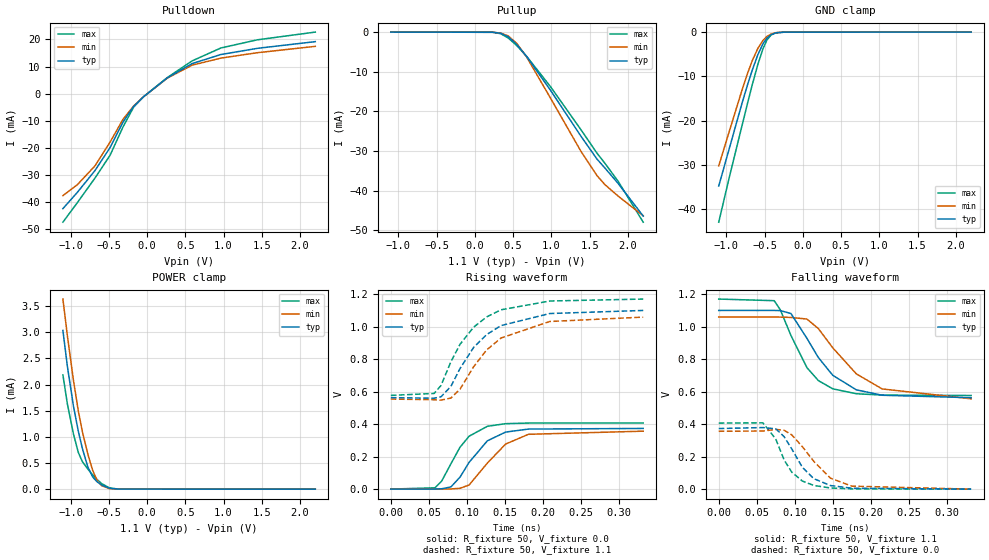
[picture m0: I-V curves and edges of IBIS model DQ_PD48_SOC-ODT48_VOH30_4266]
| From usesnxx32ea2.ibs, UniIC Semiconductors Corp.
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| DQ_PD48_SOC-ODT48_VOH30_4266
| (48 Ohm Pulldown, 48 Ohm System ODT Setting, VOH=VDDQ/3.0, 3200-4266Mbps)
[Model]   DQ_PD48_SOC-ODT48_VOH30_4266
Model_type   I/O
Vinl = 123.333mV
Vinh = 243.333mV
Vmeas = 183.333mV
Vref = 0.0mV
Cref = 0.0pF
Rref = 48.000Ohm
|   typ   min   max
|C_comp   0.834pF   0.784pF   0.884pF
C_comp_pullup   0.4170pF   0.3920pF   0.4420pF
C_comp_pulldown   0.4170pF   0.3920pF   0.4420pF
| Note: C_comp changes when the ODT circuit is enabled.
[Model Spec]
| Input threshold voltage corners
Vinl   0.1233V   0.1167V   0.1350V
Vinh   0.2433V   0.2367V   0.2550V
| Measurement voltage corners
Vmeas   0.1833V   0.1767V   0.1950V
| Timing spec test load voltage corners
Vref   0.0000V   0.0000V   0.0000V
| Dynamic Overshoot Parameters from LPDDR4 Specification
D_overshoot_ampl_h   0.30   NA   NA
D_overshoot_ampl_l   0.30   NA   NA
D_overshoot_area_h   0.1n   NA   NA
D_overshoot_area_l   0.1n   NA   NA
[Voltage Range]   1.1000V   1.0600V   1.1700V
[Pullup Reference]   1.1000V   1.0600V   1.1700V
| Junction Temperature (Ambient temp is 35C typ 95C min -40C max)
[Temperature Range]   50.0   110.0   -40.0
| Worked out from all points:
|   slope of the pulldown table from 0 to 0.165 V, typ, clamps not added: 43.9 ohm
|   slope of the pullup table from 0 to 0.165 V, typ, clamps not added: 15.7 kohm
|   GND clamp passes 1 mA (typ) near -0.45 V on its own axis
|   POWER clamp passes 1 mA (typ) near -0.88 V on its own axis
|   rising waveform, R_fixture 50, V_fixture 0.0: 20-80 % time 36.2ps typ, 40.6ps min, 31.9ps max; typ from 0.001 V to 0.373 V
|   falling waveform, R_fixture 50, V_fixture 1.1: 20-80 % time 49.2ps typ, 61ps min, 39.1ps max; typ from 1.1 V to 0.563 V
|   rising waveform, R_fixture 50, V_fixture 1.1: 20-80 % time 55.7ps typ, 58.6ps min, 51.8ps max; typ from 0.563 V to 1.1 V
|   falling waveform, R_fixture 50, V_fixture 0.0: 20-80 % time 32.4ps typ, 39.9ps min, 27.4ps max; typ from 0.373 V to 0.001 V
[Pulldown]
|   Voltage   I(typ)   I(min)   I(max)
-1.1V     -42.4mA    -37.62mA   -47.4mA
-911.9mV  -36.43mA   -33.59mA   -40.22mA
-680.9mV  -28.37mA   -26.64mA   -31.14mA
-482.9mV  -19.86mA   -17.85mA   -22.71mA
-314.6mV  -10.51mA   -9.476mA   -12.3mA
-176mV    -4.726mA   -4.587mA   -5.011mA
-47.3mV   -1.184mA   -1.177mA   -1.166mA
266.2mV   5.832mA    5.742mA    5.954mA
589.6mV   11.09mA    10.5mA     12.08mA
965.8mV   14.43mA    13.11mA    16.84mA
1.444V    16.71mA    15.1mA     19.86mA
2.2V      19.18mA    17.44mA    22.7mA
[GND Clamp]
|   Voltage   I(typ)   I(min)   I(max)
-1.1V     -34.74mA   -30.2mA    -42.91mA
-948.2mV  -25.43mA   -21.63mA   -31.79mA
-796.4mV  -16.11mA   -13.14mA   -21.19mA
-723.8mV  -11.93mA   -9.348mA   -16.1mA
-661.1mV  -8.566mA   -6.435mA   -11.85mA
-588.5mV  -5.112mA   -3.681mA   -7.299mA
-522.5mV  -2.666mA   -1.902mA   -3.81mA
-469.7mV  -1.356mA   -992.7uA   -1.786mA
-413.6mV  -564.8uA   -417.5uA   -621.5uA
-350.9mV  -166uA     -126.7uA   -147.9uA
-235.4mV  -8.3uA     -7.759uA   -4.464uA
2.2V      0A         0A         0A
[Pullup]
|   Voltage   I(typ)   I(min)   I(max)
-1.1V     5.229uA    8.059uA    2.358uA
233.2mV   -40.23uA   -40.58uA   -42.16uA
335.5mV   -284.9uA   -236.8uA   -392.1uA
437.8mV   -1.202mA   -984.9uA   -1.513mA
546.7mV   -3.115mA   -2.853mA   -3.399mA
675.4mV   -6.14mA    -6.273mA   -6.112mA
985.6mV   -14.62mA   -16.59mA   -13.71mA
1.388V    -26.34mA   -30.16mA   -24.7mA
1.596V    -32.06mA   -36.23mA   -30.58mA
1.698V    -34.29mA   -38.48mA   -33.08mA
1.873V    -38.23mA   -41.42mA   -37.69mA
2.2V      -46.44mA   -46.37mA   -47.99mA
[POWER Clamp]
|   Voltage   I(typ)   I(min)   I(max)
-1.1V     3.033mA    3.633mA    2.184mA
-1.041V   2.345mA    2.929mA    1.625mA
-961.4mV  1.581mA    2.073mA    1.051mA
-898.7mV  1.11mA     1.498mA    702.2uA
-845.9mV  780uA      1.103mA    527.5uA
-773.3mV  421uA      665.2uA    384.1uA
-710.6mV  232.4uA    359uA      273.1uA
-651.2mV  138.6uA    162.3uA    181.2uA
-591.8mV  77.92uA    64.83uA    105.5uA
-492.8mV  18.89uA    11.59uA    24.06uA
-374mV    1.385uA    999.3nA    1.123uA
2.2V      0A         0A         0A
[Ramp]
|   typ   min   max
| 20% - 80%
dV/dt_r   223.68m/36.23p   213.63m/40.56p   243.93m/31.88p
dV/dt_f   322.10m/49.17p   302.15m/60.99p   355.98m/39.04p
| 25% - 75%
|dV/dt_r   186.40m/28.84p   178.03m/32.35p   203.28m/25.32p
|dV/dt_f   268.41m/39.20p   251.79m/48.64p   296.65m/31.09p
R_load = 50
[Rising Waveform]
R_fixture = 50
V_fixture = 0.0
|   Time   V(typ)   V(min)   V(max)
0s        514.6uV    443.3uV    375.2uV
58ps      529.3uV    148.2uV    8.033mV
67ps      2.308mV    -205.7uV   50.16mV
79ps      13.47mV    1.162mV    155.5mV
91ps      73.54mV    5.154mV    257.6mV
103ps     164.9mV    25.41mV    325.6mV
127ps     297.2mV    160.2mV    386.4mV
151ps     350.9mV    277.1mV    402.6mV
181ps     369.4mV    337.2mV    406.4mV
332ps     373.3mV    356.5mV    406.9mV
[Falling Waveform]
R_fixture   = 50
V_fixture   = 1.1
V_fixture_min = 1.06
V_fixture_max = 1.17
|   Time   V(typ)   V(min)   V(max)
0s        1.1V       1.06V      1.17V
73ps      1.1V       1.06V      1.16V
81ps      1.099V     1.059V     1.104V
95ps      1.081V     1.057V     945.8mV
116ps     928.5mV    1.047V     748.2mV
131ps     810.4mV    988.5mV    668.6mV
150ps     700.9mV    870mV      617.7mV
181ps     611.6mV    709.7mV    587.5mV
215ps     578.2mV    617mV      579.2mV
332ps     563.2mV    556.4mV    576.7mV
[Rising Waveform]
R_fixture   = 50
V_fixture   = 1.1
V_fixture_min = 1.06
V_fixture_max = 1.17
|   Time   V(typ)   V(min)   V(max)
0s        562.8mV    553.9mV    576.6mV
57ps      559.1mV    550mV      588.5mV
66ps      568.1mV    547.2mV    637.4mV
79ps      631.5mV    560.2mV    783.2mV
91ps      741.5mV    614.4mV    890.5mV
109ps     871.9mV    753.3mV    996.5mV
126ps     950.3mV    855.7mV    1.059V
145ps     1.006V     929.5mV    1.103V
209ps     1.08V      1.031V     1.157V
332ps     1.099V     1.058V     1.169V
[Falling Waveform]
R_fixture = 50
V_fixture = 0.0
|   Time   V(typ)   V(min)   V(max)
0s        373.4mV    356.6mV    407mV
58ps      379.5mV    358.1mV    408.5mV
75ps      371.8mV    367.9mV    309.2mV
86ps      323.5mV    362.8mV    180.3mV
96ps      248.6mV    334.7mV    105.5mV
110ps     134.8mV    262mV      50.4mV
125ps     65.05mV    171.7mV    23.27mV
147ps     22.63mV    68.08mV    7.787mV
175ps     6.401mV    19.06mV    2.191mV
332ps     585.3uV    565.4uV    398.2uV
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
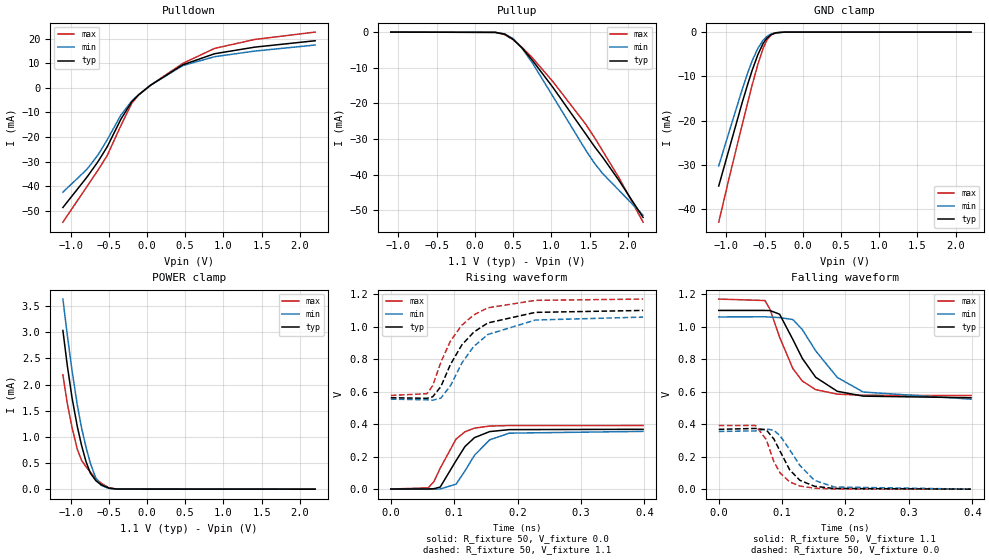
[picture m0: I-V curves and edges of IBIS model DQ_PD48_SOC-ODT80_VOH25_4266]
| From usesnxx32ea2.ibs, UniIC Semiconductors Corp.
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| DQ_PD48_SOC-ODT80_VOH25_4266
| (48 Ohm Pulldown, 80 Ohm System ODT Setting, VOH=VDDQ/2.5, 3200-4266Mbps)
[Model]   DQ_PD48_SOC-ODT80_VOH25_4266
Model_type   I/O
Vinl = 160.000mV
Vinh = 280.000mV
Vmeas = 220.000mV
Vref = 0.0mV
Cref = 0.0pF
Rref = 80.000Ohm
|   typ   min   max
|C_comp   0.834pF   0.784pF   0.884pF
C_comp_pullup   0.4170pF   0.3920pF   0.4420pF
C_comp_pulldown   0.4170pF   0.3920pF   0.4420pF
| Note: C_comp changes when the ODT circuit is enabled.
[Model Spec]
| Input threshold voltage corners
Vinl   0.1600V   0.1520V   0.1740V
Vinh   0.2800V   0.2720V   0.2940V
| Measurement voltage corners
Vmeas   0.2200V   0.2120V   0.2340V
| Timing spec test load voltage corners
Vref   0.0000V   0.0000V   0.0000V
| Dynamic Overshoot Parameters from LPDDR4 Specification
D_overshoot_ampl_h   0.30   NA   NA
D_overshoot_ampl_l   0.30   NA   NA
D_overshoot_area_h   0.1n   NA   NA
D_overshoot_area_l   0.1n   NA   NA
[Voltage Range]   1.1000V   1.0600V   1.1700V
[Pullup Reference]   1.1000V   1.0600V   1.1700V
| Junction Temperature (Ambient temp is 35C typ 95C min -40C max)
[Temperature Range]   50.0   110.0   -40.0
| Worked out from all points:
|   slope of the pulldown table from 0 to 0.165 V, typ, clamps not added: 43.8 ohm
|   slope of the pullup table from 0 to 0.165 V, typ, clamps not added: 17.8 kohm
|   GND clamp passes 1 mA (typ) near -0.45 V on its own axis
|   POWER clamp passes 1 mA (typ) near -0.88 V on its own axis
|   rising waveform, R_fixture 50, V_fixture 0.0: 20-80 % time 34.8ps typ, 38.4ps min, 31.7ps max; typ from 0.001 V to 0.368 V
|   falling waveform, R_fixture 50, V_fixture 1.1: 20-80 % time 49.2ps typ, 61.8ps min, 39ps max; typ from 1.1 V to 0.563 V
|   rising waveform, R_fixture 50, V_fixture 1.1: 20-80 % time 56.1ps typ, 59.2ps min, 51.8ps max; typ from 0.563 V to 1.1 V
|   falling waveform, R_fixture 50, V_fixture 0.0: 20-80 % time 32.7ps typ, 40ps min, 27.1ps max; typ from 0.368 V to 0.001 V
[Pulldown]
|   Voltage   I(typ)   I(min)   I(max)
-1.1V     -48.66mA   -42.44mA   -54.64mA
-783.2mV  -36.22mA   -33.06mA   -40.03mA
-638mV    -29.88mA   -27.18mA   -33.36mA
-519.2mV  -23.9mA    -21.07mA   -27.46mA
-341mV    -12.73mA   -11.05mA   -15.31mA
-199.1mV  -5.663mA   -5.347mA   -6.275mA
-113.3mV  -2.934mA   -2.879mA   -2.976mA
48.4mV    1.124mA    1.121mA    1.122mA
467.5mV   9.38mA     9.055mA    9.949mA
883.3mV   13.89mA    12.68mA    16.05mA
1.408V    16.57mA    14.97mA    19.69mA
2.2V      19.18mA    17.44mA    22.7mA
[GND Clamp]
|   Voltage   I(typ)   I(min)   I(max)
-1.1V     -34.75mA   -30.21mA   -42.92mA
-944.9mV  -25.23mA   -21.44mA   -31.56mA
-793.1mV  -15.92mA   -12.96mA   -20.97mA
-720.5mV  -11.75mA   -9.182mA   -15.88mA
-661.1mV  -8.569mA   -6.433mA   -11.86mA
-588.5mV  -5.114mA   -3.68mA    -7.306mA
-519.2mV  -2.565mA   -1.833mA   -3.664mA
-469.7mV  -1.357mA   -986.9uA   -1.789mA
-413.6mV  -566.1uA   -417.5uA   -621.9uA
-354.2mV  -178.1uA   -134.8uA   -159.6uA
-242mV    -10.08uA   -9.206uA   -5.668uA
2.2V      0A         0A         0A
[Pullup]
|   Voltage   I(typ)   I(min)   I(max)
-1.1V     4.106uA    7.431uA    1.361uA
266.2mV   -68.96uA   -66.85uA   -71.69uA
391.6mV   -602.9uA   -502.3uA   -718.8uA
503.8mV   -2.098mA   -1.888mA   -2.196mA
616mV     -4.451mA   -4.476mA   -4.26mA
754.6mV   -7.982mA   -8.738mA   -7.279mA
1.022V    -15.58mA   -18.09mA   -13.95mA
1.448V    -28.55mA   -33.09mA   -25.83mA
1.566V    -32.18mA   -36.88mA   -29.66mA
1.672V    -35.17mA   -39.74mA   -33.39mA
1.887V    -41.73mA   -44.49mA   -41mA
2.2V      -52.05mA   -51.41mA   -53.39mA
[POWER Clamp]
|   Voltage   I(typ)   I(min)   I(max)
-1.1V     3.033mA    3.633mA    2.184mA
-1.044V   2.381mA    2.967mA    1.653mA
-981.2mV  1.753mA    2.275mA    1.183mA
-911.9mV  1.2mA      1.611mA    764.5uA
-855.8mV  837.7uA    1.171mA    552.1uA
-796.4mV  521.3uA    794.8uA    427.2uA
-740.3mV  306.2uA    494.3uA    324.2uA
-667.7mV  159.9uA    206.1uA    205.2uA
-598.4mV  83.65uA    71.98uA    113.1uA
-499.4mV  21.36uA    13.16uA    27.46uA
-397.1mV  2.375uA    1.585uA    2.11uA
2.2V      0A         0A         0A
[Ramp]
|   typ   min   max
| 20% - 80%
dV/dt_r   220.63m/34.77p   212.96m/38.41p   234.70m/31.71p
dV/dt_f   322.27m/49.23p   303.39m/61.76p   356.00m/38.99p
| 25% - 75%
|dV/dt_r   183.86m/27.68p   177.47m/30.60p   195.58m/25.19p
|dV/dt_f   268.56m/39.26p   252.82m/49.26p   296.66m/31.04p
R_load = 50
[Rising Waveform]
R_fixture = 50
V_fixture = 0.0
|   Time   V(typ)   V(min)   V(max)
0s        642.1uV    518.8uV    473.3uV
59ps      752.9uV    89.61uV    7.998mV
68ps      2.748mV    -236.7uV   46.15mV
78ps      12.91mV    1.096mV    129.3mV
103ps     175.6mV    30.58mV    308.5mV
117ps     262.1mV    111.9mV    353mV
132ps     316.9mV    208.7mV    375.6mV
156ps     354.2mV    303.5mV    388.2mV
187ps     366.2mV    344.6mV    391.3mV
398ps     368.4mV    355.5mV    391.6mV
[Falling Waveform]
R_fixture   = 50
V_fixture   = 1.1
V_fixture_min = 1.06
V_fixture_max = 1.17
|   Time   V(typ)   V(min)   V(max)
0s        1.1V       1.06V      1.17V
73ps      1.1V       1.061V     1.161V
81ps      1.099V     1.059V     1.106V
96ps      1.077V     1.056V     935.8mV
117ps     921mV      1.044V     742.1mV
132ps     804.2mV    981.7mV    665.2mV
153ps     688.7mV    851.4mV    612.8mV
187ps     602.7mV    688mV      585.1mV
228ps     572.8mV    598.1mV    578.1mV
398ps     562.9mV    554.3mV    576.7mV
[Rising Waveform]
R_fixture   = 50
V_fixture   = 1.1
V_fixture_min = 1.06
V_fixture_max = 1.17
|   Time   V(typ)   V(min)   V(max)
0s        562.8mV    553.9mV    576.6mV
57ps      559mV      549.9mV    587.4mV
66ps      568.1mV    547mV      635.7mV
79ps      631.2mV    560.3mV    781.3mV
94ps      766.8mV    636.3mV    910.9mV
112ps     887.5mV    775.9mV    1.009V
131ps     967.2mV    878.9mV    1.073V
153ps     1.023V     951.5mV    1.116V
228ps     1.088V     1.041V     1.162V
398ps     1.1V       1.059V     1.17V
[Falling Waveform]
R_fixture = 50
V_fixture = 0.0
|   Time   V(typ)   V(min)   V(max)
0s        368.5mV    355.6mV    391.7mV
58ps      374.1mV    358.9mV    392.2mV
75ps      365.5mV    370.5mV    305.8mV
87ps      309.2mV    362.8mV    169.8mV
97ps      232.5mV    328.3mV    99.23mV
112ps     119.2mV    242.5mV    45.03mV
128ps     55.03mV    147mV      19.78mV
151ps     18.4mV     54.75mV    6.377mV
182ps     4.771mV    13.9mV     1.712mV
398ps     686.6uV    587.3uV    490.8uV
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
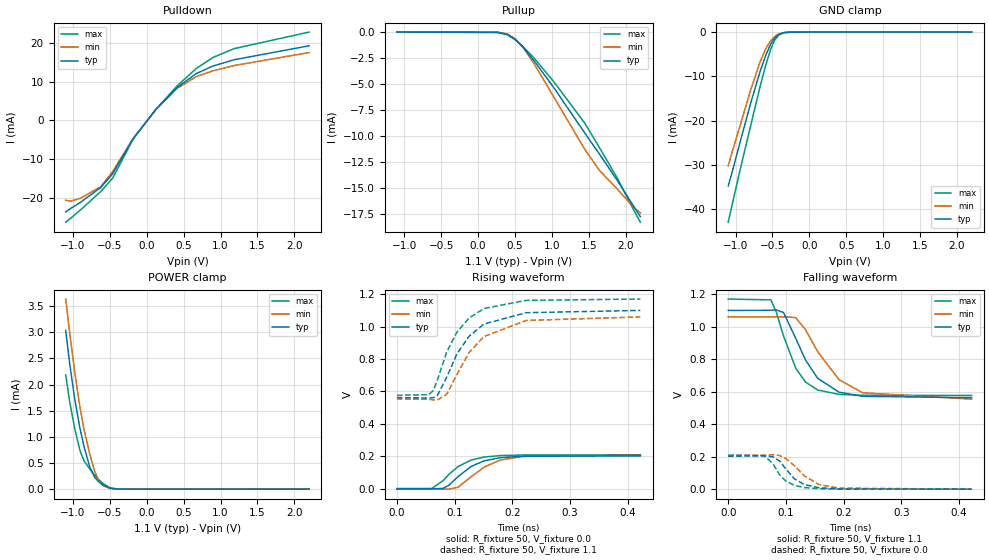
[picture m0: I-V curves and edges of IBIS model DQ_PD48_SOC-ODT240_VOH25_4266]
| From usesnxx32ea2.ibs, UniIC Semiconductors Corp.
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| DQ_PD48_SOC-ODT240_VOH25_4266
| (48 Ohm Pulldown, 240 Ohm System ODT Setting, VOH=VDDQ/2.5, 3200-4266Mbps)
[Model]   DQ_PD48_SOC-ODT240_VOH25_4266
Model_type   I/O
Vinl = 160.000mV
Vinh = 280.000mV
Vmeas = 220.000mV
Vref = 0.0mV
Cref = 0.0pF
Rref = 240.000Ohm
|   typ   min   max
|C_comp   0.834pF   0.784pF   0.884pF
C_comp_pullup   0.4170pF   0.3920pF   0.4420pF
C_comp_pulldown   0.4170pF   0.3920pF   0.4420pF
| Note: C_comp changes when the ODT circuit is enabled.
[Model Spec]
| Input threshold voltage corners
Vinl   0.1600V   0.1520V   0.1740V
Vinh   0.2800V   0.2720V   0.2940V
| Measurement voltage corners
Vmeas   0.2200V   0.2120V   0.2340V
| Timing spec test load voltage corners
Vref   0.0000V   0.0000V   0.0000V
| Dynamic Overshoot Parameters from LPDDR4 Specification
D_overshoot_ampl_h   0.30   NA   NA
D_overshoot_ampl_l   0.30   NA   NA
D_overshoot_area_h   0.1n   NA   NA
D_overshoot_area_l   0.1n   NA   NA
[Voltage Range]   1.1000V   1.0600V   1.1700V
[Pullup Reference]   1.1000V   1.0600V   1.1700V
| Junction Temperature (Ambient temp is 35C typ 95C min -40C max)
[Temperature Range]   50.0   110.0   -40.0
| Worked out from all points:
|   slope of the pulldown table from 0 to 0.165 V, typ, clamps not added: 44 ohm
|   slope of the pullup table from 0 to 0.165 V, typ, clamps not added: 54.3 kohm
|   GND clamp passes 1 mA (typ) near -0.45 V on its own axis
|   POWER clamp passes 1 mA (typ) near -0.88 V on its own axis
|   rising waveform, R_fixture 50, V_fixture 0.0: 20-80 % time 46.9ps typ, 50.9ps min, 43.3ps max; typ from 0 V to 0.203 V
|   falling waveform, R_fixture 50, V_fixture 1.1: 20-80 % time 48.8ps typ, 60.9ps min, 38.7ps max; typ from 1.1 V to 0.563 V
|   rising waveform, R_fixture 50, V_fixture 1.1: 20-80 % time 56.7ps typ, 61.1ps min, 52.2ps max; typ from 0.563 V to 1.1 V
|   falling waveform, R_fixture 50, V_fixture 0.0: 20-80 % time 32.4ps typ, 40.3ps min, 27.4ps max; typ from 0.203 V to 0 V
[Pulldown]
|   Voltage   I(typ)   I(min)   I(max)
-1.1V     -23.51mA   -20.52mA   -26.16mA
-1.034V   -22.65mA   -20.74mA   -25.16mA
-905.3mV  -21.13mA   -20.07mA   -23.1mA
-628.1mV  -17.31mA   -17.08mA   -18.35mA
-463.1mV  -13.73mA   -13.15mA   -14.84mA
-185.9mV  -4.698mA   -4.657mA   -4.804mA
124.3mV   2.854mA    2.833mA    2.859mA
411.4mV   8.481mA    8.245mA    8.891mA
668.8mV   12.01mA    11.23mA    13.32mA
896.5mV   13.98mA    12.75mA    16.18mA
1.184V    15.59mA    14.1mA     18.45mA
2.2V      19.18mA    17.44mA    22.7mA
[GND Clamp]
|   Voltage   I(typ)   I(min)   I(max)
-1.1V     -34.75mA   -30.2mA    -42.92mA
-1.047V   -31.66mA   -27.14mA   -39.03mA
-938.3mV  -24.82mA   -21.07mA   -31.09mA
-793.1mV  -15.92mA   -12.96mA   -20.97mA
-667.7mV  -8.911mA   -6.72mA    -12.3mA
-588.5mV  -5.115mA   -3.68mA    -7.306mA
-522.5mV  -2.666mA   -1.902mA   -3.814mA
-469.7mV  -1.358mA   -987.5uA   -1.789mA
-413.6mV  -565.3uA   -417.8uA   -621.9uA
-344.3mV  -143.3uA   -109.7uA   -124.6uA
-245.3mV  -11.02uA   -10.05uA   -6.351uA
2.2V      0A         0A         0A
[Pullup]
|   Voltage   I(typ)   I(min)   I(max)
-1.1V     1.369uA    2.477uA    453.9nA
269.5mV   -24.6uA    -23.58uA   -25.87uA
398.2mV   -222.5uA   -184uA     -262.6uA
507.1mV   -727.4uA   -657.3uA   -757.1uA
612.7mV   -1.479mA   -1.488mA   -1.414mA
761.2mV   -2.766mA   -3.051mA   -2.511mA
1.032V    -5.389mA   -6.293mA   -4.81mA
1.448V    -9.706mA   -11.28mA   -8.764mA
1.642V    -11.68mA   -13.25mA   -11.05mA
1.887V    -14.24mA   -15.08mA   -14.02mA
2.114V    -16.79mA   -16.85mA   -17.14mA
2.2V      -17.73mA   -17.38mA   -18.26mA
[POWER Clamp]
|   Voltage   I(typ)   I(min)   I(max)
-1.1V     3.033mA    3.633mA    2.184mA
-1.044V   2.381mA    2.967mA    1.653mA
-977.9mV  1.723mA    2.241mA    1.161mA
-908.6mV  1.177mA    1.582mA    748.6uA
-852.5mV  818.1uA    1.148mA    543.5uA
-773.3mV  420.6uA    665.2uA    384.1uA
-707.3mV  225.4uA    345.3uA    267.6uA
-654.5mV  142.6uA    170.4uA    185.9uA
-591.8mV  77.97uA    64.81uA    105.5uA
-496.1mV  20.08uA    12.37uA    25.72uA
-390.5mV  2.035uA    1.391uA    1.769uA
2.2V      0A         0A         0A
[Ramp]
|   typ   min   max
| 20% - 80%
dV/dt_r   121.53m/46.90p   123.83m/50.91p   125.32m/43.34p
dV/dt_f   322.26m/48.76p   303.49m/60.92p   355.99m/38.71p
| 25% - 75%
|dV/dt_r   101.28m/37.35p   103.20m/40.56p   104.43m/34.46p
|dV/dt_f   268.55m/38.88p   252.91m/48.58p   296.66m/30.82p
R_load = 50
[Rising Waveform]
R_fixture = 50
V_fixture = 0.0
|   Time   V(typ)   V(min)   V(max)
0s        202.4uV    147.1uV    155.5uV
60ps      -310.2uV   349.4uV    590.2uV
80ps      1.743mV    -1.826mV   49.41mV
90ps      21.31mV    -2.806mV   87.95mV
106ps     74.67mV    9.24mV     137mV
129ps     138.1mV    74.64mV    177.4mV
152ps     172.9mV    135.7mV    195.7mV
180ps     191.8mV    177.6mV    204.5mV
219ps     200.2mV    199.4mV    208mV
422ps     202.8mV    206.5mV    209mV
[Falling Waveform]
R_fixture   = 50
V_fixture   = 1.1
V_fixture_min = 1.06
V_fixture_max = 1.17
|   Time   V(typ)   V(min)   V(max)
0s        1.1V       1.06V      1.17V
74ps      1.101V     1.06V      1.165V
83ps      1.104V     1.06V      1.094V
96ps      1.087V     1.061V     942.8mV
117ps     928.8mV    1.056V     745.3mV
134ps     795.5mV    981.8mV    659.5mV
155ps     682.9mV    847.2mV    610.5mV
192ps     597.2mV    674.5mV    583.6mV
233ps     571.4mV    593.3mV    577.9mV
422ps     562.9mV    554.2mV    576.7mV
[Rising Waveform]
R_fixture   = 50
V_fixture   = 1.1
V_fixture_min = 1.06
V_fixture_max = 1.17
|   Time   V(typ)   V(min)   V(max)
0s        562.7mV    553.9mV    576.6mV
55ps      559mV      551.4mV    579.8mV
63ps      561.5mV    548.2mV    606mV
70ps      574.8mV    547.8mV    668.5mV
86ps      685.1mV    581mV      841mV
104ps     832.2mV    704.5mV    966.2mV
125ps     940.3mV    839.9mV    1.053V
151ps     1.016V     938.8mV    1.112V
224ps     1.086V     1.038V     1.162V
422ps     1.1V       1.06V      1.17V
[Falling Waveform]
R_fixture = 50
V_fixture = 0.0
|   Time   V(typ)   V(min)   V(max)
0s        202.8mV    206.6mV    209.1mV
62ps      205.3mV    208.9mV    207.6mV
78ps      198.9mV    212.5mV    155.2mV
89ps      173.7mV    207.4mV    88.9mV
100ps     124.2mV    188.3mV    50.27mV
115ps     63.71mV    143.9mV    23.49mV
132ps     28.74mV    82.69mV    9.972mV
157ps     9.097mV    28.79mV    2.959mV
192ps     2.047mV    6.537mV    669.7uV
422ps     265.7uV    239.7uV    175.1uV
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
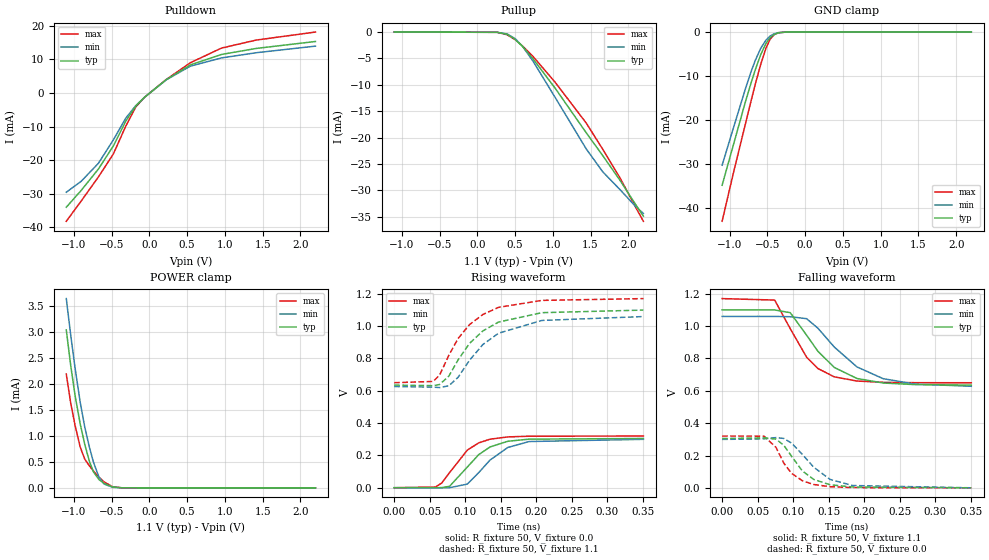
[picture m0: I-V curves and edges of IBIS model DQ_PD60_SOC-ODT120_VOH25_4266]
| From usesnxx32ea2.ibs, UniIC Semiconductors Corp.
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| DQ_PD60_SOC-ODT120_VOH25_4266
| (60 Ohm Pulldown, 120 Ohm System ODT Setting, VOH=VDDQ/2.5, 3200-4266Mbps)
[Model]   DQ_PD60_SOC-ODT120_VOH25_4266
Model_type   I/O
Vinl = 160.000mV
Vinh = 280.000mV
Vmeas = 220.000mV
Vref = 0.0mV
Cref = 0.0pF
Rref = 120.000Ohm
|   typ   min   max
|C_comp   0.834pF   0.784pF   0.884pF
C_comp_pullup   0.4170pF   0.3920pF   0.4420pF
C_comp_pulldown   0.4170pF   0.3920pF   0.4420pF
| Note: C_comp changes when the ODT circuit is enabled.
[Model Spec]
| Input threshold voltage corners
Vinl   0.1600V   0.1520V   0.1740V
Vinh   0.2800V   0.2720V   0.2940V
| Measurement voltage corners
Vmeas   0.2200V   0.2120V   0.2340V
| Timing spec test load voltage corners
Vref   0.0000V   0.0000V   0.0000V
| Dynamic Overshoot Parameters from LPDDR4 Specification
D_overshoot_ampl_h   0.30   NA   NA
D_overshoot_ampl_l   0.30   NA   NA
D_overshoot_area_h   0.1n   NA   NA
D_overshoot_area_l   0.1n   NA   NA
[Voltage Range]   1.1000V   1.0600V   1.1700V
[Pullup Reference]   1.1000V   1.0600V   1.1700V
| Junction Temperature (Ambient temp is 35C typ 95C min -40C max)
[Temperature Range]   50.0   110.0   -40.0
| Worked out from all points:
|   slope of the pulldown table from 0 to 0.165 V, typ, clamps not added: 54.9 ohm
|   slope of the pullup table from 0 to 0.165 V, typ, clamps not added: 26.3 kohm
|   GND clamp passes 1 mA (typ) near -0.45 V on its own axis
|   POWER clamp passes 1 mA (typ) near -0.88 V on its own axis
|   rising waveform, R_fixture 50, V_fixture 0.0: 20-80 % time 40ps typ, 43.4ps min, 36.5ps max; typ from 0 V to 0.305 V
|   falling waveform, R_fixture 50, V_fixture 1.1: 20-80 % time 53.6ps typ, 65.5ps min, 43.1ps max; typ from 1.1 V to 0.635 V
|   rising waveform, R_fixture 50, V_fixture 1.1: 20-80 % time 56ps typ, 59.7ps min, 52.2ps max; typ from 0.635 V to 1.1 V
|   falling waveform, R_fixture 50, V_fixture 0.0: 20-80 % time 34.9ps typ, 42.2ps min, 29.8ps max; typ from 0.305 V to 0.001 V
[Pulldown]
|   Voltage   I(typ)   I(min)   I(max)
-1.1V     -33.99mA   -29.53mA   -38.17mA
-902mV    -28.97mA   -26.26mA   -32.13mA
-674.3mV  -22.61mA   -20.9mA    -24.96mA
-476.3mV  -15.73mA   -13.94mA   -18.13mA
-311.3mV  -8.337mA   -7.45mA    -9.804mA
-179.3mV  -3.878mA   -3.74mA    -4.141mA
-60.5mV   -1.213mA   -1.203mA   -1.197mA
223.3mV   3.969mA    3.921mA    4.022mA
543.4mV   8.374mA    7.997mA    9.019mA
955.9mV   11.48mA    10.45mA    13.38mA
1.415V    13.27mA    11.99mA    15.76mA
2.2V      15.34mA    13.95mA    18.15mA
[GND Clamp]
|   Voltage   I(typ)   I(min)   I(max)
-1.1V     -34.75mA   -30.21mA   -42.92mA
-944.9mV  -25.23mA   -21.44mA   -31.56mA
-789.8mV  -15.73mA   -12.78mA   -20.73mA
-717.2mV  -11.57mA   -9.02mA    -15.65mA
-661.1mV  -8.569mA   -6.434mA   -11.86mA
-588.5mV  -5.114mA   -3.68mA    -7.305mA
-519.2mV  -2.565mA   -1.832mA   -3.663mA
-466.4mV  -1.297mA   -941.6uA   -1.692mA
-413.6mV  -563.9uA   -416.2uA   -621.7uA
-354.2mV  -178.8uA   -135.1uA   -159.9uA
-258.5mV  -16.02uA   -14.23uA   -9.822uA
2.2V      0A         0A         0A
[Pullup]
|   Voltage   I(typ)   I(min)   I(max)
-1.1V     2.737uA    4.953uA    907.4nA
262.9mV   -43.08uA   -41.77uA   -44.36uA
394.9mV   -422.3uA   -349.8uA   -501.4uA
503.8mV   -1.404mA   -1.264mA   -1.469mA
602.8mV   -2.777mA   -2.764mA   -2.675mA
738.1mV   -5.057mA   -5.503mA   -4.622mA
1.032V    -10.65mA   -12.4mA    -9.525mA
1.444V    -19.1mA    -22.16mA   -17.26mA
1.662V    -23.42mA   -26.49mA   -22.21mA
1.89V     -28.09mA   -29.85mA   -27.63mA
2.094V    -32.61mA   -33.01mA   -33.1mA
2.2V      -34.89mA   -34.37mA   -35.86mA
[POWER Clamp]
|   Voltage   I(typ)   I(min)   I(max)
-1.1V     3.033mA    3.633mA    2.184mA
-1.041V   2.345mA    2.929mA    1.625mA
-984.5mV  1.782mA    2.31mA     1.205mA
-915.2mV  1.224mA    1.639mA    781.1uA
-855.8mV  837.6uA    1.171mA    552.1uA
-793.1mV  505.9uA    775.7uA    420.9uA
-740.3mV  306.1uA    494.3uA    324.2uA
-667.7mV  159.9uA    206.1uA    205.2uA
-598.4mV  83.64uA    71.95uA    113uA
-486.2mV  16.69uA    10.13uA    20.93uA
-367.4mV  1.191uA    872.9nA    946nA
2.2V      0A         0A         0A
[Ramp]
|   typ   min   max
| 20% - 80%
dV/dt_r   182.57m/39.96p   179.61m/43.41p   191.84m/36.49p
dV/dt_f   278.78m/53.56p   259.05m/65.54p   312.07m/43.15p
| 25% - 75%
|dV/dt_r   152.14m/31.79p   149.68m/34.57p   159.87m/28.98p
|dV/dt_f   232.31m/42.68p   215.87m/52.30p   260.06m/34.29p
R_load = 50
[Rising Waveform]
R_fixture = 50
V_fixture = 0.0
|   Time   V(typ)   V(min)   V(max)
0s        482.2uV    387.1uV    356.9uV
58ps      289.7uV    95.84uV    4.566mV
67ps      1.337mV    -341.5uV   29.58mV
78ps      9.18mV     398.4uV    93.78mV
103ps     128.2mV    22.86mV    232.9mV
119ps     204.8mV    93.52mV    277.7mV
135ps     252.5mV    171.4mV    300.5mV
160ps     287.7mV    249.2mV    314.6mV
190ps     300.8mV    286mV      319mV
351ps     304.8mV    299.7mV    320.1mV
[Falling Waveform]
R_fixture   = 50
V_fixture   = 1.1
V_fixture_min = 1.06
V_fixture_max = 1.17
|   Time   V(typ)   V(min)   V(max)
0s        1.1V       1.06V      1.17V
74ps      1.1V       1.06V      1.161V
96ps      1.083V     1.058V     983.9mV
119ps     943.9mV    1.046V     807.8mV
135ps     844.2mV    986.8mV    737.5mV
158ps     744.4mV    870.6mV    686.3mV
190ps     676.2mV    747.5mV    660.5mV
227ps     648.2mV    674.9mV    652.5mV
272ps     638.4mV    641.5mV    650.3mV
351ps     635.4mV    628.2mV    649.9mV
[Rising Waveform]
R_fixture   = 50
V_fixture   = 1.1
V_fixture_min = 1.06
V_fixture_max = 1.17
|   Time   V(typ)   V(min)   V(max)
0s        635mV      626.1mV    649.8mV
55ps      631.5mV    622.5mV    657.7mV
64ps      638.8mV    619.7mV    697.2mV
77ps      690.8mV    631mV      819.8mV
90ps      790.7mV    683.3mV    923.1mV
106ps     892.5mV    788.1mV    1.009V
125ps     970.4mV    886.4mV    1.072V
147ps     1.025V     956mV      1.116V
208ps     1.083V     1.035V     1.159V
351ps     1.099V     1.059V     1.17V
[Falling Waveform]
R_fixture = 50
V_fixture = 0.0
|   Time   V(typ)   V(min)   V(max)
0s        304.9mV    299.8mV    320.2mV
59ps      309.3mV    302.9mV    319.9mV
76ps      301.4mV    311.1mV    249.7mV
87ps      262.6mV    305.6mV    152.1mV
98ps      194.6mV    276.5mV    89.58mV
113ps     104.9mV    207.1mV    44.28mV
129ps     52.37mV    128mV      20.99mV
152ps     19.39mV    52.39mV    7.429mV
184ps     5.296mV    14.63mV    2.012mV
351ps     553.4uV    511.3uV    381.1uV
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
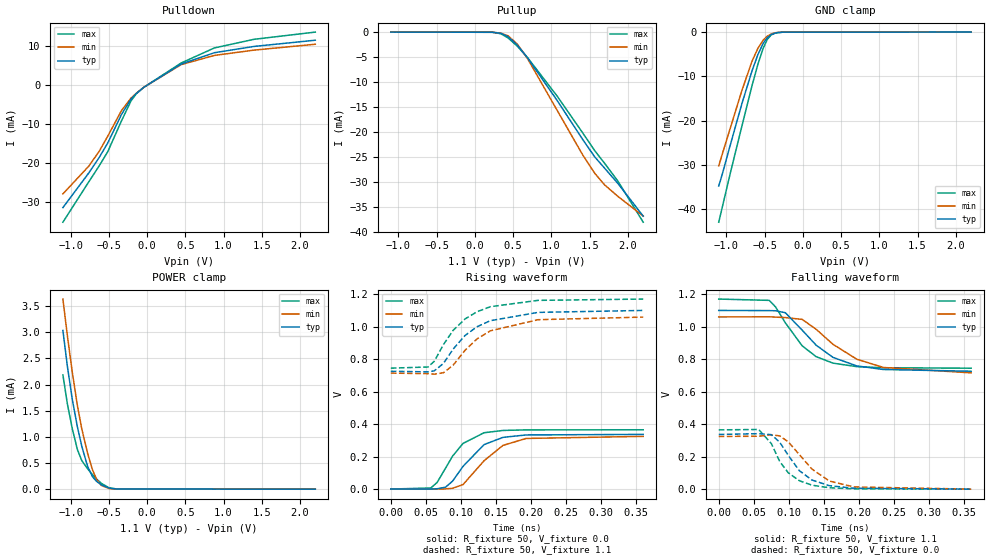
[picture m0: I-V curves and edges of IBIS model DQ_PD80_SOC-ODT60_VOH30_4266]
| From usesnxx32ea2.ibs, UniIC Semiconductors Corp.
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| DQ_PD80_SOC-ODT60_VOH30_4266
| (80 Ohm Pulldown, 60 Ohm System ODT Setting, VOH=VDDQ/3.0, 3200-4266Mbps)
[Model]   DQ_PD80_SOC-ODT60_VOH30_4266
Model_type   I/O
Vinl = 123.333mV
Vinh = 243.333mV
Vmeas = 183.333mV
Vref = 0.0mV
Cref = 0.0pF
Rref = 60.000Ohm
|   typ   min   max
|C_comp   0.834pF   0.784pF   0.884pF
C_comp_pullup   0.4170pF   0.3920pF   0.4420pF
C_comp_pulldown   0.4170pF   0.3920pF   0.4420pF
| Note: C_comp changes when the ODT circuit is enabled.
[Model Spec]
| Input threshold voltage corners
Vinl   0.1233V   0.1167V   0.1350V
Vinh   0.2433V   0.2367V   0.2550V
| Measurement voltage corners
Vmeas   0.1833V   0.1767V   0.1950V
| Timing spec test load voltage corners
Vref   0.0000V   0.0000V   0.0000V
| Dynamic Overshoot Parameters from LPDDR4 Specification
D_overshoot_ampl_h   0.30   NA   NA
D_overshoot_ampl_l   0.30   NA   NA
D_overshoot_area_h   0.1n   NA   NA
D_overshoot_area_l   0.1n   NA   NA
[Voltage Range]   1.1000V   1.0600V   1.1700V
[Pullup Reference]   1.1000V   1.0600V   1.1700V
| Junction Temperature (Ambient temp is 35C typ 95C min -40C max)
[Temperature Range]   50.0   110.0   -40.0
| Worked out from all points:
|   slope of the pulldown table from 0 to 0.165 V, typ, clamps not added: 74.2 ohm
|   slope of the pullup table from 0 to 0.165 V, typ, clamps not added: 19.5 kohm
|   GND clamp passes 1 mA (typ) near -0.45 V on its own axis
|   POWER clamp passes 1 mA (typ) near -0.88 V on its own axis
|   rising waveform, R_fixture 50, V_fixture 0.0: 20-80 % time 39.9ps typ, 44ps min, 34.9ps max; typ from 0.001 V to 0.337 V
|   falling waveform, R_fixture 50, V_fixture 1.1: 20-80 % time 57.8ps typ, 68.2ps min, 47.2ps max; typ from 1.1 V to 0.726 V
|   rising waveform, R_fixture 50, V_fixture 1.1: 20-80 % time 55.6ps typ, 57.7ps min, 52.2ps max; typ from 0.726 V to 1.1 V
|   falling waveform, R_fixture 50, V_fixture 0.0: 20-80 % time 38ps typ, 44.8ps min, 33.1ps max; typ from 0.337 V to 0.001 V
[Pulldown]
|   Voltage   I(typ)   I(min)   I(max)
-1.1V     -31.57mA   -28.05mA   -35.32mA
-760.1mV  -22.62mA   -20.87mA   -24.9mA
-624.8mV  -18.66mA   -17.07mA   -20.81mA
-512.6mV  -14.91mA   -13.17mA   -17.15mA
-334.4mV  -7.639mA   -6.616mA   -9.272mA
-209mV    -3.641mA   -3.404mA   -4.117mA
-139.7mV  -2.203mA   -2.144mA   -2.284mA
-40.7mV   -612.3uA   -606.3uA   -599.1uA
447.7mV   5.369mA    5.214mA    5.637mA
880mV     8.263mA    7.563mA    9.488mA
1.398V    9.879mA    8.934mA    11.71mA
2.2V      11.48mA    10.44mA    13.57mA
[GND Clamp]
|   Voltage   I(typ)   I(min)   I(max)
-1.1V     -34.74mA   -30.21mA   -42.91mA
-1.05V    -31.86mA   -27.33mA   -39.27mA
-941.6mV  -25.02mA   -21.26mA   -31.32mA
-796.4mV  -16.11mA   -13.14mA   -21.19mA
-664.4mV  -8.736mA   -6.578mA   -12.07mA
-588.5mV  -5.113mA   -3.681mA   -7.299mA
-519.2mV  -2.564mA   -1.832mA   -3.66mA
-466.4mV  -1.296mA   -941.8uA   -1.692mA
-413.6mV  -564.5uA   -418.4uA   -621.3uA
-354.2mV  -178.2uA   -135.3uA   -159.9uA
-258.5mV  -16.01uA   -14.34uA   -9.887uA
2.2V      0A         0A         0A
[Pullup]
|   Voltage   I(typ)   I(min)   I(max)
-1.1V     4.184uA    6.447uA    1.886uA
229.9mV   -30.19uA   -30.5uA    -31.03uA
338.8mV   -242.1uA   -199.7uA   -331.4uA
434.5mV   -925.6uA   -756.7uA   -1.171mA
553.3mV   -2.6mA     -2.398mA   -2.819mA
685.3mV   -5.106mA   -5.247mA   -5.061mA
1.075V    -13.71mA   -15.69mA   -12.83mA
1.411V    -21.57mA   -24.66mA   -20.25mA
1.566V    -25.01mA   -28.3mA    -23.76mA
1.695V    -27.27mA   -30.62mA   -26.29mA
1.87V     -30.35mA   -32.94mA   -29.89mA
2.2V      -36.89mA   -36.87mA   -38.1mA
[POWER Clamp]
|   Voltage   I(typ)   I(min)   I(max)
-1.1V     3.033mA    3.633mA    2.184mA
-1.041V   2.345mA    2.929mA    1.625mA
-977.9mV  1.723mA    2.241mA    1.16mA
-911.9mV  1.2mA      1.61mA     763.9uA
-852.5mV  818.2uA    1.148mA    543.6uA
-776.6mV  434.1uA    683.2uA    390.2uA
-713.9mV  239.3uA    373uA      278.6uA
-657.8mV  146.8uA    178.8uA    190.6uA
-595.1mV  80.78uA    68.28uA    109.2uA
-496.1mV  20.09uA    12.35uA    25.7uA
-390.5mV  2.037uA    1.393uA    1.77uA
2.2V      0A         0A         0A
[Ramp]
|   typ   min   max
| 20% - 80%
dV/dt_r   201.79m/39.95p   194.53m/44.01p   218.86m/34.95p
dV/dt_f   224.44m/57.74p   206.41m/68.16p   255.16m/47.10p
| 25% - 75%
|dV/dt_r   168.16m/31.83p   162.10m/35.09p   182.39m/27.83p
|dV/dt_f   187.04m/45.94p   172.01m/54.30p   212.63m/37.45p
R_load = 50
[Rising Waveform]
R_fixture = 50
V_fixture = 0.0
|   Time   V(typ)   V(min)   V(max)
0s        535.6uV    465.1uV    389.5uV
57ps      183.7uV    -5.999uV   6.857mV
66ps      2.126mV    -363.7uV   40.71mV
78ps      11.83mV    1.452mV    128.3mV
88ps      48.53mV    5.024mV    202.5mV
103ps     140.2mV    27.9mV     281.3mV
133ps     274mV      174.7mV    347mV
160ps     318.5mV    269.2mV    361.2mV
193ps     333.5mV    311.9mV    364.6mV
360ps     336.8mV    324.7mV    365.2mV
[Falling Waveform]
R_fixture   = 50
V_fixture   = 1.1
V_fixture_min = 1.06
V_fixture_max = 1.17
|   Time   V(typ)   V(min)   V(max)
0s        1.1V       1.06V      1.17V
72ps      1.099V     1.061V     1.162V
81ps      1.098V     1.059V     1.122V
95ps      1.086V     1.056V     1.024V
119ps     978.8mV    1.045V     882.2mV
139ps     886mV      983.9mV    815.6mV
163ps     811.1mV    891.5mV    775.8mV
197ps     758.5mV    799.7mV    754.2mV
235ps     736.6mV    749.1mV    747.3mV
360ps     725.9mV    716mV      744.7mV
[Rising Waveform]
R_fixture   = 50
V_fixture   = 1.1
V_fixture_min = 1.06
V_fixture_max = 1.17
|   Time   V(typ)   V(min)   V(max)
0s        725.5mV    714.2mV    744.7mV
53ps      721.7mV    710.8mV    751.7mV
62ps      728.1mV    707.8mV    787.1mV
75ps      773.5mV    716.3mV    889.5mV
89ps      862.5mV    763.4mV    978mV
106ps     946.4mV    855.2mV    1.048V
123ps     999.6mV    925mV      1.092V
142ps     1.037V     974.4mV    1.123V
210ps     1.088V     1.043V     1.162V
360ps     1.1V       1.059V     1.17V
[Falling Waveform]
R_fixture = 50
V_fixture = 0.0
|   Time   V(typ)   V(min)   V(max)
0s        336.9mV    324.8mV    365.2mV
57ps      341.9mV    326mV      367.6mV
75ps      335.7mV    334.9mV    281.3mV
87ps      289.2mV    328.2mV    170.8mV
99ps      209.5mV    292.4mV    102.1mV
115ps     114.2mV    213mV      52.27mV
133ps     56.57mV    123.7mV    24.86mV
158ps     21.72mV    50.05mV    9.081mV
193ps     6.087mV    14.09mV    2.476mV
360ps     626.3uV    611.6uV    417.2uV
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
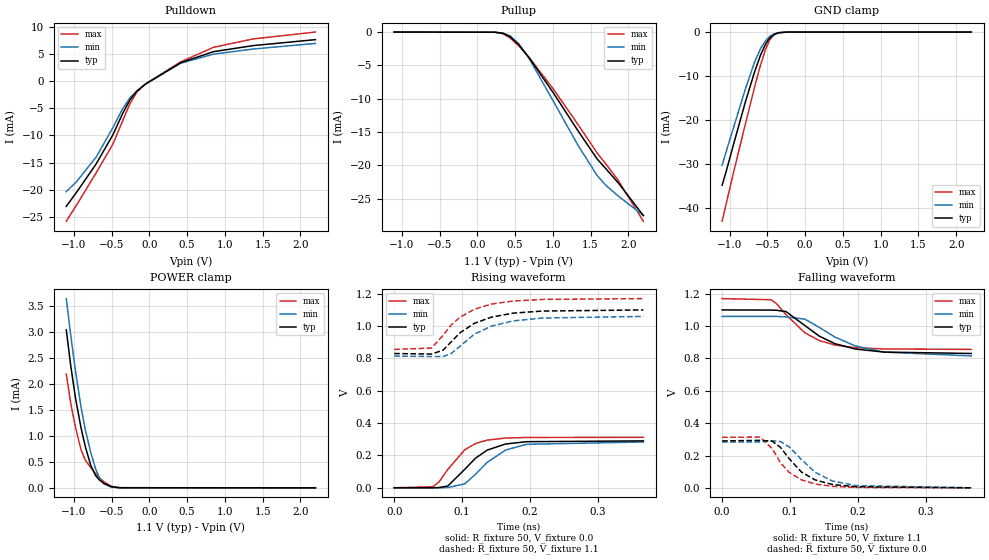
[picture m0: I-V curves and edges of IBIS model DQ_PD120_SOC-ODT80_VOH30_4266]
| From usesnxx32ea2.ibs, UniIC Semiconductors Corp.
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| DQ_PD120_SOC-ODT80_VOH30_4266
| (120 Ohm Pulldown, 80 Ohm System ODT Setting, VOH=VDDQ/3.0, 3200-4266Mbps)
[Model]   DQ_PD120_SOC-ODT80_VOH30_4266
Model_type   I/O
Vinl = 123.333mV
Vinh = 243.333mV
Vmeas = 183.333mV
Vref = 0.0mV
Cref = 0.0pF
Rref = 80.000Ohm
|   typ   min   max
|C_comp   0.834pF   0.784pF   0.884pF
C_comp_pullup   0.4170pF   0.3920pF   0.4420pF
C_comp_pulldown   0.4170pF   0.3920pF   0.4420pF
| Note: C_comp changes when the ODT circuit is enabled.
[Model Spec]
| Input threshold voltage corners
Vinl   0.1233V   0.1167V   0.1350V
Vinh   0.2433V   0.2367V   0.2550V
| Measurement voltage corners
Vmeas   0.1833V   0.1767V   0.1950V
| Timing spec test load voltage corners
Vref   0.0000V   0.0000V   0.0000V
| Dynamic Overshoot Parameters from LPDDR4 Specification
D_overshoot_ampl_h   0.30   NA   NA
D_overshoot_ampl_l   0.30   NA   NA
D_overshoot_area_h   0.1n   NA   NA
D_overshoot_area_l   0.1n   NA   NA
[Voltage Range]   1.1000V   1.0600V   1.1700V
[Pullup Reference]   1.1000V   1.0600V   1.1700V
| Junction Temperature (Ambient temp is 35C typ 95C min -40C max)
[Temperature Range]   50.0   110.0   -40.0
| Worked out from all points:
|   slope of the pulldown table from 0 to 0.165 V, typ, clamps not added: 110 ohm
|   slope of the pullup table from 0 to 0.165 V, typ, clamps not added: 26.1 kohm
|   GND clamp passes 1 mA (typ) near -0.45 V on its own axis
|   POWER clamp passes 1 mA (typ) near -0.88 V on its own axis
|   rising waveform, R_fixture 50, V_fixture 0.0: 20-80 % time 43.8ps typ, 47.1ps min, 37.9ps max; typ from 0 V to 0.29 V
|   falling waveform, R_fixture 50, V_fixture 1.1: 20-80 % time 61.1ps typ, 70.7ps min, 51.8ps max; typ from 1.1 V to 0.831 V
|   rising waveform, R_fixture 50, V_fixture 1.1: 20-80 % time 54.9ps typ, 57.9ps min, 52ps max; typ from 0.83 V to 1.1 V
|   falling waveform, R_fixture 50, V_fixture 0.0: 20-80 % time 42.2ps typ, 48ps min, 37.6ps max; typ from 0.29 V to 0.001 V
[Pulldown]
|   Voltage   I(typ)   I(min)   I(max)
-1.1V     -23.08mA   -20.37mA   -25.84mA
-961.4mV  -20.45mA   -18.49mA   -22.79mA
-704mV    -15.25mA   -13.98mA   -16.89mA
-482.9mV  -9.894mA   -8.579mA   -11.62mA
-350.9mV  -5.886mA   -5.015mA   -7.226mA
-258.5mV  -3.486mA   -3.105mA   -4.197mA
-166.1mV  -1.858mA   -1.778mA   -2.007mA
-53.9mV   -552uA     -545.8uA   -543.2uA
414.7mV   3.406mA    3.314mA    3.565mA
850.3mV   5.452mA    4.992mA    6.255mA
1.378V    6.574mA    5.941mA    7.804mA
2.2V      7.669mA    6.972mA    9.07mA
[GND Clamp]
|   Voltage   I(typ)   I(min)   I(max)
-1.1V     -34.74mA   -30.21mA   -42.91mA
-1.047V   -31.66mA   -27.15mA   -39.02mA
-944.9mV  -25.23mA   -21.44mA   -31.55mA
-789.8mV  -15.72mA   -12.78mA   -20.72mA
-667.7mV  -8.907mA   -6.722mA   -12.29mA
-591.8mV  -5.255mA   -3.789mA   -7.494mA
-522.5mV  -2.669mA   -1.902mA   -3.811mA
-469.7mV  -1.36mA    -985.5uA   -1.788mA
-413.6mV  -564.1uA   -419.1uA   -621.8uA
-354.2mV  -178.4uA   -135.9uA   -159.1uA
-245.3mV  -11.03uA   -10.69uA   -6.33uA
2.2V      0A         0A         0A
[Pullup]
|   Voltage   I(typ)   I(min)   I(max)
-1.1V     3.138uA    4.837uA    1.415uA
233.2mV   -24.21uA   -24.35uA   -25.32uA
338.8mV   -180.2uA   -149.4uA   -248.5uA
434.5mV   -693.7uA   -567.4uA   -877.6uA
550mV     -1.906mA   -1.752mA   -2.074mA
685.3mV   -3.826mA   -3.931mA   -3.792mA
1.009V    -9.139mA   -10.4mA    -8.564mA
1.332V    -14.77mA   -16.94mA   -13.83mA
1.586V    -19.01mA   -21.49mA   -18.12mA
1.695V    -20.39mA   -22.9mA    -19.65mA
1.87V     -22.66mA   -24.62mA   -22.29mA
2.2V      -27.52mA   -27.51mA   -28.38mA
[POWER Clamp]
|   Voltage   I(typ)   I(min)   I(max)
-1.1V     3.033mA    3.633mA    2.184mA
-1.041V   2.345mA    2.929mA    1.625mA
-977.9mV  1.723mA    2.241mA    1.16mA
-905.3mV  1.155mA    1.554mA    732.1uA
-849.2mV  798.9uA    1.125mA    535.4uA
-776.6mV  434uA      683.2uA    390.2uA
-713.9mV  239.2uA    373uA      278.6uA
-657.8mV  146.8uA    178.8uA    190.6uA
-598.4mV  83.65uA    71.96uA    113uA
-502.7mV  22.53uA    13.95uA    29.29uA
-397.1mV  2.387uA    1.588uA    2.117uA
2.2V      0A         0A         0A
[Ramp]
|   typ   min   max
| 20% - 80%
dV/dt_r   173.82m/43.80p   169.77m/47.06p   187.24m/37.94p
dV/dt_f   161.58m/61.05p   146.49m/70.59p   188.39m/51.75p
| 25% - 75%
|dV/dt_r   144.85m/34.89p   141.48m/37.52p   156.04m/30.18p
|dV/dt_f   134.65m/48.57p   122.07m/56.21p   156.99m/41.03p
R_load = 50
[Rising Waveform]
R_fixture = 50
V_fixture = 0.0
|   Time   V(typ)   V(min)   V(max)
0s        468.2uV    407.7uV    340uV
57ps      438.1uV    109.9uV    6.67mV
66ps      2.011mV    -52.01uV   36.58mV
79ps      11.22mV    1.623mV    114mV
104ps     114.7mV    24.53mV    235.7mV
120ps     184.4mV    84.97mV    274.3mV
137ps     233.2mV    157.8mV    295.1mV
164ps     271.1mV    233.5mV    307.7mV
195ps     285.3mV    269.1mV    311.4mV
367ps     290.2mV    283.4mV    312.4mV
[Falling Waveform]
R_fixture   = 50
V_fixture   = 1.1
V_fixture_min = 1.06
V_fixture_max = 1.17
|   Time   V(typ)   V(min)   V(max)
0s        1.1V       1.06V      1.17V
72ps      1.099V     1.06V      1.163V
80ps      1.098V     1.06V      1.139V
94ps      1.09V      1.057V     1.071V
122ps     1.003V     1.043V     958.2mV
143ps     938.3mV    992.3mV    910.8mV
166ps     891.6mV    932.6mV    883.1mV
196ps     858.5mV    877.9mV    866.7mV
238ps     839.6mV    839.2mV    858.9mV
367ps     830.7mV    815.8mV    856mV
[Rising Waveform]
R_fixture   = 50
V_fixture   = 1.1
V_fixture_min = 1.06
V_fixture_max = 1.17
|   Time   V(typ)   V(min)   V(max)
0s        830.4mV    814.6mV    855.9mV
55ps      827.1mV    811.9mV    864.3mV
72ps      851.2mV    811.6mV    943.3mV
84ps      902.8mV    830.6mV    1.007V
97ps      959mV      875.8mV    1.055V
118ps     1.017V     949.8mV    1.104V
143ps     1.055V     999.6mV    1.136V
175ps     1.08V      1.032V     1.155V
218ps     1.093V     1.05V      1.165V
367ps     1.1V       1.06V      1.17V
[Falling Waveform]
R_fixture = 50
V_fixture = 0.0
|   Time   V(typ)   V(min)   V(max)
0s        290.3mV    283.5mV    312.5mV
56ps      293.9mV    284mV      314.1mV
74ps      288.5mV    291.5mV    241.5mV
86ps      250.3mV    286.3mV    155.1mV
99ps      179.5mV    252.9mV    95.51mV
117ps     97.34mV    174.6mV    49.52mV
137ps     49.29mV    96.51mV    23.96mV
162ps     21.36mV    43.26mV    9.848mV
197ps     6.887mV    14.4mV     3.043mV
367ps     579.5uV    590.2uV    375uV
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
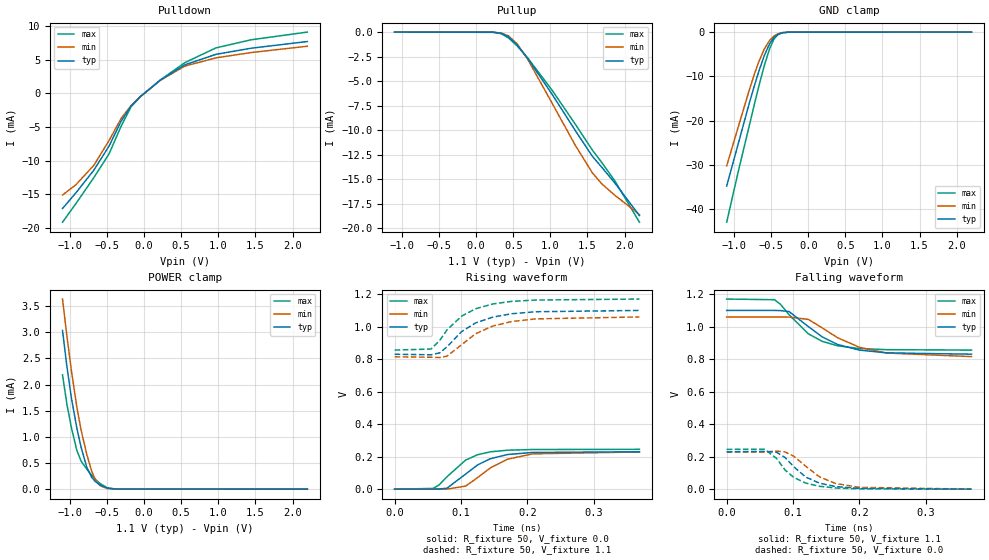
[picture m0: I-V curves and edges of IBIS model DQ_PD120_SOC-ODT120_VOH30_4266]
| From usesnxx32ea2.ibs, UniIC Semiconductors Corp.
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| DQ_PD120_SOC-ODT120_VOH30_4266
| (120 Ohm Pulldown, 120 Ohm System ODT Setting, VOH=VDDQ/3.0, 3200-4266Mbps)
[Model]   DQ_PD120_SOC-ODT120_VOH30_4266
Model_type   I/O
Vinl = 123.333mV
Vinh = 243.333mV
Vmeas = 183.333mV
Vref = 0.0mV
Cref = 0.0pF
Rref = 120.000Ohm
|   typ   min   max
|C_comp   0.834pF   0.784pF   0.884pF
C_comp_pullup   0.4170pF   0.3920pF   0.4420pF
C_comp_pulldown   0.4170pF   0.3920pF   0.4420pF
| Note: C_comp changes when the ODT circuit is enabled.
[Model Spec]
| Input threshold voltage corners
Vinl   0.1233V   0.1167V   0.1350V
Vinh   0.2433V   0.2367V   0.2550V
| Measurement voltage corners
Vmeas   0.1833V   0.1767V   0.1950V
| Timing spec test load voltage corners
Vref   0.0000V   0.0000V   0.0000V
| Dynamic Overshoot Parameters from LPDDR4 Specification
D_overshoot_ampl_h   0.30   NA   NA
D_overshoot_ampl_l   0.30   NA   NA
D_overshoot_area_h   0.1n   NA   NA
D_overshoot_area_l   0.1n   NA   NA
[Voltage Range]   1.1000V   1.0600V   1.1700V
[Pullup Reference]   1.1000V   1.0600V   1.1700V
| Junction Temperature (Ambient temp is 35C typ 95C min -40C max)
[Temperature Range]   50.0   110.0   -40.0
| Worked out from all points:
|   slope of the pulldown table from 0 to 0.165 V, typ, clamps not added: 110 ohm
|   slope of the pullup table from 0 to 0.165 V, typ, clamps not added: 39.1 kohm
|   GND clamp passes 1 mA (typ) near -0.45 V on its own axis
|   POWER clamp passes 1 mA (typ) near -0.88 V on its own axis
|   rising waveform, R_fixture 50, V_fixture 0.0: 20-80 % time 47.7ps typ, 52.1ps min, 42.1ps max; typ from 0 V to 0.23 V
|   falling waveform, R_fixture 50, V_fixture 1.1: 20-80 % time 60.7ps typ, 70ps min, 51.5ps max; typ from 1.1 V to 0.831 V
|   rising waveform, R_fixture 50, V_fixture 1.1: 20-80 % time 55.3ps typ, 58.9ps min, 52ps max; typ from 0.83 V to 1.1 V
|   falling waveform, R_fixture 50, V_fixture 0.0: 20-80 % time 42.3ps typ, 48.2ps min, 37.8ps max; typ from 0.23 V to 0 V
[Pulldown]
|   Voltage   I(typ)   I(min)   I(max)
-1.1V     -17.1mA    -15.1mA    -19.13mA
-921.8mV  -14.81mA   -13.6mA    -16.41mA
-677.6mV  -11.41mA   -10.69mA   -12.51mA
-473mV    -7.847mA   -7.025mA   -9.001mA
-311.3mV  -4.182mA   -3.76mA    -4.912mA
-176mV    -1.893mA   -1.835mA   -2.012mA
-47.3mV   -472.8uA   -469.9uA   -464.1uA
220mV     1.955mA    1.932mA    1.978mA
550mV     4.219mA    4.027mA    4.545mA
969.1mV   5.772mA    5.249mA    6.73mA
1.444V    6.68mA     6.037mA    7.933mA
2.2V      7.669mA    6.972mA    9.07mA
[GND Clamp]
|   Voltage   I(typ)   I(min)   I(max)
-1.1V     -34.74mA   -30.21mA   -42.91mA
-944.9mV  -25.23mA   -21.44mA   -31.55mA
-796.4mV  -16.11mA   -13.14mA   -21.19mA
-723.8mV  -11.93mA   -9.349mA   -16.1mA
-664.4mV  -8.736mA   -6.578mA   -12.07mA
-591.8mV  -5.257mA   -3.789mA   -7.492mA
-522.5mV  -2.667mA   -1.903mA   -3.81mA
-466.4mV  -1.296mA   -943.1uA   -1.691mA
-413.6mV  -565.6uA   -417.8uA   -621.4uA
-354.2mV  -178.2uA   -134.8uA   -160.3uA
-265.1mV  -19.2uA    -16.86uA   -12.31uA
2.2V      0A         0A         0A
[Pullup]
|   Voltage   I(typ)   I(min)   I(max)
-1.1V     2.092uA    3.224uA    943.3nA
233.2mV   -16.17uA   -16.34uA   -16.87uA
335.5mV   -114.1uA   -94.54uA   -157.1uA
434.5mV   -466.6uA   -381.3uA   -589.3uA
550mV     -1.285mA   -1.182mA   -1.396mA
691.9mV   -2.653mA   -2.746mA   -2.616mA
1.019V    -6.297mA   -7.197mA   -5.887mA
1.335V    -10.03mA   -11.54mA   -9.384mA
1.566V    -12.67mA   -14.36mA   -12.04mA
1.695V    -13.81mA   -15.5mA    -13.33mA
1.87V     -15.4mA    -16.65mA   -15.19mA
2.2V      -18.72mA   -18.61mA   -19.39mA
[POWER Clamp]
|   Voltage   I(typ)   I(min)   I(max)
-1.1V     3.033mA    3.633mA    2.184mA
-1.041V   2.345mA    2.929mA    1.625mA
-977.9mV  1.723mA    2.241mA    1.16mA
-905.3mV  1.155mA    1.554mA    732.4uA
-849.2mV  799uA      1.126mA    535.4uA
-773.3mV  420.7uA    665.2uA    384.1uA
-707.3mV  225.5uA    345.3uA    267.6uA
-654.5mV  142.6uA    170.5uA    185.9uA
-591.8mV  77.99uA    64.79uA    105.5uA
-496.1mV  20.11uA    12.32uA    25.71uA
-380.6mV  1.622uA    1.133uA    1.341uA
2.2V      0A         0A         0A
[Ramp]
|   typ   min   max
| 20% - 80%
dV/dt_r   137.72m/47.66p   137.27m/52.09p   146.93m/42.07p
dV/dt_f   161.58m/60.69p   146.49m/70.02p   188.39m/51.46p
| 25% - 75%
|dV/dt_r   114.76m/37.96p   114.39m/41.54p   122.44m/33.46p
|dV/dt_f   134.65m/48.32p   122.07m/55.84p   156.99m/40.86p
R_load = 50
[Rising Waveform]
R_fixture = 50
V_fixture = 0.0
|   Time   V(typ)   V(min)   V(max)
0s        309.9uV    266.2uV    226.7uV
58ps      226.3uV    159.2uV    4.303mV
67ps      853.7uV    -58.74uV   25.92mV
79ps      6.144mV    416.3uV    76.57mV
107ps     92.73mV    18.51mV    178.8mV
125ps     148.9mV    70.84mV    211.8mV
144ps     186.8mV    130mV      229.6mV
170ps     213mV      184.1mV    239.7mV
208ps     226mV      217.3mV    244mV
369ps     229.8mV    229.1mV    245.1mV
[Falling Waveform]
R_fixture   = 50
V_fixture   = 1.1
V_fixture_min = 1.06
V_fixture_max = 1.17
|   Time   V(typ)   V(min)   V(max)
0s        1.1V       1.06V      1.17V
72ps      1.1V       1.06V      1.166V
81ps      1.099V     1.06V      1.138V
94ps      1.093V     1.059V     1.074V
123ps     1.001V     1.045V     956.4mV
144ps     937.2mV    992.5mV    909.8mV
167ps     890.8mV    932.3mV    882.6mV
200ps     856mV      873.4mV    865.5mV
241ps     839mV      837.9mV    858.6mV
369ps     830.7mV    815.8mV    856mV
[Rising Waveform]
R_fixture   = 50
V_fixture   = 1.1
V_fixture_min = 1.06
V_fixture_max = 1.17
|   Time   V(typ)   V(min)   V(max)
0s        830.4mV    814.6mV    855.9mV
55ps      827.1mV    812.1mV    862.6mV
68ps      839mV      810mV      915.2mV
79ps      876.2mV    818.8mV    980.6mV
101ps     969.8mV    888.7mV    1.065V
122ps     1.023V     956.6mV    1.11V
148ps     1.059V     1.004V     1.14V
177ps     1.08V      1.032V     1.156V
213ps     1.092V     1.048V     1.164V
369ps     1.1V       1.06V      1.17V
[Falling Waveform]
R_fixture = 50
V_fixture = 0.0
|   Time   V(typ)   V(min)   V(max)
0s        229.9mV    229.2mV    245.2mV
57ps      232.4mV    229.4mV    245.7mV
75ps      227.5mV    234.4mV    190.2mV
88ps      195.2mV    229.3mV    117.8mV
101ps     138.2mV    203.3mV    72.77mV
119ps     75.15mV    141.7mV    37.83mV
140ps     36.98mV    75.73mV    17.74mV
164ps     16.6mV     35.2mV     7.607mV
200ps     5.201mV    11.38mV    2.233mV
369ps     413.7uV    440.9uV    260.1uV
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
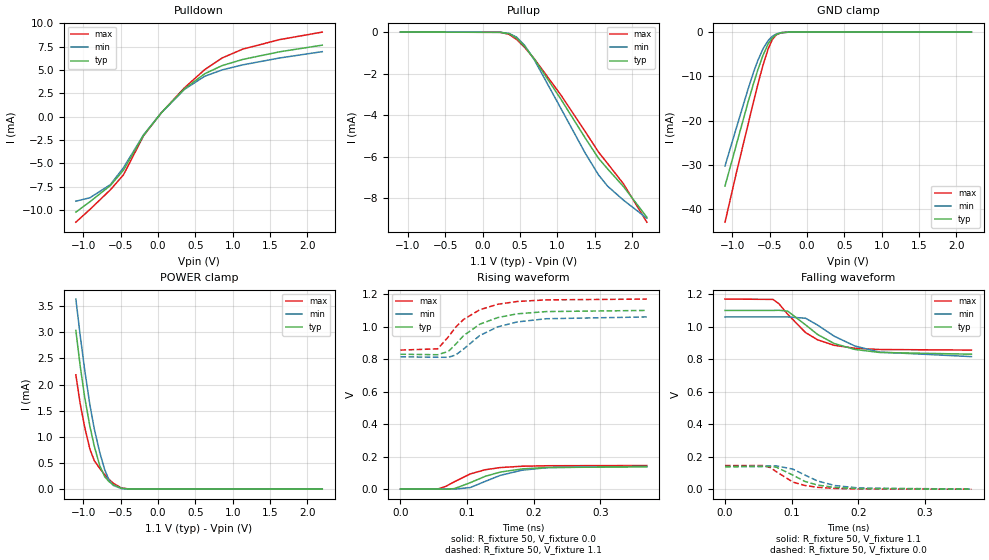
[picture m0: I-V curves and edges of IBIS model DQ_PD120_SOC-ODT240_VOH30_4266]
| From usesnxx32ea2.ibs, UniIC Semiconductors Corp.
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| DQ_PD120_SOC-ODT240_VOH30_4266
| (120 Ohm Pulldown, 240 Ohm System ODT Setting, VOH=VDDQ/3.0, 3200-4266Mbps)
[Model]   DQ_PD120_SOC-ODT240_VOH30_4266
Model_type   I/O
Vinl = 123.333mV
Vinh = 243.333mV
Vmeas = 183.333mV
Vref = 0.0mV
Cref = 0.0pF
Rref = 240.000Ohm
|   typ   min   max
|C_comp   0.834pF   0.784pF   0.884pF
C_comp_pullup   0.4170pF   0.3920pF   0.4420pF
C_comp_pulldown   0.4170pF   0.3920pF   0.4420pF
| Note: C_comp changes when the ODT circuit is enabled.
[Model Spec]
| Input threshold voltage corners
Vinl   0.1233V   0.1167V   0.1350V
Vinh   0.2433V   0.2367V   0.2550V
| Measurement voltage corners
Vmeas   0.1833V   0.1767V   0.1950V
| Timing spec test load voltage corners
Vref   0.0000V   0.0000V   0.0000V
| Dynamic Overshoot Parameters from LPDDR4 Specification
D_overshoot_ampl_h   0.30   NA   NA
D_overshoot_ampl_l   0.30   NA   NA
D_overshoot_area_h   0.1n   NA   NA
D_overshoot_area_l   0.1n   NA   NA
[Voltage Range]   1.1000V   1.0600V   1.1700V
[Pullup Reference]   1.1000V   1.0600V   1.1700V
| Junction Temperature (Ambient temp is 35C typ 95C min -40C max)
[Temperature Range]   50.0   110.0   -40.0
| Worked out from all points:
|   slope of the pulldown table from 0 to 0.165 V, typ, clamps not added: 110 ohm
|   slope of the pullup table from 0 to 0.165 V, typ, clamps not added: 79 kohm
|   GND clamp passes 1 mA (typ) near -0.45 V on its own axis
|   POWER clamp passes 1 mA (typ) near -0.88 V on its own axis
|   rising waveform, R_fixture 50, V_fixture 0.0: 20-80 % time 57.1ps typ, 59.6ps min, 49.5ps max; typ from 0 V to 0.137 V
|   falling waveform, R_fixture 50, V_fixture 1.1: 20-80 % time 60.4ps typ, 69.4ps min, 51.2ps max; typ from 1.1 V to 0.831 V
|   rising waveform, R_fixture 50, V_fixture 1.1: 20-80 % time 56.5ps typ, 60.7ps min, 52.1ps max; typ from 0.83 V to 1.1 V
|   falling waveform, R_fixture 50, V_fixture 0.0: 20-80 % time 43.2ps typ, 49.6ps min, 38.7ps max; typ from 0.137 V to 0 V
[Pulldown]
|   Voltage   I(typ)   I(min)   I(max)
-1.1V     -10.24mA   -9.066mA   -11.32mA
-911.9mV  -9.128mA   -8.702mA   -9.957mA
-638mV    -7.389mA   -7.297mA   -7.849mA
-463.1mV  -5.75mA    -5.483mA   -6.247mA
-192.5mV  -1.976mA   -1.949mA   -2.04mA
45.1mV    420.7uA    419.5uA    417.6uA
355.3mV   2.997mA    2.933mA    3.1mA
625.9mV   4.603mA    4.336mA    5.043mA
860.2mV   5.481mA    5.016mA    6.299mA
1.137V    6.142mA    5.559mA    7.248mA
1.629V    6.957mA    6.293mA    8.262mA
2.2V      7.669mA    6.972mA    9.07mA
[GND Clamp]
|   Voltage   I(typ)   I(min)   I(max)
-1.1V     -34.74mA   -30.21mA   -42.91mA
-948.2mV  -25.43mA   -21.63mA   -31.79mA
-796.4mV  -16.11mA   -13.14mA   -21.19mA
-720.5mV  -11.75mA   -9.185mA   -15.87mA
-664.4mV  -8.736mA   -6.578mA   -12.07mA
-591.8mV  -5.255mA   -3.789mA   -7.492mA
-522.5mV  -2.665mA   -1.905mA   -3.811mA
-466.4mV  -1.297mA   -944.5uA   -1.691mA
-413.6mV  -566.2uA   -418.1uA   -620.7uA
-347.6mV  -154.9uA   -118uA     -135.5uA
-242mV    -10.28uA   -9.19uA    -5.672uA
2.2V      0A         0A         0A
[Pullup]
|   Voltage   I(typ)   I(min)   I(max)
-1.1V     1.046uA    1.612uA    471.2nA
236.5mV   -8.718uA   -8.625uA   -9.172uA
355.3mV   -78.49uA   -64.06uA   -108.1uA
457.6mV   -294.4uA   -245.6uA   -359.9uA
566.5mV   -699.5uA   -652.6uA   -750.4uA
695.2mV   -1.311mA   -1.351mA   -1.297mA
1.052V    -3.249mA   -3.698mA   -3.047mA
1.375V    -5.105mA   -5.833mA   -4.795mA
1.553V    -6.084mA   -6.882mA   -5.782mA
1.675V    -6.593mA   -7.426mA   -6.335mA
1.887V    -7.444mA   -8.098mA   -7.311mA
2.2V      -8.92mA    -8.97mA    -9.16mA
[POWER Clamp]
|   Voltage   I(typ)   I(min)   I(max)
-1.1V     3.033mA    3.633mA    2.184mA
-1.041V   2.345mA    2.929mA    1.625mA
-981.2mV  1.753mA    2.275mA    1.183mA
-911.9mV  1.2mA      1.611mA    764.5uA
-852.5mV  818.2uA    1.148mA    543.7uA
-779.9mV  447.8uA    701.4uA    396.3uA
-713.9mV  239.2uA    373.1uA    278.6uA
-654.5mV  142.6uA    170.4uA    185.9uA
-598.4mV  83.66uA    71.95uA    113uA
-489.5mV  17.76uA    10.87uA    22.47uA
-374mV    1.392uA    1.001uA    1.127uA
2.2V      0A         0A         0A
[Ramp]
|   typ   min   max
| 20% - 80%
dV/dt_r   82.32m/57.11p   84.05m/59.55p   87.11m/49.55p
dV/dt_f   161.59m/60.34p   146.48m/69.52p   188.39m/51.18p
| 25% - 75%
|dV/dt_r   68.60m/45.49p   70.04m/47.42p   72.59m/39.29p
|dV/dt_f   134.65m/48.01p   122.06m/55.37p   156.99m/40.66p
R_load = 50
[Rising Waveform]
R_fixture = 50
V_fixture = 0.0
|   Time   V(typ)   V(min)   V(max)
0s        149.4uV    121uV      112.3uV
57ps      90.13uV    184.4uV    2.263mV
68ps      -135.6uV   -21.87uV   16.9mV
81ps      3.256mV    -45.93uV   45.59mV
105ps     40.06mV    9.983mV    93.87mV
127ps     78.49mV    47.36mV    119.2mV
150ps     105.2mV    84.9mV     132.9mV
183ps     124.8mV    117mV      141mV
222ps     133.4mV    132.7mV    144.1mV
370ps     137.3mV    140.2mV    145.3mV
[Falling Waveform]
R_fixture   = 50
V_fixture   = 1.1
V_fixture_min = 1.06
V_fixture_max = 1.17
|   Time   V(typ)   V(min)   V(max)
0s        1.1V       1.06V      1.17V
72ps      1.1V       1.06V      1.168V
81ps      1.101V     1.06V      1.141V
94ps      1.096V     1.06V      1.077V
121ps     1.011V     1.052V     963.6mV
139ps     952mV      1.01V      919.1mV
164ps     896.4mV    941.3mV    885.4mV
195ps     859.9mV    881.2mV    867.2mV
232ps     841.4mV    843.7mV    859.5mV
370ps     830.7mV    815.9mV    856mV
[Rising Waveform]
R_fixture   = 50
V_fixture   = 1.1
V_fixture_min = 1.06
V_fixture_max = 1.17
|   Time   V(typ)   V(min)   V(max)
0s        830.4mV    814.6mV    855.9mV
56ps      827.3mV    811.9mV    863.6mV
72ps      848mV      811.5mV    937.5mV
83ps      892.5mV    825.9mV    997.4mV
95ps      945.6mV    862.8mV    1.045V
119ps     1.015V     945.4mV    1.104V
146ps     1.056V     998.7mV    1.138V
175ps     1.079V     1.029V     1.155V
219ps     1.093V     1.049V     1.165V
370ps     1.1V       1.06V      1.17V
[Falling Waveform]
R_fixture = 50
V_fixture = 0.0
|   Time   V(typ)   V(min)   V(max)
0s        137.5mV    140.4mV    145.3mV
58ps      139.2mV    141.1mV    145.3mV
68ps      139.4mV    142.8mV    133.3mV
77ps      135.5mV    143.6mV    107.7mV
102ps     86.43mV    123.3mV    43.64mV
120ps     47.77mV    86.95mV    22.86mV
139ps     25.34mV    50.33mV    11.55mV
165ps     10.71mV    22.44mV    4.606mV
201ps     3.368mV    7.364mV    1.351mV
370ps     231.2uV    263.9uV    135.4uV
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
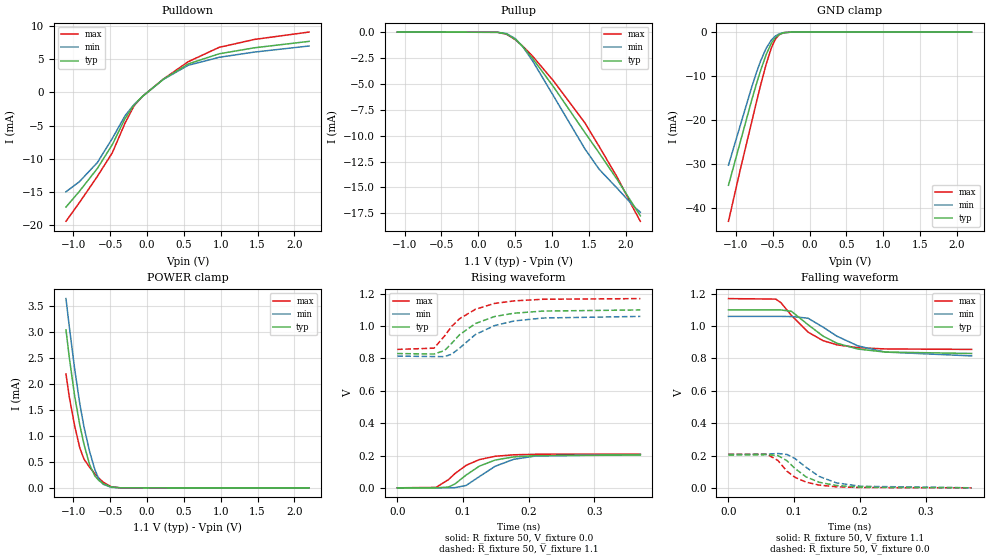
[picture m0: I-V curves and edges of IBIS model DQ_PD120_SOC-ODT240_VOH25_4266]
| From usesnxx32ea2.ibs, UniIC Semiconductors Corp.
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| DQ_PD120_SOC-ODT240_VOH25_4266
| (120 Ohm Pulldown, 240 Ohm System ODT Setting, VOH=VDDQ/2.5, 3200-4266Mbps)
[Model]   DQ_PD120_SOC-ODT240_VOH25_4266
Model_type   I/O
Vinl = 160.000mV
Vinh = 280.000mV
Vmeas = 220.000mV
Vref = 0.0mV
Cref = 0.0pF
Rref = 240.000Ohm
|   typ   min   max
|C_comp   0.834pF   0.784pF   0.884pF
C_comp_pullup   0.4170pF   0.3920pF   0.4420pF
C_comp_pulldown   0.4170pF   0.3920pF   0.4420pF
| Note: C_comp changes when the ODT circuit is enabled.
[Model Spec]
| Input threshold voltage corners
Vinl   0.1600V   0.1520V   0.1740V
Vinh   0.2800V   0.2720V   0.2940V
| Measurement voltage corners
Vmeas   0.2200V   0.2120V   0.2340V
| Timing spec test load voltage corners
Vref   0.0000V   0.0000V   0.0000V
| Dynamic Overshoot Parameters from LPDDR4 Specification
D_overshoot_ampl_h   0.30   NA   NA
D_overshoot_ampl_l   0.30   NA   NA
D_overshoot_area_h   0.1n   NA   NA
D_overshoot_area_l   0.1n   NA   NA
[Voltage Range]   1.1000V   1.0600V   1.1700V
[Pullup Reference]   1.1000V   1.0600V   1.1700V
| Junction Temperature (Ambient temp is 35C typ 95C min -40C max)
[Temperature Range]   50.0   110.0   -40.0
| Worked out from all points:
|   slope of the pulldown table from 0 to 0.165 V, typ, clamps not added: 110 ohm
|   slope of the pullup table from 0 to 0.165 V, typ, clamps not added: 52.6 kohm
|   GND clamp passes 1 mA (typ) near -0.45 V on its own axis
|   POWER clamp passes 1 mA (typ) near -0.88 V on its own axis
|   rising waveform, R_fixture 50, V_fixture 0.0: 20-80 % time 47.7ps typ, 51.9ps min, 43.9ps max; typ from 0 V to 0.203 V
|   falling waveform, R_fixture 50, V_fixture 1.1: 20-80 % time 60.6ps typ, 70.1ps min, 51.4ps max; typ from 1.1 V to 0.831 V
|   rising waveform, R_fixture 50, V_fixture 1.1: 20-80 % time 56.1ps typ, 59.1ps min, 51.7ps max; typ from 0.83 V to 1.1 V
|   falling waveform, R_fixture 50, V_fixture 0.0: 20-80 % time 42.6ps typ, 48.4ps min, 37.8ps max; typ from 0.203 V to 0 V
[Pulldown]
|   Voltage   I(typ)   I(min)   I(max)
-1.1V     -17.26mA   -14.96mA   -19.4mA
-918.5mV  -14.9mA    -13.45mA   -16.6mA
-674.3mV  -11.46mA   -10.57mA   -12.65mA
-469.7mV  -7.838mA   -6.913mA   -9.064mA
-298.1mV  -3.934mA   -3.521mA   -4.632mA
-176mV    -1.9mA     -1.832mA   -2.026mA
-57.2mV   -573uA     -567.7uA   -564.7uA
223.3mV   1.982mA    1.959mA    2.006mA
559.9mV   4.272mA    4.07mA     4.612mA
979mV     5.796mA    5.269mA    6.765mA
1.458V    6.701mA    6.056mA    7.958mA
2.2V      7.669mA    6.972mA    9.07mA
[GND Clamp]
|   Voltage   I(typ)   I(min)   I(max)
-1.1V     -34.75mA   -30.2mA    -42.92mA
-941.6mV  -25.02mA   -21.25mA   -31.33mA
-786.5mV  -15.53mA   -12.6mA    -20.5mA
-723.8mV  -11.94mA   -9.346mA   -16.11mA
-664.4mV  -8.74mA    -6.576mA   -12.08mA
-588.5mV  -5.114mA   -3.68mA    -7.305mA
-519.2mV  -2.565mA   -1.833mA   -3.663mA
-466.4mV  -1.294mA   -941.8uA   -1.691mA
-413.6mV  -563.1uA   -417.1uA   -621.1uA
-350.9mV  -166.1uA   -126.6uA   -147.6uA
-238.7mV  -9.056uA   -8.494uA   -5.049uA
2.2V      0A         0A         0A
[Pullup]
|   Voltage   I(typ)   I(min)   I(max)
-1.1V     1.369uA    2.477uA    453.9nA
262.9mV   -21.59uA   -21.11uA   -22.16uA
385mV     -183.8uA   -152.5uA   -220.4uA
503.8mV   -707uA     -636.9uA   -738.7uA
609.4mV   -1.453mA   -1.458mA   -1.392mA
738.1mV   -2.555mA   -2.79mA    -2.331mA
1.022V    -5.289mA   -6.172mA   -4.721mA
1.448V    -9.706mA   -11.28mA   -8.764mA
1.642V    -11.68mA   -13.25mA   -11.05mA
1.89V     -14.28mA   -15.11mA   -14.06mA
2.114V    -16.79mA   -16.85mA   -17.14mA
2.2V      -17.73mA   -17.38mA   -18.26mA
[POWER Clamp]
|   Voltage   I(typ)   I(min)   I(max)
-1.1V     3.033mA    3.633mA    2.184mA
-1.054V   2.491mA    3.082mA    1.736mA
-981.2mV  1.753mA    2.275mA    1.183mA
-911.9mV  1.201mA    1.61mA     764.6uA
-855.8mV  837.7uA    1.171mA    552.1uA
-779.9mV  447.8uA    701.5uA    396.3uA
-707.3mV  225.4uA    345.4uA    267.6uA
-651.2mV  138.6uA    162.3uA    181.2uA
-595.1mV  80.75uA    68.29uA    109.2uA
-486.2mV  16.69uA    10.22uA    20.94uA
-367.4mV  1.19uA     878nA      944.5nA
2.2V      0A         0A         0A
[Ramp]
|   typ   min   max
| 20% - 80%
dV/dt_r   121.46m/47.69p   123.76m/51.89p   125.27m/43.89p
dV/dt_f   161.60m/60.65p   146.48m/70.12p   188.39m/51.38p
| 25% - 75%
|dV/dt_r   101.22m/37.88p   103.13m/41.35p   104.39m/34.83p
|dV/dt_f   134.67m/48.16p   122.07m/55.68p   156.99m/40.75p
R_load = 50
[Rising Waveform]
R_fixture = 50
V_fixture = 0.0
|   Time   V(typ)   V(min)   V(max)
0s        321.6uV    257.2uV    238.4uV
59ps      232uV      159.8uV    2.748mV
78ps      4.922mV    205.4uV    51mV
88ps      24.46mV    1.227mV    88.72mV
105ps     79.63mV    15.23mV    139.6mV
125ps     134.4mV    69.62mV    174.9mV
149ps     171.9mV    133.5mV    195.1mV
177ps     191.3mV    176.2mV    204.3mV
211ps     199.5mV    197.3mV    207.7mV
370ps     202.8mV    206.5mV    209mV
[Falling Waveform]
R_fixture   = 50
V_fixture   = 1.1
V_fixture_min = 1.06
V_fixture_max = 1.17
|   Time   V(typ)   V(min)   V(max)
0s        1.1V       1.06V      1.17V
72ps      1.1V       1.06V      1.167V
80ps      1.1V       1.06V      1.144V
96ps      1.091V     1.059V     1.065V
121ps     1.009V     1.049V     963mV
144ps     937.9mV    993.4mV    910.1mV
165ps     894.3mV    937.7mV    884.4mV
197ps     858.2mV    877.8mV    866.6mV
238ps     839.7mV    839.7mV    858.9mV
370ps     830.7mV    815.9mV    856mV
[Rising Waveform]
R_fixture   = 50
V_fixture   = 1.1
V_fixture_min = 1.06
V_fixture_max = 1.17
|   Time   V(typ)   V(min)   V(max)
0s        830.4mV    814.6mV    855.9mV
56ps      827.3mV    811.8mV    863.6mV
72ps      848.8mV    811.3mV    938.7mV
83ps      894mV      826.4mV    998.6mV
95ps      947.2mV    864.4mV    1.046V
119ps     1.016V     948mV      1.104V
148ps     1.059V     1.003V     1.14V
178ps     1.08V      1.032V     1.156V
222ps     1.093V     1.05V      1.166V
370ps     1.1V       1.06V      1.17V
[Falling Waveform]
R_fixture = 50
V_fixture = 0.0
|   Time   V(typ)   V(min)   V(max)
0s        202.9mV    206.6mV    209.1mV
58ps      204.9mV    207.9mV    208.6mV
75ps      200.4mV    212.7mV    170.2mV
89ps      167.9mV    206.3mV    102.9mV
101ps     120.6mV    181.7mV    65.92mV
118ps     68.22mV    127.5mV    35.55mV
138ps     34.79mV    70.77mV    17.25mV
164ps     14.65mV    31.21mV    6.844mV
201ps     4.477mV    9.917mV    2.032mV
370ps     413.3uV    419.9uV    267uV
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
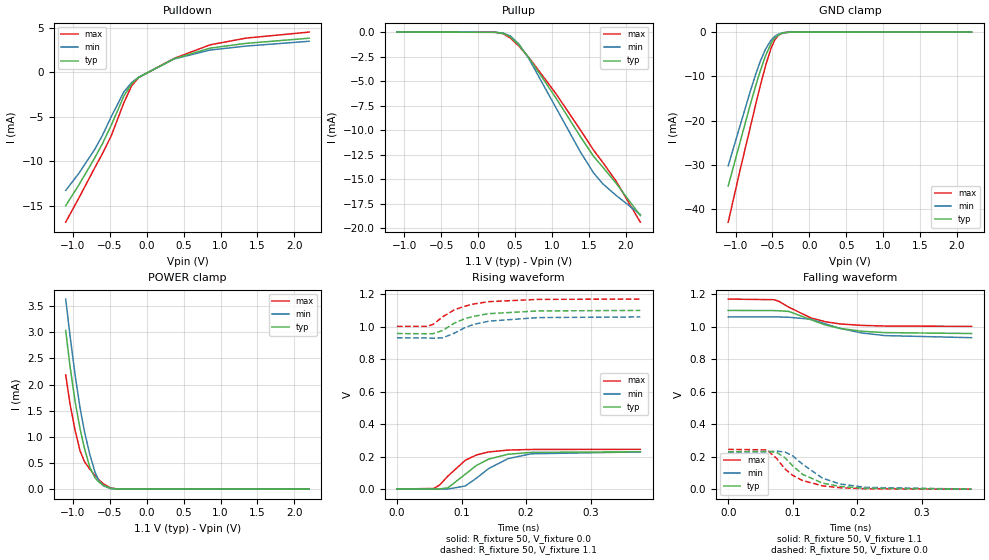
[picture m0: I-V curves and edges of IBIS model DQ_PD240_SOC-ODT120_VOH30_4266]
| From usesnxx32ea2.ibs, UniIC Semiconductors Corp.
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| DQ_PD240_SOC-ODT120_VOH30_4266
| (240 Ohm Pulldown, 120 Ohm System ODT Setting, VOH=VDDQ/3.0, 3200-4266Mbps)
[Model]   DQ_PD240_SOC-ODT120_VOH30_4266
Model_type   I/O
Vinl = 123.333mV
Vinh = 243.333mV
Vmeas = 183.333mV
Vref = 0.0mV
Cref = 0.0pF
Rref = 120.000Ohm
|   typ   min   max
|C_comp   0.834pF   0.784pF   0.884pF
C_comp_pullup   0.4170pF   0.3920pF   0.4420pF
C_comp_pulldown   0.4170pF   0.3920pF   0.4420pF
| Note: C_comp changes when the ODT circuit is enabled.
[Model Spec]
| Input threshold voltage corners
Vinl   0.1233V   0.1167V   0.1350V
Vinh   0.2433V   0.2367V   0.2550V
| Measurement voltage corners
Vmeas   0.1833V   0.1767V   0.1950V
| Timing spec test load voltage corners
Vref   0.0000V   0.0000V   0.0000V
| Dynamic Overshoot Parameters from LPDDR4 Specification
D_overshoot_ampl_h   0.30   NA   NA
D_overshoot_ampl_l   0.30   NA   NA
D_overshoot_area_h   0.1n   NA   NA
D_overshoot_area_l   0.1n   NA   NA
[Voltage Range]   1.1000V   1.0600V   1.1700V
[Pullup Reference]   1.1000V   1.0600V   1.1700V
| Junction Temperature (Ambient temp is 35C typ 95C min -40C max)
[Temperature Range]   50.0   110.0   -40.0
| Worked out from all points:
|   slope of the pulldown table from 0 to 0.165 V, typ, clamps not added: 225 ohm
|   slope of the pullup table from 0 to 0.165 V, typ, clamps not added: 39.1 kohm
|   GND clamp passes 1 mA (typ) near -0.45 V on its own axis
|   POWER clamp passes 1 mA (typ) near -0.88 V on its own axis
|   rising waveform, R_fixture 50, V_fixture 0.0: 20-80 % time 48.1ps typ, 52.7ps min, 42.2ps max; typ from 0 V to 0.23 V
|   falling waveform, R_fixture 50, V_fixture 1.1: 20-80 % time 66.5ps typ, 75.3ps min, 57.1ps max; typ from 1.1 V to 0.958 V
|   rising waveform, R_fixture 50, V_fixture 1.1: 20-80 % time 53.7ps typ, 54.6ps min, 51.9ps max; typ from 0.958 V to 1.1 V
|   falling waveform, R_fixture 50, V_fixture 0.0: 20-80 % time 48.3ps typ, 53.2ps min, 44ps max; typ from 0.23 V to 0.001 V
[Pulldown]
|   Voltage   I(typ)   I(min)   I(max)
-1.1V     -14.99mA   -13.28mA   -16.84mA
-921.8mV  -12.66mA   -11.36mA   -14.13mA
-704mV    -9.587mA   -8.633mA   -10.7mA
-601.7mV  -8.025mA   -7.092mA   -9.135mA
-482.9mV  -5.962mA   -5.005mA   -7.151mA
-311.3mV  -2.675mA   -2.207mA   -3.431mA
-205.7mV  -1.289mA   -1.165mA   -1.531mA
-110mV    -578.3uA   -561.2uA   -591uA
371.8mV   1.515mA    1.487mA    1.558mA
860.2mV   2.705mA    2.487mA    3.077mA
1.345V    3.236mA    2.93mA     3.825mA
2.2V      3.814mA    3.471mA    4.502mA
[GND Clamp]
|   Voltage   I(typ)   I(min)   I(max)
-1.1V     -34.74mA   -30.21mA   -42.91mA
-941.6mV  -25.02mA   -21.26mA   -31.32mA
-803mV    -16.5mA    -13.5mA    -21.65mA
-723.8mV  -11.93mA   -9.348mA   -16.1mA
-664.4mV  -8.736mA   -6.578mA   -12.07mA
-591.8mV  -5.256mA   -3.789mA   -7.493mA
-519.2mV  -2.564mA   -1.832mA   -3.66mA
-469.7mV  -1.357mA   -987.1uA   -1.787mA
-413.6mV  -564.7uA   -416.5uA   -622.2uA
-350.9mV  -165.9uA   -125.7uA   -147.8uA
-261.8mV  -17.79uA   -15.45uA   -11.01uA
2.2V      0A         0A         0A
[Pullup]
|   Voltage   I(typ)   I(min)   I(max)
-1.1V     2.092uA    3.224uA    943.3nA
233.2mV   -16.1uA    -16.27uA   -16.88uA
338.8mV   -120.5uA   -99.66uA   -166.1uA
437.8mV   -483.9uA   -396.1uA   -609uA
550mV     -1.285mA   -1.182mA   -1.396mA
688.6mV   -2.618mA   -2.704mA   -2.586mA
1.052V    -6.68mA    -7.657mA   -6.24mA
1.391V    -10.7mA    -12.27mA   -10.02mA
1.566V    -12.67mA   -14.36mA   -12.04mA
1.688V    -13.75mA   -15.45mA   -13.26mA
1.867V    -15.37mA   -16.63mA   -15.15mA
2.2V      -18.72mA   -18.61mA   -19.39mA
[POWER Clamp]
|   Voltage   I(typ)   I(min)   I(max)
-1.1V     3.033mA    3.633mA    2.184mA
-1.041V   2.345mA    2.929mA    1.625mA
-971.3mV  1.665mA    2.173mA    1.116mA
-905.3mV  1.155mA    1.553mA    732.1uA
-845.9mV  780uA      1.103mA    527.5uA
-773.3mV  420.7uA    665.2uA    384.1uA
-704mV    218.9uA    332uA      262.1uA
-651.2mV  138.6uA    162.3uA    181.2uA
-591.8mV  77.94uA    64.8uA     105.5uA
-496.1mV  20.09uA    12.52uA    25.73uA
-397.1mV  2.372uA    1.597uA    2.12uA
2.2V      0A         0A         0A
[Ramp]
|   typ   min   max
| 20% - 80%
dV/dt_r   137.67m/48.15p   137.23m/52.68p   146.90m/42.21p
dV/dt_f   85.14m/66.42p   76.64m/75.04p   100.76m/57.11p
| 25% - 75%
|dV/dt_r   114.73m/38.29p   114.36m/41.92p   122.42m/33.57p
|dV/dt_f   70.95m/52.90p   63.86m/59.80p   83.97m/45.37p
R_load = 50
[Rising Waveform]
R_fixture = 50
V_fixture = 0.0
|   Time   V(typ)   V(min)   V(max)
0s        378.2uV    331.4uV    274.3uV
57ps      18.95uV    17.73uV    4.015mV
66ps      1.096mV    -302uV     24.73mV
79ps      8.228mV    642.3uV    80.52mV
106ps     92.2mV     19.42mV    178mV
123ps     145.5mV    67.07mV    210mV
142ps     184.6mV    126.4mV    228.7mV
172ps     214.6mV    187.6mV    240.3mV
208ps     226.1mV    217.4mV    244mV
377ps     229.8mV    229.1mV    245.1mV
[Falling Waveform]
R_fixture   = 50
V_fixture   = 1.1
V_fixture_min = 1.06
V_fixture_max = 1.17
|   Time   V(typ)   V(min)   V(max)
0s        1.1V       1.06V      1.17V
71ps      1.099V     1.06V      1.166V
78ps      1.098V     1.06V      1.157V
94ps      1.094V     1.058V     1.12V
128ps     1.043V     1.046V     1.054V
150ps     1.011V     1.018V     1.031V
173ps     989.5mV    990.1mV    1.017V
207ps     971.8mV    961.3mV    1.008V
243ps     963.5mV    945.2mV    1.004V
377ps     958.1mV    932.3mV    1.002V
[Rising Waveform]
R_fixture   = 50
V_fixture   = 1.1
V_fixture_min = 1.06
V_fixture_max = 1.17
|   Time   V(typ)   V(min)   V(max)
0s        957.9mV    931.6mV    1.002V
47ps      956.1mV    930.3mV    1.002V
56ps      957mV      928.6mV    1.014V
71ps      977.1mV    931.6mV    1.061V
89ps      1.022V     960.1mV    1.104V
105ps     1.049V     993.6mV    1.126V
118ps     1.063V     1.013V     1.139V
142ps     1.08V      1.034V     1.154V
219ps     1.097V     1.056V     1.168V
377ps     1.1V       1.06V      1.17V
[Falling Waveform]
R_fixture = 50
V_fixture = 0.0
|   Time   V(typ)   V(min)   V(max)
0s        229.9mV    229.2mV    245.2mV
60ps      233.2mV    230.3mV    242.1mV
75ps      226.8mV    234.5mV    189.6mV
88ps      193.3mV    228.9mV    124.6mV
100ps     143.6mV    204.7mV    85.22mV
115ps     92.19mV    154.6mV    53.62mV
146ps     37.7mV     67.98mV    20.76mV
173ps     17.56mV    32.58mV    9.247mV
213ps     5.903mV    11.29mV    2.953mV
377ps     534.5uV    587.2uV    346.3uV
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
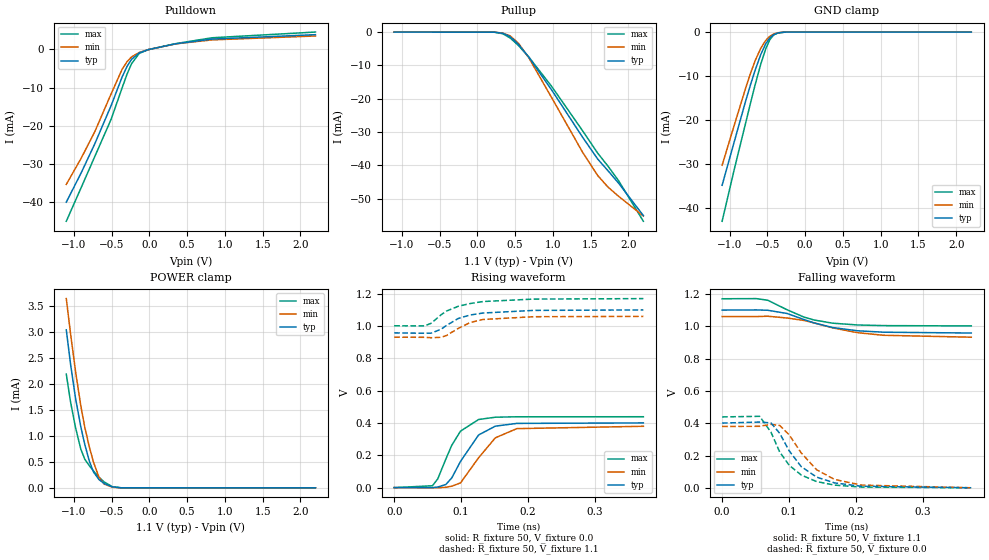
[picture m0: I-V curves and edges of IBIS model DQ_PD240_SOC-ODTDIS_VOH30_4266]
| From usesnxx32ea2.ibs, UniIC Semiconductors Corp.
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| DQ_PD240_SOC-ODTDIS_VOH30_4266
| (240 Ohm Pulldown, SOC ODT disabled setting, VOH=VDDQ/3.0 cal. point, 3200-4266Mbps)
[Model]   DQ_PD240_SOC-ODTDIS_VOH30_4266
Model_type   I/O
Vinl = 123.333mV
Vinh = 243.333mV
Vmeas = 183.333mV
Vref = 0.0mV
Cref = 0.0pF
|   typ   min   max
|C_comp   0.834pF   0.784pF   0.884pF
C_comp_pullup   0.4170pF   0.3920pF   0.4420pF
C_comp_pulldown   0.4170pF   0.3920pF   0.4420pF
| Note: C_comp changes when the ODT circuit is enabled.
[Model Spec]
| Input threshold voltage corners
Vinl   0.1233V   0.1167V   0.1350V
Vinh   0.2433V   0.2367V   0.2550V
| Measurement voltage corners
Vmeas   0.1833V   0.1767V   0.1950V
| Timing spec test load voltage corners
Vref   0.0000V   0.0000V   0.0000V
| Dynamic Overshoot Parameters from LPDDR4 Specification
D_overshoot_ampl_h   0.30   NA   NA
D_overshoot_ampl_l   0.30   NA   NA
D_overshoot_area_h   0.1n   NA   NA
D_overshoot_area_l   0.1n   NA   NA
[Voltage Range]   1.1000V   1.0600V   1.1700V
[Pullup Reference]   1.1000V   1.0600V   1.1700V
| Junction Temperature (Ambient temp is 35C typ 95C min -40C max)
[Temperature Range]   50.0   110.0   -40.0
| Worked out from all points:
|   slope of the pulldown table from 0 to 0.165 V, typ, clamps not added: 220 ohm
|   slope of the pullup table from 0 to 0.165 V, typ, clamps not added: 13 kohm
|   GND clamp passes 1 mA (typ) near -0.45 V on its own axis
|   POWER clamp passes 1 mA (typ) near -0.88 V on its own axis
|   rising waveform, R_fixture 50, V_fixture 0.0: 20-80 % time 35.7ps typ, 40.1ps min, 30.6ps max; typ from 0.001 V to 0.401 V
|   falling waveform, R_fixture 50, V_fixture 1.1: 20-80 % time 70.7ps typ, 83ps min, 59.6ps max; typ from 1.1 V to 0.958 V
|   rising waveform, R_fixture 50, V_fixture 1.1: 20-80 % time 44.5ps typ, 39.4ps min, 48.5ps max; typ from 0.958 V to 1.1 V
|   falling waveform, R_fixture 50, V_fixture 0.0: 20-80 % time 46.3ps typ, 50.2ps min, 42.6ps max; typ from 0.401 V to 0.001 V
[Pulldown]
|   Voltage   I(typ)   I(min)   I(max)
-1.1V     -39.98mA   -35.34mA   -44.98mA
-905.3mV  -32.42mA   -28.59mA   -36.29mA
-723.8mV  -24.78mA   -21.61mA   -28.11mA
-506mV    -14.73mA   -11.66mA   -18.3mA
-360.8mV  -7.258mA   -5.26mA    -10.11mA
-294.8mV  -4.462mA   -3.223mA   -6.477mA
-235.4mV  -2.618mA   -1.998mA   -3.772mA
-133.1mV  -930.7uA   -828.7uA   -1.072mA
-14.3mV   -103.2uA   -97.68uA   -93.65uA
345.4mV   1.423mA    1.399mA    1.456mA
827.2mV   2.654mA    2.447mA    3mA
2.2V      3.814mA    3.471mA    4.502mA
[GND Clamp]
|   Voltage   I(typ)   I(min)   I(max)
-1.1V     -34.74mA   -30.21mA   -42.91mA
-938.3mV  -24.81mA   -21.07mA   -31.08mA
-786.5mV  -15.53mA   -12.6mA    -20.49mA
-723.8mV  -11.93mA   -9.348mA   -16.1mA
-664.4mV  -8.736mA   -6.578mA   -12.07mA
-588.5mV  -5.113mA   -3.681mA   -7.298mA
-522.5mV  -2.665mA   -1.902mA   -3.81mA
-469.7mV  -1.357mA   -985.8uA   -1.786mA
-416.9mV  -596.9uA   -445.2uA   -664.6uA
-357.5mV  -190.9uA   -145.5uA   -173.6uA
-261.8mV  -17.64uA   -15.8uA    -11.03uA
2.2V      0A         0A         0A
[Pullup]
|   Voltage   I(typ)   I(min)   I(max)
-1.1V     6.275uA    9.671uA    2.829uA
229.9mV   -45.05uA   -45.78uA   -46.55uA
338.8mV   -360uA     -300.3uA   -497uA
437.8mV   -1.437mA   -1.178mA   -1.807mA
546.7mV   -3.713mA   -3.398mA   -4.054mA
682mV     -7.507mA   -7.687mA   -7.459mA
988.9mV   -17.49mA   -19.81mA   -16.41mA
1.395V    -31.53mA   -36.04mA   -29.6mA
1.596V    -38.11mA   -43.04mA   -36.34mA
1.731V    -41.57mA   -46.48mA   -40.2mA
1.87V     -45.25mA   -49.21mA   -44.52mA
2.2V      -55.05mA   -55.17mA   -56.74mA
[POWER Clamp]
|   Voltage   I(typ)   I(min)   I(max)
-1.1V     3.033mA    3.633mA    2.184mA
-1.044V   2.381mA    2.967mA    1.653mA
-977.9mV  1.723mA    2.241mA    1.16mA
-908.6mV  1.178mA    1.583mA    748.3uA
-855.8mV  837.8uA    1.171mA    552.1uA
-796.4mV  521.2uA    794.7uA    427.2uA
-740.3mV  306.2uA    494.3uA    324.2uA
-667.7mV  159.9uA    206uA      205.2uA
-598.4mV  83.67uA    71.95uA    113uA
-489.5mV  17.78uA    10.84uA    22.44uA
-377.3mV  1.488uA    1.077uA    1.222uA
2.2V      0A         0A         0A
[Ramp]
|   typ   min   max
| 20% - 80%
dV/dt_r   239.98m/35.71p   227.55m/40.05p   263.11m/30.63p
dV/dt_f   85.15m/70.66p   76.64m/82.72p   100.80m/59.41p
| 25% - 75%
|dV/dt_r   199.98m/28.42p   189.63m/31.82p   219.26m/24.42p
|dV/dt_f   70.95m/56.15p   63.87m/65.16p   84.00m/47.33p
R_load = 50
[Rising Waveform]
R_fixture = 50
V_fixture = 0.0
|   Time   V(typ)   V(min)   V(max)
0s        1.129mV    1.006mV    811.2uV
57ps      706.4uV    -98.67uV   12.39mV
65ps      4.663mV    -441.9uV   54.75mV
77ps      19.82mV    3.132mV    176.5mV
86ps      61.27mV    9.777mV    263.4mV
99ps      163.1mV    30.04mV    350.3mV
126ps     326.6mV    185.5mV    422.2mV
151ps     381.1mV    309mV      436.4mV
183ps     398.1mV    365.7mV    439.1mV
372ps     401.1mV    380.3mV    439.3mV
[Falling Waveform]
R_fixture   = 50
V_fixture   = 1.1
V_fixture_min = 1.06
V_fixture_max = 1.17
|   Time   V(typ)   V(min)   V(max)
0s        1.1V       1.06V      1.17V
51ps      1.101V     1.06V      1.171V
68ps      1.099V     1.062V     1.161V
97ps      1.079V     1.051V     1.102V
122ps     1.042V     1.036V     1.057V
137ps     1.021V     1.021V     1.039V
165ps     992.1mV    990.1mV    1.019V
202ps     972.1mV    960.4mV    1.008V
241ps     963.2mV    944.2mV    1.004V
372ps     958.1mV    932.3mV    1.002V
[Rising Waveform]
R_fixture   = 50
V_fixture   = 1.1
V_fixture_min = 1.06
V_fixture_max = 1.17
|   Time   V(typ)   V(min)   V(max)
0s        957.9mV    931.6mV    1.002V
45ps      955.9mV    930.6mV    1.001V
55ps      956.2mV    928.1mV    1.017V
70ps      980.5mV    930.7mV    1.07V
78ps      1.004V     941.8mV    1.093V
96ps      1.048V     986.8mV    1.123V
114ps     1.069V     1.023V     1.14V
133ps     1.081V     1.041V     1.152V
208ps     1.097V     1.058V     1.167V
372ps     1.1V       1.06V      1.17V
[Falling Waveform]
R_fixture = 50
V_fixture = 0.0
|   Time   V(typ)   V(min)   V(max)
0s        401.2mV    380.4mV    439.4mV
56ps      407.6mV    381.4mV    443.1mV
73ps      402.3mV    393.3mV    344.5mV
86ps      337.8mV    386.4mV    222.3mV
100ps     230.8mV    329.6mV    140.9mV
118ps     132.5mV    217.3mV    80.31mV
141ps     67.28mV    112.8mV    39.64mV
168ps     31.2mV     52.38mV    17.57mV
208ps     10.67mV    17.86mV    5.644mV
372ps     1.281mV    1.279mV    863.3uV
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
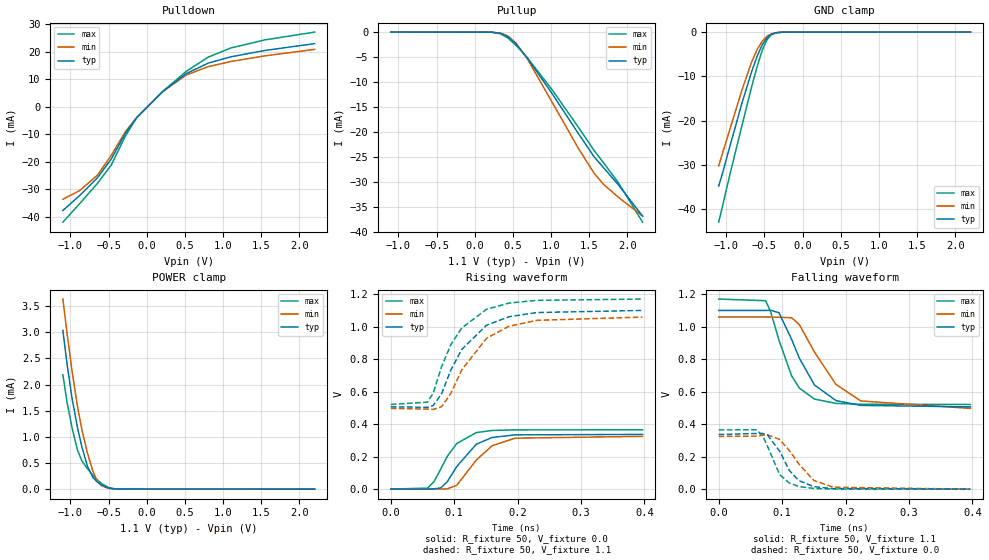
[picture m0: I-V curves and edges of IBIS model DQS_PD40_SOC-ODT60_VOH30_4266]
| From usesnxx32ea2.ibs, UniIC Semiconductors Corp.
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| DQS_PD40_SOC-ODT60_VOH30_4266
| (40 Ohm Pulldown, 60 Ohm System ODT Setting, VOH=VDDQ/3.0, 3200-4266Mbps)
[Model]   DQS_PD40_SOC-ODT60_VOH30_4266
Model_type   I/O
Vinl = 123.333mV
Vinh = 243.333mV
Vmeas = 183.333mV
Vref = 0.0mV
Cref = 0.0pF
Rref = 60.000Ohm
|   typ   min   max
|C_comp   0.849pF   0.799pF   0.899pF
C_comp_pullup   0.4245pF   0.3995pF   0.4495pF
C_comp_pulldown   0.4245pF   0.3995pF   0.4495pF
| Note: C_comp changes when the ODT circuit is enabled.
[Model Spec]
| Input threshold voltage corners
Vinl   0.1233V   0.1167V   0.1350V
Vinh   0.2433V   0.2367V   0.2550V
| Measurement voltage corners
Vmeas   0.1833V   0.1767V   0.1950V
| Timing spec test load voltage corners
Vref   0.0000V   0.0000V   0.0000V
| Dynamic Overshoot Parameters from LPDDR4 Specification
D_overshoot_ampl_h   0.30   NA   NA
D_overshoot_ampl_l   0.30   NA   NA
D_overshoot_area_h   0.1n   NA   NA
D_overshoot_area_l   0.1n   NA   NA
[Voltage Range]   1.1000V   1.0600V   1.1700V
[Pullup Reference]   1.1000V   1.0600V   1.1700V
| Junction Temperature (Ambient temp is 35C typ 95C min -40C max)
[Temperature Range]   50.0   110.0   -40.0
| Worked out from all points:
|   slope of the pulldown table from 0 to 0.165 V, typ, clamps not added: 37 ohm
|   slope of the pullup table from 0 to 0.165 V, typ, clamps not added: 19.5 kohm
|   GND clamp passes 1 mA (typ) near -0.45 V on its own axis
|   POWER clamp passes 1 mA (typ) near -0.88 V on its own axis
|   rising waveform, R_fixture 50, V_fixture 0.0: 20-80 % time 39.3ps typ, 43.1ps min, 34.6ps max; typ from 0 V to 0.337 V
|   falling waveform, R_fixture 50, V_fixture 1.1: 20-80 % time 45.5ps typ, 57.2ps min, 35.7ps max; typ from 1.1 V to 0.507 V
|   rising waveform, R_fixture 50, V_fixture 1.1: 20-80 % time 56.4ps typ, 60.1ps min, 51.9ps max; typ from 0.507 V to 1.1 V
|   falling waveform, R_fixture 50, V_fixture 0.0: 20-80 % time 30.5ps typ, 39ps min, 25.4ps max; typ from 0.337 V to 0 V
[Pulldown]
|   Voltage   I(typ)   I(min)   I(max)
-1.1V     -37.77mA   -33.68mA   -42.02mA
-882.2mV  -32.36mA   -30.55mA   -35.35mA
-644.6mV  -25.77mA   -24.84mA   -27.81mA
-466.4mV  -19.07mA   -17.71mA   -21.24mA
-278.3mV  -9.52mA    -9.004mA   -10.55mA
-133.1mV  -3.981mA   -3.954mA   -4.007mA
210.1mV   5.579mA    5.517mA    5.64mA
517mV     12.05mA    11.56mA    12.88mA
804.1mV   15.88mA    14.6mA     18.05mA
1.104V    18.19mA    16.48mA    21.42mA
1.55V     20.5mA     18.53mA    24.35mA
2.2V      22.98mA    20.89mA    27.18mA
[GND Clamp]
|   Voltage   I(typ)   I(min)   I(max)
-1.1V     -34.74mA   -30.21mA   -42.91mA
-1.05V    -31.86mA   -27.33mA   -39.27mA
-948.2mV  -25.43mA   -21.63mA   -31.79mA
-793.1mV  -15.92mA   -12.96mA   -20.96mA
-667.7mV  -8.907mA   -6.722mA   -12.29mA
-591.8mV  -5.257mA   -3.789mA   -7.492mA
-525.8mV  -2.766mA   -1.974mA   -3.964mA
-469.7mV  -1.358mA   -985.2uA   -1.79mA
-413.6mV  -564.7uA   -417.7uA   -621.4uA
-354.2mV  -179uA     -136.3uA   -160.3uA
-261.8mV  -17.71uA   -15.38uA   -11.03uA
2.2V      0A         0A         0A
[Pullup]
|   Voltage   I(typ)   I(min)   I(max)
-1.1V     4.183uA    6.447uA    1.886uA
226.6mV   -28.06uA   -28.66uA   -28.52uA
338.8mV   -241.1uA   -199.2uA   -331.5uA
434.5mV   -925.4uA   -756.7uA   -1.171mA
543.4mV   -2.433mA   -2.221mA   -2.665mA
688.6mV   -5.173mA   -5.328mA   -5.121mA
1.022V    -12.5mA    -14.24mA   -11.71mA
1.365V    -20.49mA   -23.47mA   -19.21mA
1.566V    -25.01mA   -28.3mA    -23.76mA
1.685V    -27.11mA   -30.46mA   -26.11mA
1.883V    -30.61mA   -33.11mA   -30.19mA
2.2V      -36.89mA   -36.87mA   -38.1mA
[POWER Clamp]
|   Voltage   I(typ)   I(min)   I(max)
-1.1V     3.033mA    3.633mA    2.184mA
-1.044V   2.381mA    2.967mA    1.652mA
-977.9mV  1.723mA    2.241mA    1.16mA
-908.6mV  1.177mA    1.582mA    748.4uA
-849.2mV  799.1uA    1.125mA    535.4uA
-776.6mV  434.1uA    683.2uA    390.2uA
-707.3mV  225.3uA    345.3uA    267.6uA
-651.2mV  138.6uA    162.3uA    181.2uA
-591.8mV  77.98uA    64.79uA    105.5uA
-496.1mV  20.06uA    12.31uA    25.8uA
-397.1mV  2.386uA    1.592uA    2.119uA
2.2V      0A         0A         0A
[Ramp]
|   typ   min   max
| 20% - 80%
dV/dt_r   201.89m/39.30p   194.62m/43.14p   218.94m/34.60p
dV/dt_f   356.01m/45.52p   337.69m/57.19p   389.18m/35.71p
| 25% - 75%
|dV/dt_r   168.24m/31.31p   162.19m/34.40p   182.45m/27.47p
|dV/dt_f   296.67m/36.31p   281.41m/45.66p   324.32m/28.42p
R_load = 50
[Rising Waveform]
R_fixture = 50
V_fixture = 0.0
|   Time   V(typ)   V(min)   V(max)
0s        363.5uV    303.1uV    269.2uV
58ps      91.71uV    182.6uV    6.001mV
68ps      689uV      -395.5uV   45.41mV
79ps      8.537mV    -20.79uV   125.4mV
89ps      44.97mV    1.404mV    201.1mV
104ps     138.9mV    23.45mV    281mV
135ps     277mV      179.6mV    348.1mV
160ps     318mV      267.6mV    361.1mV
196ps     333.9mV    313.5mV    364.7mV
397ps     336.8mV    324.7mV    365.2mV
[Falling Waveform]
R_fixture   = 50
V_fixture   = 1.1
V_fixture_min = 1.06
V_fixture_max = 1.17
|   Time   V(typ)   V(min)   V(max)
0s        1.1V       1.06V      1.17V
74ps      1.1V       1.06V      1.16V
82ps      1.101V     1.059V     1.091V
95ps      1.086V     1.058V     917.3mV
115ps     922.1mV    1.055V     697.4mV
127ps     807.3mV    1.014V     622.8mV
151ps     641.4mV    843.8mV    554.5mV
185ps     545.1mV    644.4mV    528.1mV
224ps     515.7mV    543.1mV    522.5mV
397ps     506.6mV    497.2mV    521.4mV
[Rising Waveform]
R_fixture   = 50
V_fixture   = 1.1
V_fixture_min = 1.06
V_fixture_max = 1.17
|   Time   V(typ)   V(min)   V(max)
0s        506.5mV    496.8mV    521.3mV
58ps      503.6mV    492.4mV    535.1mV
67ps      514.9mV    490.5mV    592.2mV
80ps      586.9mV    507mV      752.7mV
95ps      735mV      591.3mV    891.7mV
112ps     860.6mV    734.7mV    992.5mV
151ps     1.009V     928.8mV    1.107V
186ps     1.061V     1.002V     1.145V
230ps     1.087V     1.039V     1.162V
397ps     1.1V       1.059V     1.17V
[Falling Waveform]
R_fixture = 50
V_fixture = 0.0
|   Time   V(typ)   V(min)   V(max)
0s        336.9mV    324.8mV    365.2mV
59ps      342.6mV    326.8mV    365.8mV
69ps      343.5mV    332.1mV    331.6mV
77ps      333mV      334.7mV    263.9mV
96ps      234.4mV    306.6mV    90.53mV
111ps     117.8mV    239.7mV    38.59mV
126ps     53.77mV    157.6mV    16.8mV
150ps     15.62mV    53.69mV    4.746mV
181ps     3.629mV    12.01mV    1.149mV
397ps     429.6uV    397.7uV    290.3uV
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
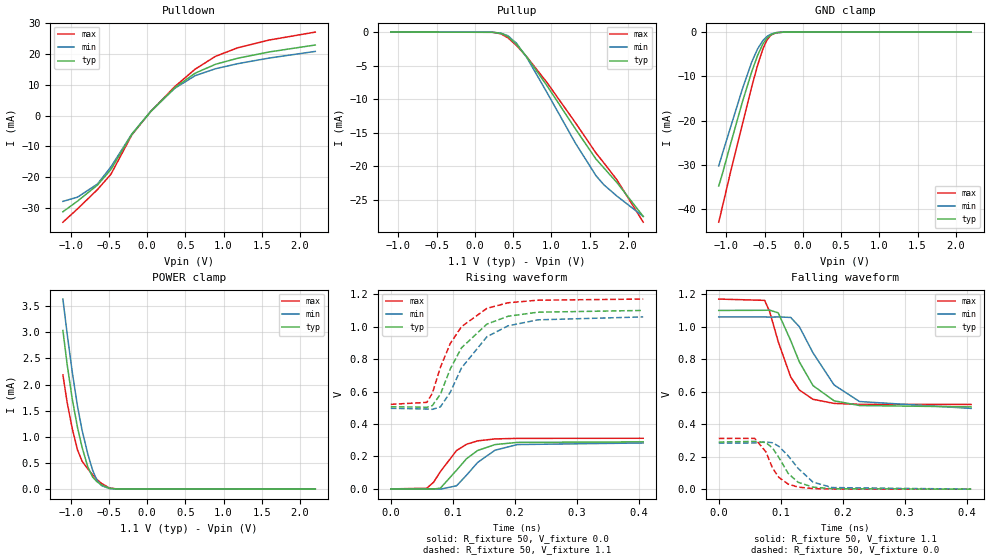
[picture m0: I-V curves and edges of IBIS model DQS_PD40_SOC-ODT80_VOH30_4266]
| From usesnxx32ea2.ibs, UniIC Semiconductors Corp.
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| DQS_PD40_SOC-ODT80_VOH30_4266
| (40 Ohm Pulldown, 80 Ohm System ODT Setting, VOH=VDDQ/3.0, 3200-4266Mbps)
[Model]   DQS_PD40_SOC-ODT80_VOH30_4266
Model_type   I/O
Vinl = 123.333mV
Vinh = 243.333mV
Vmeas = 183.333mV
Vref = 0.0mV
Cref = 0.0pF
Rref = 80.000Ohm
|   typ   min   max
|C_comp   0.849pF   0.799pF   0.899pF
C_comp_pullup   0.4245pF   0.3995pF   0.4495pF
C_comp_pulldown   0.4245pF   0.3995pF   0.4495pF
| Note: C_comp changes when the ODT circuit is enabled.
[Model Spec]
| Input threshold voltage corners
Vinl   0.1233V   0.1167V   0.1350V
Vinh   0.2433V   0.2367V   0.2550V
| Measurement voltage corners
Vmeas   0.1833V   0.1767V   0.1950V
| Timing spec test load voltage corners
Vref   0.0000V   0.0000V   0.0000V
| Dynamic Overshoot Parameters from LPDDR4 Specification
D_overshoot_ampl_h   0.30   NA   NA
D_overshoot_ampl_l   0.30   NA   NA
D_overshoot_area_h   0.1n   NA   NA
D_overshoot_area_l   0.1n   NA   NA
[Voltage Range]   1.1000V   1.0600V   1.1700V
[Pullup Reference]   1.1000V   1.0600V   1.1700V
| Junction Temperature (Ambient temp is 35C typ 95C min -40C max)
[Temperature Range]   50.0   110.0   -40.0
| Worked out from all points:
|   slope of the pulldown table from 0 to 0.165 V, typ, clamps not added: 37 ohm
|   slope of the pullup table from 0 to 0.165 V, typ, clamps not added: 26.1 kohm
|   GND clamp passes 1 mA (typ) near -0.45 V on its own axis
|   POWER clamp passes 1 mA (typ) near -0.88 V on its own axis
|   rising waveform, R_fixture 50, V_fixture 0.0: 20-80 % time 42.7ps typ, 45.8ps min, 37.5ps max; typ from 0 V to 0.29 V
|   falling waveform, R_fixture 50, V_fixture 1.1: 20-80 % time 45.4ps typ, 57ps min, 35.7ps max; typ from 1.1 V to 0.507 V
|   rising waveform, R_fixture 50, V_fixture 1.1: 20-80 % time 56.6ps typ, 60.9ps min, 51.9ps max; typ from 0.507 V to 1.1 V
|   falling waveform, R_fixture 50, V_fixture 0.0: 20-80 % time 30.9ps typ, 39.5ps min, 25.9ps max; typ from 0.29 V to 0 V
[Pulldown]
|   Voltage   I(typ)   I(min)   I(max)
-1.1V     -31.31mA   -27.93mA   -34.7mA
-908.6mV  -27.84mA   -26.55mA   -30.36mA
-647.9mV  -22.61mA   -22.26mA   -24.08mA
-473mV    -17.57mA   -16.73mA   -19.12mA
-199.1mV  -6.09mA    -6.003mA   -6.313mA
45.1mV    1.251mA    1.248mA    1.244mA
361.9mV   9.076mA    8.876mA    9.401mA
629.2mV   13.8mA     13mA       15.12mA
896.5mV   16.71mA    15.26mA    19.3mA
1.187V    18.68mA    16.9mA     22.08mA
1.599V    20.72mA    18.74mA    24.6mA
2.2V      22.98mA    20.89mA    27.18mA
[GND Clamp]
|   Voltage   I(typ)   I(min)   I(max)
-1.1V     -34.74mA   -30.21mA   -42.91mA
-1.05V    -31.86mA   -27.33mA   -39.27mA
-948.2mV  -25.43mA   -21.63mA   -31.79mA
-789.8mV  -15.72mA   -12.78mA   -20.72mA
-667.7mV  -8.907mA   -6.722mA   -12.29mA
-591.8mV  -5.255mA   -3.789mA   -7.492mA
-522.5mV  -2.664mA   -1.903mA   -3.81mA
-469.7mV  -1.357mA   -989uA     -1.787mA
-416.9mV  -599.4uA   -443.4uA   -664.6uA
-347.6mV  -155.1uA   -118.6uA   -135.6uA
-245.3mV  -11.33uA   -10.25uA   -6.369uA
2.2V      0A         0A         0A
[Pullup]
|   Voltage   I(typ)   I(min)   I(max)
-1.1V     3.138uA    4.837uA    1.415uA
229.9mV   -22.53uA   -22.97uA   -23.3uA
338.8mV   -180.5uA   -149.2uA   -248.4uA
431.2mV   -668.2uA   -545uA     -849.2uA
543.4mV   -1.824mA   -1.665mA   -1.997mA
678.7mV   -3.725mA   -3.812mA   -3.703mA
939.4mV   -7.962mA   -8.969mA   -7.487mA
1.312V    -14.42mA   -16.55mA   -13.5mA
1.583V    -18.96mA   -21.44mA   -18.06mA
1.685V    -20.27mA   -22.79mA   -19.52mA
1.857V    -22.47mA   -24.49mA   -22.07mA
2.2V      -27.52mA   -27.52mA   -28.38mA
[POWER Clamp]
|   Voltage   I(typ)   I(min)   I(max)
-1.1V     3.033mA    3.633mA    2.184mA
-1.044V   2.381mA    2.967mA    1.653mA
-977.9mV  1.723mA    2.241mA    1.16mA
-908.6mV  1.177mA    1.582mA    748.4uA
-849.2mV  799.1uA    1.125mA    535.4uA
-773.3mV  420.7uA    665.2uA    384.1uA
-710.6mV  232.3uA    359uA      273.1uA
-657.8mV  146.8uA    178.8uA    190.6uA
-595.1mV  80.77uA    68.32uA    109.2uA
-492.8mV  18.88uA    11.58uA    24.03uA
-383.9mV  1.735uA    1.224uA    1.462uA
2.2V      0A         0A         0A
[Ramp]
|   typ   min   max
| 20% - 80%
dV/dt_r   173.95m/42.73p   169.89m/45.76p   187.33m/37.46p
dV/dt_f   356.02m/45.40p   337.73m/57.02p   389.18m/35.64p
| 25% - 75%
|dV/dt_r   144.96m/34.08p   141.58m/36.51p   156.11m/29.72p
|dV/dt_f   296.68m/36.22p   281.45m/45.56p   324.32m/28.38p
R_load = 50
[Rising Waveform]
R_fixture = 50
V_fixture = 0.0
|   Time   V(typ)   V(min)   V(max)
0s        266.5uV    214.3uV    200.5uV
58ps      -164.4uV   311.4uV    4.479mV
69ps      -891.1uV   -598.9uV   41.55mV
80ps      5.238mV    -1.315mV   107.1mV
106ps     115.2mV    19.5mV     236.7mV
122ps     185.9mV    84.47mV    275.1mV
140ps     236.9mV    163.3mV    296.3mV
168ps     273.4mV    238.7mV    308.3mV
204ps     286.9mV    273.5mV    311.7mV
407ps     290.2mV    283.4mV    312.4mV
[Falling Waveform]
R_fixture   = 50
V_fixture   = 1.1
V_fixture_min = 1.06
V_fixture_max = 1.17
|   Time   V(typ)   V(min)   V(max)
0s        1.1V       1.06V      1.17V
74ps      1.101V     1.06V      1.162V
82ps      1.102V     1.059V     1.094V
96ps      1.085V     1.06V      906.7mV
116ps     915.1mV    1.057V     691.1mV
130ps     783.4mV    1V         610.5mV
152ps     637.7mV    839.2mV    553.2mV
186ps     544.1mV    641.5mV    527.9mV
227ps     514.8mV    539.4mV    522.3mV
407ps     506.6mV    497.1mV    521.4mV
[Rising Waveform]
R_fixture   = 50
V_fixture   = 1.1
V_fixture_min = 1.06
V_fixture_max = 1.17
|   Time   V(typ)   V(min)   V(max)
0s        506.5mV    496.8mV    521.3mV
58ps      503.4mV    492.6mV    533.4mV
67ps      513.7mV    490.5mV    589.5mV
80ps      584.1mV    505.7mV    750.2mV
96ps      740.8mV    596.5mV    897.1mV
114ps     869.6mV    745.9mV    1V
155ps     1.016V     938.1mV    1.113V
189ps     1.064V     1.005V     1.147V
237ps     1.089V     1.042V     1.163V
407ps     1.1V       1.06V      1.17V
[Falling Waveform]
R_fixture = 50
V_fixture = 0.0
|   Time   V(typ)   V(min)   V(max)
0s        290.3mV    283.5mV    312.5mV
58ps      294.3mV    284.6mV    312.7mV
76ps      287mV      291.3mV    230.2mV
87ps      252.2mV    285.5mV    128.2mV
97ps      194.8mV    263.4mV    72.52mV
112ps     97.17mV    205.2mV    31.36mV
128ps     42.61mV    128.4mV    13.07mV
152ps     12.6mV     43.6mV     3.715mV
183ps     2.982mV    10.09mV    912uV
407ps     335.7uV    314.5uV    222.4uV
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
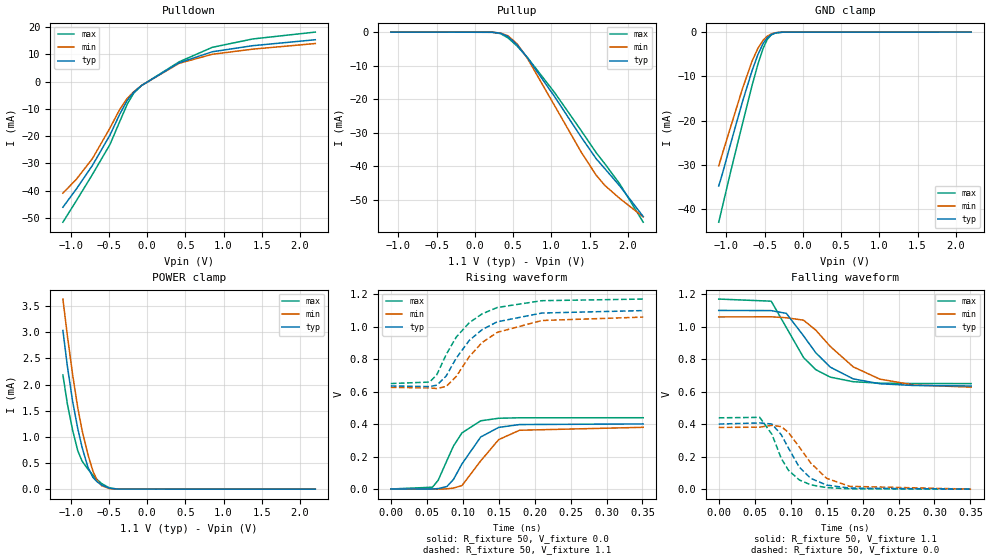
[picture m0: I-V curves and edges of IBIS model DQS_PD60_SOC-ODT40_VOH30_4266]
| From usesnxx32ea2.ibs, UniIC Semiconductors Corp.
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| DQS_PD60_SOC-ODT40_VOH30_4266
| (60 Ohm Pulldown, 40 Ohm System ODT Setting, VOH=VDDQ/3.0, 3200-4266Mbps)
[Model]   DQS_PD60_SOC-ODT40_VOH30_4266
Model_type   I/O
Vinl = 123.333mV
Vinh = 243.333mV
Vmeas = 183.333mV
Vref = 0.0mV
Cref = 0.0pF
Rref = 40.000Ohm
|   typ   min   max
|C_comp   0.849pF   0.799pF   0.899pF
C_comp_pullup   0.4245pF   0.3995pF   0.4495pF
C_comp_pulldown   0.4245pF   0.3995pF   0.4495pF
| Note: C_comp changes when the ODT circuit is enabled.
[Model Spec]
| Input threshold voltage corners
Vinl   0.1233V   0.1167V   0.1350V
Vinh   0.2433V   0.2367V   0.2550V
| Measurement voltage corners
Vmeas   0.1833V   0.1767V   0.1950V
| Timing spec test load voltage corners
Vref   0.0000V   0.0000V   0.0000V
| Dynamic Overshoot Parameters from LPDDR4 Specification
D_overshoot_ampl_h   0.30   NA   NA
D_overshoot_ampl_l   0.30   NA   NA
D_overshoot_area_h   0.1n   NA   NA
D_overshoot_area_l   0.1n   NA   NA
[Voltage Range]   1.1000V   1.0600V   1.1700V
[Pullup Reference]   1.1000V   1.0600V   1.1700V
| Junction Temperature (Ambient temp is 35C typ 95C min -40C max)
[Temperature Range]   50.0   110.0   -40.0
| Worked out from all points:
|   slope of the pulldown table from 0 to 0.165 V, typ, clamps not added: 54.7 ohm
|   slope of the pullup table from 0 to 0.165 V, typ, clamps not added: 13 kohm
|   GND clamp passes 1 mA (typ) near -0.45 V on its own axis
|   POWER clamp passes 1 mA (typ) near -0.88 V on its own axis
|   rising waveform, R_fixture 50, V_fixture 0.0: 20-80 % time 35ps typ, 39ps min, 30.3ps max; typ from 0.001 V to 0.401 V
|   falling waveform, R_fixture 50, V_fixture 1.1: 20-80 % time 54ps typ, 66.1ps min, 43.5ps max; typ from 1.1 V to 0.635 V
|   rising waveform, R_fixture 50, V_fixture 1.1: 20-80 % time 55.1ps typ, 57.5ps min, 52.4ps max; typ from 0.635 V to 1.1 V
|   falling waveform, R_fixture 50, V_fixture 0.0: 20-80 % time 34.8ps typ, 42ps min, 30.2ps max; typ from 0.401 V to 0.001 V
[Pulldown]
|   Voltage   I(typ)   I(min)   I(max)
-1.1V     -46.14mA   -40.95mA   -51.63mA
-928.4mV  -39.62mA   -36.03mA   -43.95mA
-713.9mV  -30.79mA   -28.29mA   -34.11mA
-482.9mV  -19.57mA   -16.97mA   -23.02mA
-357.5mV  -12.02mA   -10.26mA   -14.71mA
-258.5mV  -6.92mA    -6.188mA   -8.302mA
-176mV    -3.987mA   -3.794mA   -4.358mA
-70.4mV   -1.447mA   -1.429mA   -1.433mA
421.3mV   6.907mA    6.712mA    7.246mA
853.6mV   10.93mA    10mA       12.56mA
1.382V    13.16mA    11.89mA    15.63mA
2.2V      15.34mA    13.95mA    18.15mA
[GND Clamp]
|   Voltage   I(typ)   I(min)   I(max)
-1.1V     -34.74mA   -30.21mA   -42.91mA
-1.05V    -31.86mA   -27.33mA   -39.27mA
-938.3mV  -24.81mA   -21.07mA   -31.08mA
-789.8mV  -15.72mA   -12.78mA   -20.72mA
-664.4mV  -8.736mA   -6.578mA   -12.07mA
-588.5mV  -5.113mA   -3.681mA   -7.298mA
-519.2mV  -2.566mA   -1.833mA   -3.66mA
-466.4mV  -1.294mA   -943.6uA   -1.691mA
-413.6mV  -564.7uA   -417.5uA   -621.7uA
-354.2mV  -178.4uA   -135.4uA   -160.5uA
-255.2mV  -14.78uA   -13.08uA   -8.858uA
2.2V      0A         0A         0A
[Pullup]
|   Voltage   I(typ)   I(min)   I(max)
-1.1V     6.275uA    9.671uA    2.829uA
229.9mV   -45.11uA   -46.01uA   -46.56uA
332.2mV   -321.8uA   -269.6uA   -442.3uA
431.2mV   -1.332mA   -1.087mA   -1.694mA
550mV     -3.795mA   -3.486mA   -4.131mA
685.3mV   -7.607mA   -7.806mA   -7.548mA
1.042V    -19.28mA   -21.97mA   -18.07mA
1.385V    -31.19mA   -35.66mA   -29.27mA
1.586V    -37.82mA   -42.74mA   -36.02mA
1.698V    -40.75mA   -45.75mA   -39.28mA
1.893V    -45.92mA   -49.65mA   -45.31mA
2.2V      -55.05mA   -55.15mA   -56.74mA
[POWER Clamp]
|   Voltage   I(typ)   I(min)   I(max)
-1.1V     3.033mA    3.633mA    2.184mA
-1.041V   2.345mA    2.929mA    1.625mA
-971.3mV  1.665mA    2.173mA    1.116mA
-905.3mV  1.155mA    1.553mA    732.3uA
-849.2mV  799uA      1.125mA    535.6uA
-773.3mV  420.7uA    665.3uA    384.1uA
-707.3mV  225.5uA    345.5uA    267.6uA
-651.2mV  138.6uA    162.3uA    181.2uA
-591.8mV  77.94uA    64.8uA     105.5uA
-489.5mV  17.77uA    10.88uA    22.48uA
-380.6mV  1.609uA    1.138uA    1.345uA
2.2V      0A         0A         0A
[Ramp]
|   typ   min   max
| 20% - 80%
dV/dt_r   240.24m/34.97p   227.79m/39.04p   263.30m/30.33p
dV/dt_f   278.79m/54.03p   259.05m/66.11p   312.07m/43.50p
| 25% - 75%
|dV/dt_r   200.20m/27.85p   189.82m/31.09p   219.41m/24.09p
|dV/dt_f   232.33m/43.03p   215.87m/52.69p   260.06m/34.62p
R_load = 50
[Rising Waveform]
R_fixture = 50
V_fixture = 0.0
|   Time   V(typ)   V(min)   V(max)
0s        701.6uV    613.5uV    508.4uV
58ps      514.8uV    -95.55uV   11.58mV
66ps      3.219mV    -535uV     55.51mV
78ps      15.84mV    1.701mV    175.5mV
87ps      58.39mV    5.992mV    264.1mV
99ps      155.2mV    21.91mV    346.3mV
125ps     320.7mV    173.6mV    420.4mV
150ps     379.7mV    304.4mV    436.1mV
179ps     397.3mV    362.2mV    439mV
351ps     401.1mV    380.3mV    439.3mV
[Falling Waveform]
R_fixture   = 50
V_fixture   = 1.1
V_fixture_min = 1.06
V_fixture_max = 1.17
|   Time   V(typ)   V(min)   V(max)
0s        1.1V       1.06V      1.17V
73ps      1.099V     1.061V     1.157V
94ps      1.082V     1.055V     995mV
118ps     943.4mV    1.04V      810mV
135ps     839.3mV    978.7mV    735.6mV
155ps     751.6mV    879mV      689.9mV
187ps     679.1mV    753.1mV    661.6mV
224ps     649mV      677.5mV    652.7mV
271ps     638.3mV    641.5mV    650.4mV
351ps     635.3mV    628.2mV    649.9mV
[Rising Waveform]
R_fixture   = 50
V_fixture   = 1.1
V_fixture_min = 1.06
V_fixture_max = 1.17
|   Time   V(typ)   V(min)   V(max)
0s        635mV      626.1mV    649.8mV
54ps      631.1mV    622.7mV    658.9mV
64ps      640mV      619.2mV    704.7mV
77ps      696.3mV    631.8mV    828.3mV
91ps      806.6mV    693.5mV    936mV
109ps     914.8mV    814.9mV    1.024V
127ps     981.8mV    902.8mV    1.079V
148ps     1.03V      965mV      1.118V
210ps     1.084V     1.038V     1.16V
351ps     1.099V     1.059V     1.17V
[Falling Waveform]
R_fixture = 50
V_fixture = 0.0
|   Time   V(typ)   V(min)   V(max)
0s        401.2mV    380.4mV    439.4mV
57ps      408mV      381.8mV    442.3mV
74ps      401.3mV    393.4mV    337.7mV
87ps      335.4mV    385.2mV    189.3mV
97ps      253.1mV    349.2mV    116.7mV
112ps     135.9mV    259.8mV    57.24mV
128ps     66.92mV    161.2mV    27.14mV
150ps     25.7mV     67.34mV    10.06mV
182ps     6.984mV    17.98mV    2.69mV
351ps     759.2uV    719uV      528.1uV
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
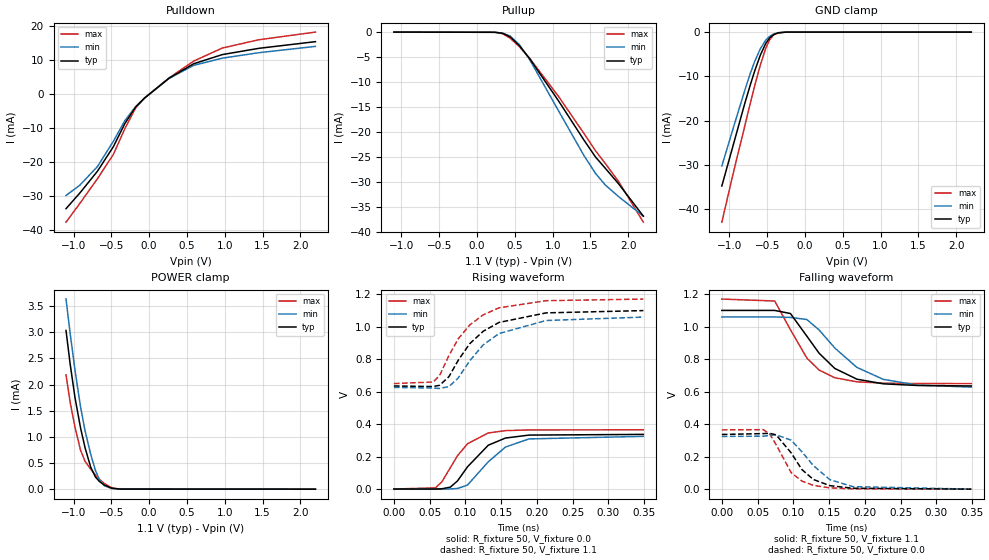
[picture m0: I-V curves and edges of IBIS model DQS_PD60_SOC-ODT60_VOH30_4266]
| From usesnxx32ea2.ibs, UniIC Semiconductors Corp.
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| DQS_PD60_SOC-ODT60_VOH30_4266
| (60 Ohm Pulldown, 60 Ohm System ODT Setting, VOH=VDDQ/3.0, 3200-4266Mbps)
[Model]   DQS_PD60_SOC-ODT60_VOH30_4266
Model_type   I/O
Vinl = 123.333mV
Vinh = 243.333mV
Vmeas = 183.333mV
Vref = 0.0mV
Cref = 0.0pF
Rref = 60.000Ohm
|   typ   min   max
|C_comp   0.849pF   0.799pF   0.899pF
C_comp_pullup   0.4245pF   0.3995pF   0.4495pF
C_comp_pulldown   0.4245pF   0.3995pF   0.4495pF
| Note: C_comp changes when the ODT circuit is enabled.
[Model Spec]
| Input threshold voltage corners
Vinl   0.1233V   0.1167V   0.1350V
Vinh   0.2433V   0.2367V   0.2550V
| Measurement voltage corners
Vmeas   0.1833V   0.1767V   0.1950V
| Timing spec test load voltage corners
Vref   0.0000V   0.0000V   0.0000V
| Dynamic Overshoot Parameters from LPDDR4 Specification
D_overshoot_ampl_h   0.30   NA   NA
D_overshoot_ampl_l   0.30   NA   NA
D_overshoot_area_h   0.1n   NA   NA
D_overshoot_area_l   0.1n   NA   NA
[Voltage Range]   1.1000V   1.0600V   1.1700V
[Pullup Reference]   1.1000V   1.0600V   1.1700V
| Junction Temperature (Ambient temp is 35C typ 95C min -40C max)
[Temperature Range]   50.0   110.0   -40.0
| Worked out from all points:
|   slope of the pulldown table from 0 to 0.165 V, typ, clamps not added: 54.9 ohm
|   slope of the pullup table from 0 to 0.165 V, typ, clamps not added: 19.5 kohm
|   GND clamp passes 1 mA (typ) near -0.45 V on its own axis
|   POWER clamp passes 1 mA (typ) near -0.88 V on its own axis
|   rising waveform, R_fixture 50, V_fixture 0.0: 20-80 % time 39.8ps typ, 43.7ps min, 34.9ps max; typ from 0 V to 0.337 V
|   falling waveform, R_fixture 50, V_fixture 1.1: 20-80 % time 53.7ps typ, 65.5ps min, 43.2ps max; typ from 1.1 V to 0.635 V
|   rising waveform, R_fixture 50, V_fixture 1.1: 20-80 % time 55.8ps typ, 59ps min, 52.2ps max; typ from 0.635 V to 1.1 V
|   falling waveform, R_fixture 50, V_fixture 0.0: 20-80 % time 34.7ps typ, 42.3ps min, 30ps max; typ from 0.337 V to 0.001 V
[Pulldown]
|   Voltage   I(typ)   I(min)   I(max)
-1.1V     -33.69mA   -29.81mA   -37.65mA
-918.5mV  -29.13mA   -26.82mA   -32.19mA
-684.2mV  -22.7mA    -21.33mA   -24.89mA
-473mV    -15.47mA   -13.89mA   -17.74mA
-321.2mV  -8.698mA   -7.822mA   -10.19mA
-179.3mV  -3.868mA   -3.748mA   -4.114mA
-60.5mV   -1.212mA   -1.204mA   -1.195mA
262.9mV   4.608mA    4.54mA     4.696mA
589.6mV   8.859mA    8.394mA    9.639mA
969.1mV   11.55mA    10.5mA     13.47mA
1.448V    13.37mA    12.09mA    15.89mA
2.2V      15.34mA    13.95mA    18.15mA
[GND Clamp]
|   Voltage   I(typ)   I(min)   I(max)
-1.1V     -34.74mA   -30.22mA   -42.91mA
-944.9mV  -25.23mA   -21.44mA   -31.55mA
-796.4mV  -16.11mA   -13.14mA   -21.19mA
-723.8mV  -11.93mA   -9.349mA   -16.1mA
-664.4mV  -8.736mA   -6.578mA   -12.07mA
-591.8mV  -5.255mA   -3.789mA   -7.493mA
-519.2mV  -2.565mA   -1.832mA   -3.66mA
-466.4mV  -1.294mA   -942uA     -1.691mA
-413.6mV  -564.7uA   -417.1uA   -621.5uA
-354.2mV  -178.2uA   -134.5uA   -160uA
-251.9mV  -13.34uA   -11.9uA    -7.88uA
2.2V      0A         0A         0A
[Pullup]
|   Voltage   I(typ)   I(min)   I(max)
-1.1V     4.184uA    6.447uA    1.886uA
233.2mV   -32.57uA   -32.57uA   -33.77uA
335.5mV   -227.6uA   -188.6uA   -312.9uA
434.5mV   -925.6uA   -756.8uA   -1.171mA
556.6mV   -2.656mA   -2.458mA   -2.871mA
695.2mV   -5.309mA   -5.489mA   -5.24mA
1.078V    -13.79mA   -15.78mA   -12.9mA
1.411V    -21.57mA   -24.66mA   -20.25mA
1.566V    -25.01mA   -28.3mA    -23.76mA
1.698V    -27.32mA   -30.67mA   -26.36mA
1.873V    -30.42mA   -32.98mA   -29.96mA
2.2V      -36.89mA   -36.88mA   -38.1mA
[POWER Clamp]
|   Voltage   I(typ)   I(min)   I(max)
-1.1V     3.033mA    3.633mA    2.184mA
-1.044V   2.381mA    2.967mA    1.653mA
-981.2mV  1.752mA    2.275mA    1.183mA
-908.6mV  1.178mA    1.582mA    748.9uA
-849.2mV  799uA      1.125mA    535.5uA
-773.3mV  420.8uA    665.2uA    384.1uA
-710.6mV  232.2uA    359.1uA    273.1uA
-657.8mV  146.8uA    178.9uA    190.7uA
-595.1mV  80.77uA    68.29uA    109.3uA
-496.1mV  20.06uA    12.31uA    25.72uA
-390.5mV  2.036uA    1.382uA    1.767uA
2.2V      0A         0A         0A
[Ramp]
|   typ   min   max
| 20% - 80%
dV/dt_r   201.83m/39.76p   194.56m/43.73p   218.89m/34.90p
dV/dt_f   278.76m/53.65p   259.05m/65.50p   312.07m/43.27p
| 25% - 75%
|dV/dt_r   168.19m/31.74p   162.14m/34.85p   182.41m/27.73p
|dV/dt_f   232.30m/42.76p   215.87m/52.22p   260.06m/34.39p
R_load = 50
[Rising Waveform]
R_fixture = 50
V_fixture = 0.0
|   Time   V(typ)   V(min)   V(max)
0s        464.8uV    400.6uV    339.4uV
58ps      324.4uV    15.1uV     7.762mV
67ps      1.966mV    -349.5uV   44.26mV
79ps      12.18mV    1.022mV    132mV
89ps      50.67mV    3.933mV    205.8mV
103ps     137.4mV    25.18mV    279.4mV
132ps     270.2mV    168.1mV    345.6mV
156ps     314.3mV    258.7mV    360mV
189ps     332.6mV    309.1mV    364.4mV
349ps     336.8mV    324.7mV    365.2mV
[Falling Waveform]
R_fixture   = 50
V_fixture   = 1.1
V_fixture_min = 1.06
V_fixture_max = 1.17
|   Time   V(typ)   V(min)   V(max)
0s        1.1V       1.06V      1.17V
74ps      1.1V       1.06V      1.158V
96ps      1.081V     1.057V     981.3mV
119ps     941.5mV    1.044V     806.6mV
136ps     837.1mV    980.3mV    733.5mV
158ps     743.3mV    869.1mV    686mV
189ps     677mV      749.4mV    660.9mV
226ps     648.4mV    675.8mV    652.6mV
274ps     638.2mV    640.6mV    650.3mV
349ps     635.4mV    628.2mV    649.9mV
[Rising Waveform]
R_fixture   = 50
V_fixture   = 1.1
V_fixture_min = 1.06
V_fixture_max = 1.17
|   Time   V(typ)   V(min)   V(max)
0s        635mV      626.1mV    649.8mV
55ps      631.5mV    622.4mV    659.3mV
64ps      639.2mV    619.6mV    700.1mV
77ps      692.5mV    631.4mV    822.9mV
90ps      793.2mV    684.1mV    925.3mV
106ps     895mV      789.5mV    1.01V
125ps     972.1mV    888.2mV    1.073V
147ps     1.026V     957.7mV    1.116V
213ps     1.085V     1.038V     1.16V
349ps     1.099V     1.059V     1.17V
[Falling Waveform]
R_fixture = 50
V_fixture = 0.0
|   Time   V(typ)   V(min)   V(max)
0s        336.9mV    324.8mV    365.2mV
58ps      342.3mV    326.4mV    366.5mV
67ps      344.2mV    331.2mV    339.7mV
76ps      334.2mV    334.9mV    273.5mV
97ps      223.7mV    301.7mV    102.1mV
112ps     121.1mV    230.9mV    50.24mV
128ps     60.02mV    145.6mV    23.85mV
151ps     22.16mV    59.28mV    8.458mV
183ps     6.007mV    16.13mV    2.206mV
349ps     542.3uV    526.3uV    362.3uV
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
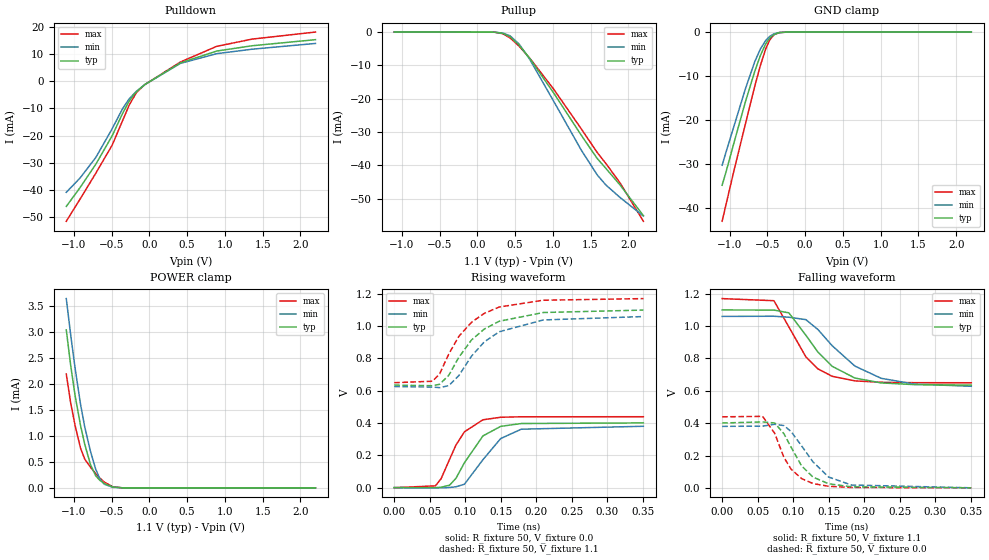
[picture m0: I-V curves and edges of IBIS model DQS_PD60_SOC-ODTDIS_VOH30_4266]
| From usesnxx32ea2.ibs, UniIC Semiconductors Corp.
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| DQS_PD60_SOC-ODTDIS_VOH30_4266
| (60 Ohm Pulldown, SOC ODT disabled setting, VOH=VDDQ/3.0 cal. point, 3200-4266Mbps)
[Model]   DQS_PD60_SOC-ODTDIS_VOH30_4266
Model_type   I/O
Vinl = 123.333mV
Vinh = 243.333mV
Vmeas = 183.333mV
Vref = 0.0mV
Cref = 0.0pF
|   typ   min   max
|C_comp   0.849pF   0.799pF   0.899pF
C_comp_pullup   0.4245pF   0.3995pF   0.4495pF
C_comp_pulldown   0.4245pF   0.3995pF   0.4495pF
| Note: C_comp changes when the ODT circuit is enabled.
[Model Spec]
| Input threshold voltage corners
Vinl   0.1233V   0.1167V   0.1350V
Vinh   0.2433V   0.2367V   0.2550V
| Measurement voltage corners
Vmeas   0.1833V   0.1767V   0.1950V
| Timing spec test load voltage corners
Vref   0.0000V   0.0000V   0.0000V
| Dynamic Overshoot Parameters from LPDDR4 Specification
D_overshoot_ampl_h   0.30   NA   NA
D_overshoot_ampl_l   0.30   NA   NA
D_overshoot_area_h   0.1n   NA   NA
D_overshoot_area_l   0.1n   NA   NA
[Voltage Range]   1.1000V   1.0600V   1.1700V
[Pullup Reference]   1.1000V   1.0600V   1.1700V
| Junction Temperature (Ambient temp is 35C typ 95C min -40C max)
[Temperature Range]   50.0   110.0   -40.0
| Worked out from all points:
|   slope of the pulldown table from 0 to 0.165 V, typ, clamps not added: 54.8 ohm
|   slope of the pullup table from 0 to 0.165 V, typ, clamps not added: 13 kohm
|   GND clamp passes 1 mA (typ) near -0.45 V on its own axis
|   POWER clamp passes 1 mA (typ) near -0.88 V on its own axis
|   rising waveform, R_fixture 50, V_fixture 0.0: 20-80 % time 35ps typ, 39ps min, 30.3ps max; typ from 0.001 V to 0.401 V
|   falling waveform, R_fixture 50, V_fixture 1.1: 20-80 % time 54ps typ, 66.1ps min, 43.5ps max; typ from 1.1 V to 0.635 V
|   rising waveform, R_fixture 50, V_fixture 1.1: 20-80 % time 55.1ps typ, 57.5ps min, 52.4ps max; typ from 0.635 V to 1.1 V
|   falling waveform, R_fixture 50, V_fixture 0.0: 20-80 % time 34.8ps typ, 42ps min, 30.2ps max; typ from 0.401 V to 0.001 V
[Pulldown]
|   Voltage   I(typ)   I(min)   I(max)
-1.1V     -46.14mA   -40.94mA   -51.62mA
-918.5mV  -39.24mA   -35.7mA    -43.49mA
-710.6mV  -30.65mA   -28.16mA   -33.97mA
-492.8mV  -20.14mA   -17.52mA   -23.58mA
-357.5mV  -12.02mA   -10.26mA   -14.71mA
-265.1mV  -7.208mA   -6.415mA   -8.684mA
-172.7mV  -3.892mA   -3.712mA   -4.234mA
-60.5mV   -1.24mA    -1.226mA   -1.224mA
411.4mV   6.776mA    6.592mA    7.095mA
893.2mV   11.15mA    10.18mA    12.89mA
1.365V    13.11mA    11.84mA    15.56mA
2.2V      15.34mA    13.95mA    18.15mA
[GND Clamp]
|   Voltage   I(typ)   I(min)   I(max)
-1.1V     -34.74mA   -30.21mA   -42.91mA
-1.047V   -31.66mA   -27.15mA   -39.02mA
-941.6mV  -25.02mA   -21.26mA   -31.32mA
-789.8mV  -15.72mA   -12.78mA   -20.72mA
-667.7mV  -8.907mA   -6.722mA   -12.29mA
-595.1mV  -5.399mA   -3.899mA   -7.688mA
-522.5mV  -2.666mA   -1.905mA   -3.811mA
-469.7mV  -1.359mA   -987.8uA   -1.786mA
-413.6mV  -563.7uA   -416.4uA   -619.9uA
-344.3mV  -144.1uA   -109.8uA   -124.4uA
-238.7mV  -9.035uA   -8.519uA   -5.04uA
2.2V      0A         0A         0A
[Pullup]
|   Voltage   I(typ)   I(min)   I(max)
-1.1V     6.275uA    9.671uA    2.829uA
229.9mV   -45.12uA   -45.81uA   -46.58uA
338.8mV   -360.2uA   -298.3uA   -496uA
434.5mV   -1.385mA   -1.132mA   -1.75mA
553.3mV   -3.878mA   -3.573mA   -4.208mA
691.9mV   -7.808mA   -8.045mA   -7.726mA
1.009V    -18.16mA   -20.62mA   -17.03mA
1.378V    -30.95mA   -35.41mA   -29.04mA
1.589V    -37.92mA   -42.84mA   -36.13mA
1.702V    -40.84mA   -45.82mA   -39.37mA
1.89V     -45.83mA   -49.59mA   -45.19mA
2.2V      -55.05mA   -55.17mA   -56.74mA
[POWER Clamp]
|   Voltage   I(typ)   I(min)   I(max)
-1.1V     3.033mA    3.633mA    2.184mA
-1.041V   2.345mA    2.929mA    1.625mA
-984.5mV  1.782mA    2.31mA     1.205mA
-911.9mV  1.201mA    1.61mA     764.7uA
-855.8mV  837.7uA    1.171mA    552.1uA
-779.9mV  447.9uA    701.4uA    396.3uA
-710.6mV  232.3uA    359.1uA    273.1uA
-657.8mV  146.8uA    178.8uA    190.7uA
-595.1mV  80.76uA    68.28uA    109.2uA
-482.9mV  15.73uA    9.557uA    19.51uA
-360.8mV  1.018uA    768.5nA    796.1nA
2.2V      0A         0A         0A
[Ramp]
|   typ   min   max
| 20% - 80%
dV/dt_r   240.24m/34.97p   227.79m/39.04p   263.30m/30.33p
dV/dt_f   278.79m/54.03p   259.05m/66.11p   312.07m/43.50p
| 25% - 75%
|dV/dt_r   200.20m/27.85p   189.82m/31.09p   219.41m/24.09p
|dV/dt_f   232.33m/43.03p   215.87m/52.69p   260.06m/34.62p
R_load = 50
[Rising Waveform]
R_fixture = 50
V_fixture = 0.0
|   Time   V(typ)   V(min)   V(max)
0s        701.6uV    613.5uV    508.4uV
58ps      514.8uV    -95.55uV   11.58mV
66ps      3.219mV    -535uV     55.51mV
78ps      15.84mV    1.701mV    175.5mV
87ps      58.39mV    5.992mV    264.1mV
99ps      155.2mV    21.91mV    346.3mV
125ps     320.7mV    173.6mV    420.4mV
150ps     379.7mV    304.4mV    436.1mV
179ps     397.3mV    362.2mV    439mV
351ps     401.1mV    380.3mV    439.3mV
[Falling Waveform]
R_fixture   = 50
V_fixture   = 1.1
V_fixture_min = 1.06
V_fixture_max = 1.17
|   Time   V(typ)   V(min)   V(max)
0s        1.1V       1.06V      1.17V
73ps      1.099V     1.061V     1.157V
94ps      1.082V     1.055V     995mV
118ps     943.4mV    1.04V      810mV
135ps     839.3mV    978.7mV    735.6mV
155ps     751.6mV    879mV      689.9mV
187ps     679.1mV    753.1mV    661.6mV
224ps     649mV      677.5mV    652.7mV
271ps     638.3mV    641.5mV    650.4mV
351ps     635.3mV    628.2mV    649.9mV
[Rising Waveform]
R_fixture   = 50
V_fixture   = 1.1
V_fixture_min = 1.06
V_fixture_max = 1.17
|   Time   V(typ)   V(min)   V(max)
0s        635mV      626.1mV    649.8mV
54ps      631.1mV    622.7mV    658.9mV
64ps      640mV      619.2mV    704.7mV
77ps      696.3mV    631.8mV    828.3mV
91ps      806.6mV    693.5mV    936mV
109ps     914.8mV    814.9mV    1.024V
127ps     981.8mV    902.8mV    1.079V
148ps     1.03V      965mV      1.118V
210ps     1.084V     1.038V     1.16V
351ps     1.099V     1.059V     1.17V
[Falling Waveform]
R_fixture = 50
V_fixture = 0.0
|   Time   V(typ)   V(min)   V(max)
0s        401.2mV    380.4mV    439.4mV
57ps      408mV      381.8mV    442.3mV
74ps      401.3mV    393.4mV    337.7mV
87ps      335.4mV    385.2mV    189.3mV
97ps      253.1mV    349.2mV    116.7mV
112ps     135.9mV    259.8mV    57.24mV
128ps     66.92mV    161.2mV    27.14mV
150ps     25.7mV     67.34mV    10.06mV
182ps     6.984mV    17.98mV    2.69mV
351ps     759.2uV    719uV      528.1uV
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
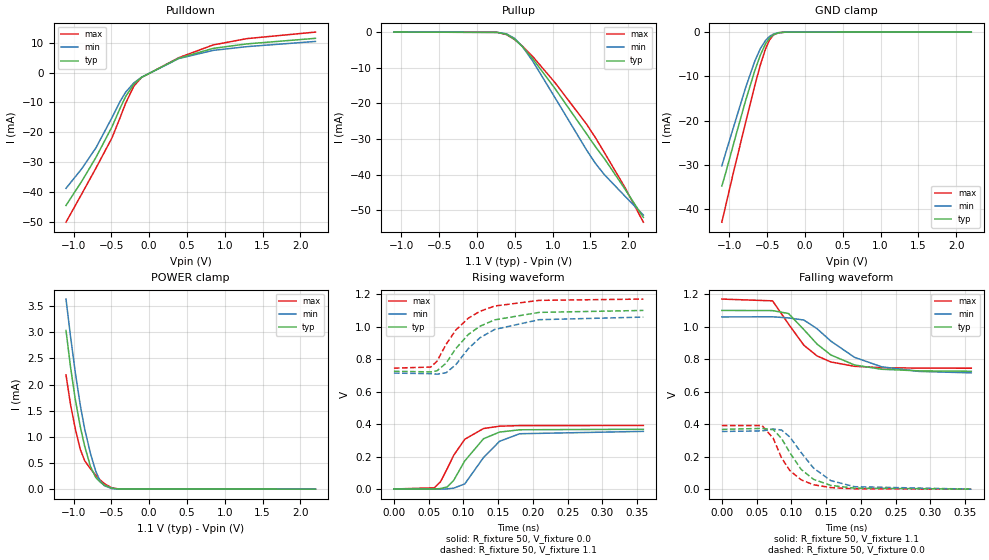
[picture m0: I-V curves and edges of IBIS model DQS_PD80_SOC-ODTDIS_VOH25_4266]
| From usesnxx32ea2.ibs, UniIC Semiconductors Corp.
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| DQS_PD80_SOC-ODTDIS_VOH25_4266
| (80 Ohm Pulldown, SOC ODT disabled setting, VOH=VDDQ/2.5 cal. point, 3200-4266Mbps)
[Model]   DQS_PD80_SOC-ODTDIS_VOH25_4266
Model_type   I/O
Vinl = 160.000mV
Vinh = 280.000mV
Vmeas = 220.000mV
Vref = 0.0mV
Cref = 0.0pF
|   typ   min   max
|C_comp   0.849pF   0.799pF   0.899pF
C_comp_pullup   0.4245pF   0.3995pF   0.4495pF
C_comp_pulldown   0.4245pF   0.3995pF   0.4495pF
| Note: C_comp changes when the ODT circuit is enabled.
[Model Spec]
| Input threshold voltage corners
Vinl   0.1600V   0.1520V   0.1740V
Vinh   0.2800V   0.2720V   0.2940V
| Measurement voltage corners
Vmeas   0.2200V   0.2120V   0.2340V
| Timing spec test load voltage corners
Vref   0.0000V   0.0000V   0.0000V
| Dynamic Overshoot Parameters from LPDDR4 Specification
D_overshoot_ampl_h   0.30   NA   NA
D_overshoot_ampl_l   0.30   NA   NA
D_overshoot_area_h   0.1n   NA   NA
D_overshoot_area_l   0.1n   NA   NA
[Voltage Range]   1.1000V   1.0600V   1.1700V
[Pullup Reference]   1.1000V   1.0600V   1.1700V
| Junction Temperature (Ambient temp is 35C typ 95C min -40C max)
[Temperature Range]   50.0   110.0   -40.0
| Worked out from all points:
|   slope of the pulldown table from 0 to 0.165 V, typ, clamps not added: 73.9 ohm
|   slope of the pullup table from 0 to 0.165 V, typ, clamps not added: 17.7 kohm
|   GND clamp passes 1 mA (typ) near -0.45 V on its own axis
|   POWER clamp passes 1 mA (typ) near -0.88 V on its own axis
|   rising waveform, R_fixture 50, V_fixture 0.0: 20-80 % time 35.1ps typ, 38.9ps min, 32ps max; typ from 0.001 V to 0.368 V
|   falling waveform, R_fixture 50, V_fixture 1.1: 20-80 % time 58ps typ, 69ps min, 47.3ps max; typ from 1.1 V to 0.726 V
|   rising waveform, R_fixture 50, V_fixture 1.1: 20-80 % time 54.9ps typ, 56.7ps min, 51.7ps max; typ from 0.726 V to 1.1 V
|   falling waveform, R_fixture 50, V_fixture 0.0: 20-80 % time 38.3ps typ, 44.3ps min, 32.9ps max; typ from 0.368 V to 0.001 V
[Pulldown]
|   Voltage   I(typ)   I(min)   I(max)
-1.1V     -44.48mA   -38.75mA   -50.09mA
-892.1mV  -36.4mA    -32.2mA    -40.64mA
-704mV    -28.42mA   -25.19mA   -31.99mA
-492.8mV  -18.21mA   -15.13mA   -21.9mA
-383.9mV  -11.9mA    -9.616mA   -15.05mA
-311.3mV  -8.018mA   -6.571mA   -10.27mA
-202.4mV  -3.82mA    -3.443mA   -4.514mA
-100.1mV  -1.592mA   -1.543mA   -1.618mA
391.6mV   4.819mA    4.708mA    5.003mA
847mV     8.116mA    7.448mA    9.269mA
1.292V    9.612mA    8.694mA    11.38mA
2.2V      11.48mA    10.44mA    13.57mA
[GND Clamp]
|   Voltage   I(typ)   I(min)   I(max)
-1.1V     -34.75mA   -30.2mA    -42.92mA
-1.05V    -31.86mA   -27.33mA   -39.27mA
-941.6mV  -25.02mA   -21.25mA   -31.32mA
-786.5mV  -15.53mA   -12.6mA    -20.5mA
-664.4mV  -8.74mA    -6.576mA   -12.08mA
-591.8mV  -5.258mA   -3.788mA   -7.5mA
-522.5mV  -2.666mA   -1.906mA   -3.813mA
-469.7mV  -1.357mA   -986.7uA   -1.787mA
-416.9mV  -598uA     -442.2uA   -665.2uA
-350.9mV  -166.4uA   -126.3uA   -147.4uA
-258.5mV  -16.15uA   -14.14uA   -9.927uA
2.2V      0A         0A         0A
[Pullup]
|   Voltage   I(typ)   I(min)   I(max)
-1.1V     4.106uA    7.431uA    1.361uA
266.2mV   -69.17uA   -67.98uA   -71.79uA
388.3mV   -576.1uA   -478.3uA   -687.4uA
497.2mV   -1.982mA   -1.772mA   -2.09mA
599.5mV   -4.068mA   -4.034mA   -3.93mA
734.8mV   -7.452mA   -8.085mA   -6.824mA
1.025V    -15.68mA   -18.21mA   -14.03mA
1.448V    -28.55mA   -33.09mA   -25.83mA
1.566V    -32.18mA   -36.88mA   -29.66mA
1.685V    -35.54mA   -40.05mA   -33.84mA
1.956V    -44.08mA   -46.07mA   -43.63mA
2.2V      -52.05mA   -51.39mA   -53.39mA
[POWER Clamp]
|   Voltage   I(typ)   I(min)   I(max)
-1.1V     3.033mA    3.633mA    2.184mA
-1.041V   2.345mA    2.929mA    1.625mA
-977.9mV  1.723mA    2.241mA    1.16mA
-911.9mV  1.2mA      1.611mA    764.4uA
-852.5mV  818.1uA    1.148mA    543.5uA
-776.6mV  434.1uA    683.3uA    390.2uA
-707.3mV  225.4uA    345.5uA    267.6uA
-651.2mV  138.6uA    162.3uA    181.2uA
-591.8mV  77.94uA    64.81uA    105.5uA
-496.1mV  20.04uA    12.32uA    25.73uA
-393.8mV  2.196uA    1.489uA    1.934uA
2.2V      0A         0A         0A
[Ramp]
|   typ   min   max
| 20% - 80%
dV/dt_r   220.51m/35.12p   212.86m/38.87p   234.61m/31.95p
dV/dt_f   224.46m/57.99p   206.41m/68.96p   255.16m/47.24p
| 25% - 75%
|dV/dt_r   183.76m/27.95p   177.38m/30.96p   195.51m/25.38p
|dV/dt_f   187.05m/46.15p   172.01m/54.89p   212.64m/37.50p
R_load = 50
[Rising Waveform]
R_fixture = 50
V_fixture = 0.0
|   Time   V(typ)   V(min)   V(max)
0s        836.2uV    685.8uV    613uV
58ps      506.9uV    -45.3uV    7.832mV
67ps      3.418mV    -439.2uV   44.62mV
77ps      13.93mV    1.482mV    127.9mV
86ps      53.46mV    5.803mV    207.8mV
102ps     173.7mV    31.95mV    306.9mV
129ps     310.1mV    194.6mV    373mV
152ps     351mV      294.2mV    387.2mV
181ps     365.2mV    340.8mV    391mV
359ps     368.4mV    355.4mV    391.6mV
[Falling Waveform]
R_fixture   = 50
V_fixture   = 1.1
V_fixture_min = 1.06
V_fixture_max = 1.17
|   Time   V(typ)   V(min)   V(max)
0s        1.1V       1.06V      1.17V
73ps      1.099V     1.061V     1.159V
96ps      1.081V     1.054V     1.016V
118ps     982.4mV    1.041V     886.3mV
137ps     893.3mV    987.8mV    820.4mV
157ps     825.9mV    911.1mV    782.9mV
191ps     764.5mV    811.4mV    756.4mV
230ps     738.2mV    753.4mV    747.8mV
284ps     728.3mV    724.8mV    745.2mV
359ps     725.9mV    716mV      744.7mV
[Rising Waveform]
R_fixture   = 50
V_fixture   = 1.1
V_fixture_min = 1.06
V_fixture_max = 1.17
|   Time   V(typ)   V(min)   V(max)
0s        725.5mV    714.2mV    744.7mV
53ps      721.5mV    710.7mV    751.4mV
62ps      728.2mV    707.5mV    787.3mV
75ps      774.9mV    716.2mV    890.4mV
89ps      864.6mV    765.3mV    979mV
107ps     951.9mV    864.6mV    1.052V
124ps     1.003V     932.4mV    1.095V
145ps     1.042V     982.9mV    1.127V
209ps     1.088V     1.043V     1.162V
359ps     1.1V       1.059V     1.17V
[Falling Waveform]
R_fixture = 50
V_fixture = 0.0
|   Time   V(typ)   V(min)   V(max)
0s        368.5mV    355.6mV    391.7mV
58ps      374.4mV    359mV      391.8mV
74ps      367mV      370.3mV    313.1mV
86ps      312.3mV    364.2mV    192.4mV
98ps      224.6mV    321.2mV    114.5mV
114ps     122.9mV    226.6mV    58.43mV
132ps     61.05mV    130.3mV    27.72mV
157ps     23.47mV    52.97mV    10.16mV
191ps     6.912mV    15.81mV    2.96mV
359ps     897.5uV    805.7uV    637uV
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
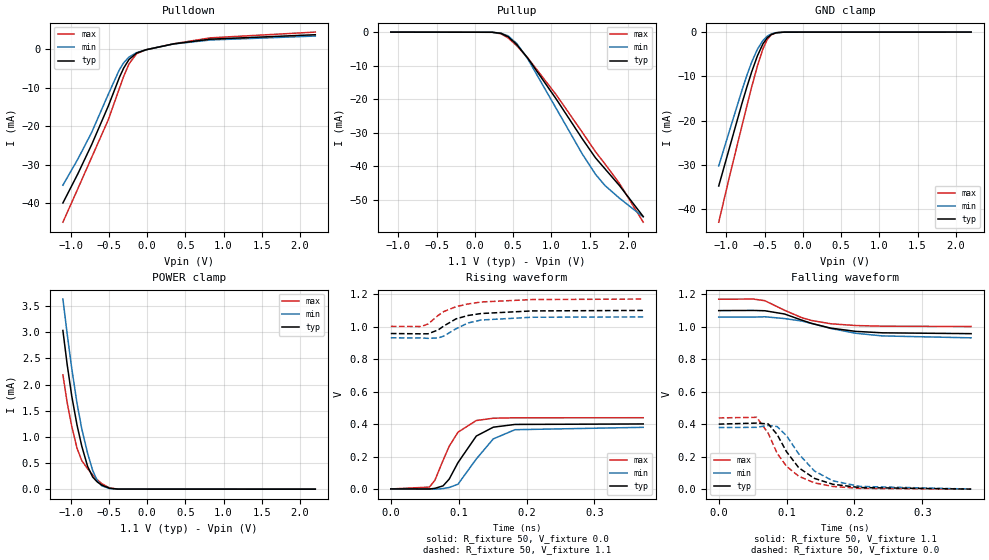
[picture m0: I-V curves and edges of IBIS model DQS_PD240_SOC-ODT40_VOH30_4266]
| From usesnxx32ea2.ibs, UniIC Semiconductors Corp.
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| DQS_PD240_SOC-ODT40_VOH30_4266
| (240 Ohm Pulldown, 40 Ohm System ODT Setting, VOH=VDDQ/3.0, 3200-4266Mbps)
[Model]   DQS_PD240_SOC-ODT40_VOH30_4266
Model_type   I/O
Vinl = 123.333mV
Vinh = 243.333mV
Vmeas = 183.333mV
Vref = 0.0mV
Cref = 0.0pF
Rref = 40.000Ohm
|   typ   min   max
|C_comp   0.849pF   0.799pF   0.899pF
C_comp_pullup   0.4245pF   0.3995pF   0.4495pF
C_comp_pulldown   0.4245pF   0.3995pF   0.4495pF
| Note: C_comp changes when the ODT circuit is enabled.
[Model Spec]
| Input threshold voltage corners
Vinl   0.1233V   0.1167V   0.1350V
Vinh   0.2433V   0.2367V   0.2550V
| Measurement voltage corners
Vmeas   0.1833V   0.1767V   0.1950V
| Timing spec test load voltage corners
Vref   0.0000V   0.0000V   0.0000V
| Dynamic Overshoot Parameters from LPDDR4 Specification
D_overshoot_ampl_h   0.30   NA   NA
D_overshoot_ampl_l   0.30   NA   NA
D_overshoot_area_h   0.1n   NA   NA
D_overshoot_area_l   0.1n   NA   NA
[Voltage Range]   1.1000V   1.0600V   1.1700V
[Pullup Reference]   1.1000V   1.0600V   1.1700V
| Junction Temperature (Ambient temp is 35C typ 95C min -40C max)
[Temperature Range]   50.0   110.0   -40.0
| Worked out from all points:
|   slope of the pulldown table from 0 to 0.165 V, typ, clamps not added: 220 ohm
|   slope of the pullup table from 0 to 0.165 V, typ, clamps not added: 13 kohm
|   GND clamp passes 1 mA (typ) near -0.45 V on its own axis
|   POWER clamp passes 1 mA (typ) near -0.88 V on its own axis
|   rising waveform, R_fixture 50, V_fixture 0.0: 20-80 % time 35.7ps typ, 40.1ps min, 30.6ps max; typ from 0.001 V to 0.401 V
|   falling waveform, R_fixture 50, V_fixture 1.1: 20-80 % time 70.7ps typ, 83ps min, 59.6ps max; typ from 1.1 V to 0.958 V
|   rising waveform, R_fixture 50, V_fixture 1.1: 20-80 % time 44.5ps typ, 39.4ps min, 48.5ps max; typ from 0.958 V to 1.1 V
|   falling waveform, R_fixture 50, V_fixture 0.0: 20-80 % time 46.3ps typ, 50.2ps min, 42.6ps max; typ from 0.401 V to 0.001 V
[Pulldown]
|   Voltage   I(typ)   I(min)   I(max)
-1.1V     -39.98mA   -35.35mA   -44.98mA
-905.3mV  -32.42mA   -28.59mA   -36.29mA
-723.8mV  -24.78mA   -21.61mA   -28.11mA
-506mV    -14.73mA   -11.66mA   -18.3mA
-360.8mV  -7.259mA   -5.26mA    -10.11mA
-304.7mV  -4.835mA   -3.484mA   -6.989mA
-235.4mV  -2.628mA   -1.994mA   -3.771mA
-136.4mV  -964.2uA   -855.3uA   -1.121mA
-14.3mV   -103.3uA   -97.8uA    -93.62uA
345.4mV   1.423mA    1.399mA    1.456mA
827.2mV   2.654mA    2.447mA    3mA
2.2V      3.814mA    3.471mA    4.502mA
[GND Clamp]
|   Voltage   I(typ)   I(min)   I(max)
-1.1V     -34.74mA   -30.21mA   -42.91mA
-941.6mV  -25.02mA   -21.26mA   -31.32mA
-796.4mV  -16.11mA   -13.14mA   -21.19mA
-730.4mV  -12.3mA    -9.678mA   -16.56mA
-667.7mV  -8.907mA   -6.722mA   -12.29mA
-595.1mV  -5.4mA     -3.899mA   -7.688mA
-522.5mV  -2.665mA   -1.903mA   -3.81mA
-466.4mV  -1.295mA   -941.5uA   -1.69mA
-413.6mV  -568.9uA   -416.1uA   -620.4uA
-350.9mV  -167.1uA   -125.7uA   -147.4uA
-245.3mV  -11.85uA   -10.01uA   -6.34uA
2.2V      0A         0A         0A
[Pullup]
|   Voltage   I(typ)   I(min)   I(max)
-1.1V     6.276uA    9.671uA    2.829uA
226.6mV   -42.07uA   -43.47uA   -42.82uA
342.1mV   -380.3uA   -315.5uA   -524.6uA
434.5mV   -1.384mA   -1.135mA   -1.75mA
546.7mV   -3.712mA   -3.398mA   -4.054mA
691.9mV   -7.808mA   -8.046mA   -7.726mA
1.062V    -19.96mA   -22.78mA   -18.69mA
1.401V    -31.76mA   -36.29mA   -29.82mA
1.576V    -37.53mA   -42.43mA   -35.7mA
1.698V    -40.75mA   -45.75mA   -39.28mA
1.89V     -45.83mA   -49.59mA   -45.19mA
2.2V      -55.05mA   -55.16mA   -56.74mA
[POWER Clamp]
|   Voltage   I(typ)   I(min)   I(max)
-1.1V     3.033mA    3.633mA    2.184mA
-1.044V   2.381mA    2.967mA    1.653mA
-984.5mV  1.782mA    2.31mA     1.205mA
-915.2mV  1.224mA    1.639mA    781.2uA
-852.5mV  818.2uA    1.148mA    543.6uA
-776.6mV  434.3uA    683.3uA    390.2uA
-710.6mV  232.1uA    359.1uA    273.1uA
-651.2mV  138.6uA    162.3uA    181.2uA
-591.8mV  77.96uA    64.82uA    105.5uA
-489.5mV  17.8uA     10.83uA    22.44uA
-377.3mV  1.511uA    1.058uA    1.221uA
2.2V      0A         0A         0A
[Ramp]
|   typ   min   max
| 20% - 80%
dV/dt_r   239.98m/35.71p   227.55m/40.05p   263.11m/30.63p
dV/dt_f   85.15m/70.66p   76.64m/82.72p   100.80m/59.41p
| 25% - 75%
|dV/dt_r   199.98m/28.42p   189.63m/31.82p   219.26m/24.42p
|dV/dt_f   70.95m/56.15p   63.87m/65.16p   84.00m/47.33p
R_load = 50
[Rising Waveform]
R_fixture = 50
V_fixture = 0.0
|   Time   V(typ)   V(min)   V(max)
0s        1.129mV    1.006mV    811.2uV
57ps      706.4uV    -98.67uV   12.39mV
65ps      4.663mV    -441.9uV   54.75mV
77ps      19.82mV    3.132mV    176.5mV
86ps      61.27mV    9.777mV    263.4mV
99ps      163.1mV    30.04mV    350.3mV
126ps     326.6mV    185.5mV    422.2mV
151ps     381.1mV    309mV      436.4mV
183ps     398.1mV    365.7mV    439.1mV
372ps     401.1mV    380.3mV    439.3mV
[Falling Waveform]
R_fixture   = 50
V_fixture   = 1.1
V_fixture_min = 1.06
V_fixture_max = 1.17
|   Time   V(typ)   V(min)   V(max)
0s        1.1V       1.06V      1.17V
51ps      1.101V     1.06V      1.171V
68ps      1.099V     1.062V     1.161V
97ps      1.079V     1.051V     1.102V
122ps     1.042V     1.036V     1.057V
137ps     1.021V     1.021V     1.039V
165ps     992.1mV    990.1mV    1.019V
202ps     972.1mV    960.4mV    1.008V
241ps     963.2mV    944.2mV    1.004V
372ps     958.1mV    932.3mV    1.002V
[Rising Waveform]
R_fixture   = 50
V_fixture   = 1.1
V_fixture_min = 1.06
V_fixture_max = 1.17
|   Time   V(typ)   V(min)   V(max)
0s        957.9mV    931.6mV    1.002V
45ps      955.9mV    930.6mV    1.001V
55ps      956.2mV    928.1mV    1.017V
70ps      980.5mV    930.7mV    1.07V
78ps      1.004V     941.8mV    1.093V
96ps      1.048V     986.8mV    1.123V
114ps     1.069V     1.023V     1.14V
133ps     1.081V     1.041V     1.152V
208ps     1.097V     1.058V     1.167V
372ps     1.1V       1.06V      1.17V
[Falling Waveform]
R_fixture = 50
V_fixture = 0.0
|   Time   V(typ)   V(min)   V(max)
0s        401.2mV    380.4mV    439.4mV
56ps      407.6mV    381.4mV    443.1mV
73ps      402.3mV    393.3mV    344.5mV
86ps      337.8mV    386.4mV    222.3mV
100ps     230.8mV    329.6mV    140.9mV
118ps     132.5mV    217.3mV    80.31mV
141ps     67.28mV    112.8mV    39.64mV
168ps     31.2mV     52.38mV    17.57mV
208ps     10.67mV    17.86mV    5.644mV
372ps     1.281mV    1.279mV    863.3uV
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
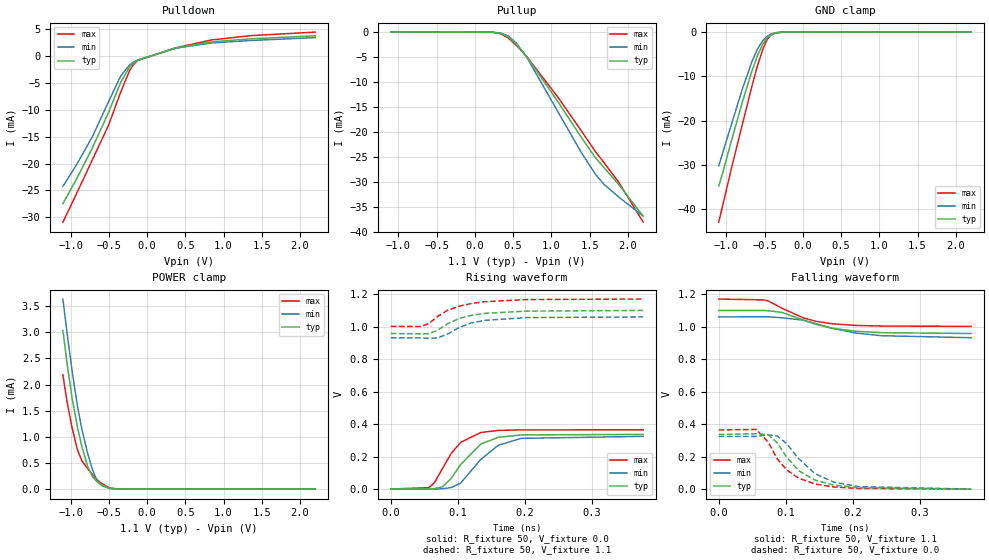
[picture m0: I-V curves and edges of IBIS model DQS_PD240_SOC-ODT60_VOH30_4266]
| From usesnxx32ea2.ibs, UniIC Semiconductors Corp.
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| DQS_PD240_SOC-ODT60_VOH30_4266
| (240 Ohm Pulldown, 60 Ohm System ODT Setting, VOH=VDDQ/3.0, 3200-4266Mbps)
[Model]   DQS_PD240_SOC-ODT60_VOH30_4266
Model_type   I/O
Vinl = 123.333mV
Vinh = 243.333mV
Vmeas = 183.333mV
Vref = 0.0mV
Cref = 0.0pF
Rref = 60.000Ohm
|   typ   min   max
|C_comp   0.849pF   0.799pF   0.899pF
C_comp_pullup   0.4245pF   0.3995pF   0.4495pF
C_comp_pulldown   0.4245pF   0.3995pF   0.4495pF
| Note: C_comp changes when the ODT circuit is enabled.
[Model Spec]
| Input threshold voltage corners
Vinl   0.1233V   0.1167V   0.1350V
Vinh   0.2433V   0.2367V   0.2550V
| Measurement voltage corners
Vmeas   0.1833V   0.1767V   0.1950V
| Timing spec test load voltage corners
Vref   0.0000V   0.0000V   0.0000V
| Dynamic Overshoot Parameters from LPDDR4 Specification
D_overshoot_ampl_h   0.30   NA   NA
D_overshoot_ampl_l   0.30   NA   NA
D_overshoot_area_h   0.1n   NA   NA
D_overshoot_area_l   0.1n   NA   NA
[Voltage Range]   1.1000V   1.0600V   1.1700V
[Pullup Reference]   1.1000V   1.0600V   1.1700V
| Junction Temperature (Ambient temp is 35C typ 95C min -40C max)
[Temperature Range]   50.0   110.0   -40.0
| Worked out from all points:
|   slope of the pulldown table from 0 to 0.165 V, typ, clamps not added: 223 ohm
|   slope of the pullup table from 0 to 0.165 V, typ, clamps not added: 19.4 kohm
|   GND clamp passes 1 mA (typ) near -0.45 V on its own axis
|   POWER clamp passes 1 mA (typ) near -0.88 V on its own axis
|   rising waveform, R_fixture 50, V_fixture 0.0: 20-80 % time 40.6ps typ, 44.8ps min, 35.3ps max; typ from 0.001 V to 0.337 V
|   falling waveform, R_fixture 50, V_fixture 1.1: 20-80 % time 68.5ps typ, 78.1ps min, 58.1ps max; typ from 1.1 V to 0.958 V
|   rising waveform, R_fixture 50, V_fixture 1.1: 20-80 % time 49.4ps typ, 47.5ps min, 50.5ps max; typ from 0.958 V to 1.1 V
|   falling waveform, R_fixture 50, V_fixture 0.0: 20-80 % time 47.1ps typ, 51.6ps min, 43.1ps max; typ from 0.337 V to 0.001 V
[Pulldown]
|   Voltage   I(typ)   I(min)   I(max)
-1.1V     -27.48mA   -24.26mA   -30.94mA
-921.8mV  -22.88mA   -20.24mA   -25.63mA
-717.2mV  -17.17mA   -15.08mA   -19.39mA
-502.7mV  -10.47mA   -8.452mA   -12.86mA
-344.3mV  -4.883mA   -3.676mA   -6.675mA
-228.8mV  -1.996mA   -1.62mA    -2.701mA
-182.6mV  -1.317mA   -1.143mA   -1.644mA
-123.2mV  -746.2uA   -693.6uA   -809.7uA
375.1mV   1.526mA    1.498mA    1.571mA
843.7mV   2.68mA     2.467mA    3.039mA
1.355V    3.244mA    2.938mA    3.836mA
2.2V      3.814mA    3.471mA    4.502mA
[GND Clamp]
|   Voltage   I(typ)   I(min)   I(max)
-1.1V     -34.74mA   -30.21mA   -42.91mA
-1.05V    -31.86mA   -27.33mA   -39.27mA
-935mV    -24.6mA    -20.89mA   -30.85mA
-793.1mV  -15.92mA   -12.96mA   -20.95mA
-664.4mV  -8.736mA   -6.578mA   -12.07mA
-591.8mV  -5.255mA   -3.789mA   -7.493mA
-522.5mV  -2.665mA   -1.905mA   -3.811mA
-466.4mV  -1.296mA   -944.3uA   -1.691mA
-416.9mV  -596.8uA   -441.6uA   -665.1uA
-354.2mV  -178.8uA   -135uA     -160uA
-255.2mV  -14.81uA   -13.09uA   -8.787uA
2.2V      0A         0A         0A
[Pullup]
|   Voltage   I(typ)   I(min)   I(max)
-1.1V     4.184uA    6.447uA    1.886uA
229.9mV   -30.26uA   -30.87uA   -31.04uA
332.2mV   -215uA     -179.9uA   -295.3uA
434.5mV   -925.5uA   -758.7uA   -1.171mA
546.7mV   -2.488mA   -2.279mA   -2.716mA
678.7mV   -4.971mA   -5.087mA   -4.942mA
1.088V    -14.01mA   -16.05mA   -13.11mA
1.388V    -21.03mA   -24.07mA   -19.73mA
1.576V    -25.2mA    -28.5mA    -23.98mA
1.688V    -27.16mA   -30.52mA   -26.18mA
1.887V    -30.68mA   -33.15mA   -30.26mA
2.2V      -36.89mA   -36.87mA   -38.1mA
[POWER Clamp]
|   Voltage   I(typ)   I(min)   I(max)
-1.1V     3.033mA    3.633mA    2.184mA
-1.044V   2.381mA    2.967mA    1.653mA
-977.9mV  1.723mA    2.241mA    1.161mA
-908.6mV  1.177mA    1.582mA    748.3uA
-852.5mV  818.2uA    1.148mA    543.5uA
-776.6mV  434.2uA    683.3uA    390.2uA
-710.6mV  232.2uA    359.1uA    273.1uA
-654.5mV  142.6uA    170.5uA    185.9uA
-598.4mV  83.66uA    71.98uA    113uA
-489.5mV  17.78uA    10.87uA    22.46uA
-367.4mV  1.186uA    875nA      943.4nA
2.2V      0A         0A         0A
[Ramp]
|   typ   min   max
| 20% - 80%
dV/dt_r   201.65m/40.56p   194.40m/44.80p   218.77m/35.31p
dV/dt_f   85.16m/68.48p   76.64m/78.18p   100.79m/58.27p
| 25% - 75%
|dV/dt_r   168.05m/32.33p   162.00m/35.68p   182.31m/28.11p
|dV/dt_f   70.97m/54.49p   63.86m/61.99p   83.99m/46.29p
R_load = 50
[Rising Waveform]
R_fixture = 50
V_fixture = 0.0
|   Time   V(typ)   V(min)   V(max)
0s        757uV      671.7uV    544.7uV
57ps      502.7uV    -132.1uV   8.968mV
65ps      3.285mV    -327.9uV   39.69mV
77ps      14.32mV    2.387mV    127.4mV
90ps      65.91mV    9.777mV    219.9mV
104ps     151.2mV    37.02mV    287.5mV
134ps     277.7mV    182.5mV    348.4mV
160ps     318.7mV    269.9mV    361.3mV
194ps     333.6mV    312.5mV    364.6mV
376ps     336.8mV    324.7mV    365.2mV
[Falling Waveform]
R_fixture   = 50
V_fixture   = 1.1
V_fixture_min = 1.06
V_fixture_max = 1.17
|   Time   V(typ)   V(min)   V(max)
0s        1.1V       1.06V      1.17V
67ps      1.1V       1.061V     1.165V
74ps      1.098V     1.061V     1.158V
94ps      1.088V     1.055V     1.114V
126ps     1.041V     1.04V      1.054V
144ps     1.015V     1.02V      1.034V
169ps     990.7mV    990.1mV    1.018V
203ps     972.4mV    961.7mV    1.008V
243ps     963.2mV    944.4mV    1.004V
376ps     958.1mV    932.3mV    1.002V
[Rising Waveform]
R_fixture   = 50
V_fixture   = 1.1
V_fixture_min = 1.06
V_fixture_max = 1.17
|   Time   V(typ)   V(min)   V(max)
0s        957.9mV    931.6mV    1.002V
45ps      956.1mV    930.6mV    1.001V
57ps      957.6mV    928mV      1.02V
70ps      978.3mV    931.1mV    1.064V
85ps      1.019V     955.5mV    1.102V
102ps     1.051V     995.5mV    1.126V
119ps     1.069V     1.022V     1.142V
140ps     1.082V     1.039V     1.154V
203ps     1.096V     1.056V     1.167V
376ps     1.1V       1.06V      1.17V
[Falling Waveform]
R_fixture = 50
V_fixture = 0.0
|   Time   V(typ)   V(min)   V(max)
0s        336.9mV    324.8mV    365.2mV
56ps      341.6mV    325.6mV    368.1mV
74ps      336.5mV    334.8mV    288.7mV
87ps      285.9mV    327.7mV    188mV
101ps     198.4mV    281.2mV    119.6mV
119ps     114.9mV    189.1mV    68.42mV
143ps     56.99mV    97.18mV    32.73mV
171ps     25.76mV    44.46mV    14.19mV
208ps     9.432mV    16.47mV    4.912mV
376ps     911.3uV    965.7uV    603.5uV
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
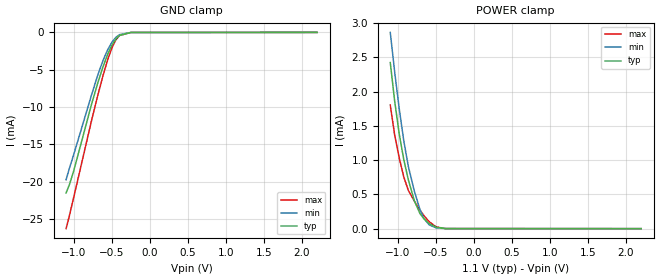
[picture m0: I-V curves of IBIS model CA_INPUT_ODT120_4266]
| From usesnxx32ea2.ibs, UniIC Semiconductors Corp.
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| CA_INPUT_ODT120_4266 (with 120ohm ODT, 3200-4266Mbps)
[Model]   CA_INPUT_ODT120_4266
Model_type   Input
Vinl = 110.833mV
Vinh = 255.833mV
|   typ   min   max
|C_comp   0.671pF   0.621pF   0.725pF
C_comp_power_clamp   0.3355pF   0.3105pF   0.3625pF
C_comp_gnd_clamp   0.3355pF   0.3105pF   0.3625pF
| Note: C_comp changes when the ODT circuit is enabled.
[Model Spec]
| Input threshold voltage corners
Vinl   0.1108V   0.1042V   0.1225V
Vinh   0.2558V   0.2492V   0.2675V
| Dynamic Overshoot Parameters from LPDDR4 Specification
D_overshoot_ampl_h   0.30   NA   NA
D_overshoot_ampl_l   0.30   NA   NA
D_overshoot_area_h   0.1n   NA   NA
D_overshoot_area_l   0.1n   NA   NA
[Voltage Range]   1.1000V   1.0600V   1.1700V
[POWER Clamp Reference]   1.1000V   1.0600V   1.1700V
| Junction Temperature (Ambient temp is 35C typ 95C min -40C max)
[Temperature Range]   50.0   110.0   -40.0
[Add Submodel]
| Submodel Name   Mode
120ohm_ODT_4266   Non-Driving
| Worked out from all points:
|   GND clamp passes 1 mA (typ) near -0.45 V on its own axis
|   POWER clamp passes 1 mA (typ) near -0.92 V on its own axis
[GND Clamp]
|   Voltage   I(typ)   I(min)   I(max)
-1.1V     -21.5mA    -19.73mA   -26.28mA
-1.057V   -20.41mA   -18.22mA   -24.57mA
-1.001V   -18.6mA    -16.41mA   -22.15mA
-763.4mV  -9.562mA   -8.321mA   -11.73mA
-680.9mV  -6.696mA   -5.635mA   -8.352mA
-614.9mV  -4.625mA   -3.777mA   -5.81mA
-552.2mV  -2.909mA   -2.311mA   -3.642mA
-496.1mV  -1.68mA    -1.302mA   -2.041mA
-446.6mV  -895.5uA   -681.9uA   -1.019mA
-397.1mV  -403uA     -305.7uA   -413.1uA
-248.6mV  -11.98uA   -10.81uA   -7.088uA
2.2V      0A         0A         0A
[POWER Clamp]
|   Voltage   I(typ)   I(min)   I(max)
-1.1V     2.422mA    2.862mA    1.802mA
-1.041V   1.851mA    2.277mA    1.359mA
-981.2mV  1.374mA    1.741mA    1.027mA
-921.8mV  1.005mA    1.277mA    751.6uA
-862.4mV  713uA      909uA      559.1uA
-783.2mV  406.3uA    545.8uA    401.7uA
-710.6mV  222.9uA    283.8uA    272.7uA
-657.8mV  145uA      149.1uA    190.3uA
-588.5mV  74.68uA    55.78uA    101.5uA
-496.1mV  19.98uA    11.76uA    25.38uA
-370.7mV  1.131uA    772.7nA    812.6nA
2.2V      0A         0A         0A
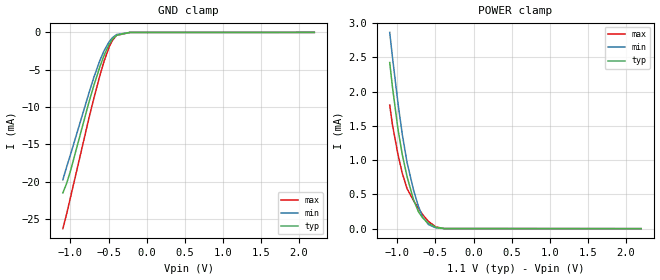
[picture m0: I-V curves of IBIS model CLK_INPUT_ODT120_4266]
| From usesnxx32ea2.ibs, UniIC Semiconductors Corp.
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| CLK_INPUT_ODT120_4266 (with 120ohm ODT, 3200-4266Mbps)
[Model]   CLK_INPUT_ODT120_4266
Model_type   Input
Vinl = 110.833mV
Vinh = 255.833mV
|   typ   min   max
|C_comp   0.648pF   0.598pF   0.702pF
C_comp_power_clamp   0.3240pF   0.2990pF   0.3510pF
C_comp_gnd_clamp   0.3240pF   0.2990pF   0.3510pF
| Note: C_comp changes when the ODT circuit is enabled.
[Model Spec]
| Input threshold voltage corners
Vinl   0.1108V   0.1042V   0.1225V
Vinh   0.2558V   0.2492V   0.2675V
| Dynamic Overshoot Parameters from LPDDR4 Specification
D_overshoot_ampl_h   0.30   NA   NA
D_overshoot_ampl_l   0.30   NA   NA
D_overshoot_area_h   0.1n   NA   NA
D_overshoot_area_l   0.1n   NA   NA
[Voltage Range]   1.1000V   1.0600V   1.1700V
[POWER Clamp Reference]   1.1000V   1.0600V   1.1700V
| Junction Temperature (Ambient temp is 35C typ 95C min -40C max)
[Temperature Range]   50.0   110.0   -40.0
[Add Submodel]
| Submodel Name   Mode
120ohm_ODT_4266   Non-Driving
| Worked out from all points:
|   GND clamp passes 1 mA (typ) near -0.45 V on its own axis
|   POWER clamp passes 1 mA (typ) near -0.92 V on its own axis
[GND Clamp]
|   Voltage   I(typ)   I(min)   I(max)
-1.1V     -21.49mA   -19.74mA   -26.28mA
-1.05V    -20.21mA   -18mA      -24.3mA
-1.001V   -18.6mA    -16.41mA   -22.15mA
-760.1mV  -9.441mA   -8.207mA   -11.59mA
-690.8mV  -7.023mA   -5.938mA   -8.749mA
-611.6mV  -4.528mA   -3.695mA   -5.689mA
-558.8mV  -3.072mA   -2.454mA   -3.854mA
-492.8mV  -1.616mA   -1.25mA    -1.96mA
-449.9mV  -937.2uA   -717.2uA   -1.077mA
-393.8mV  -384.3uA   -286.1uA   -384.4uA
-218.9mV  -5.073uA   -4.963uA   -2.555uA
2.2V      0A         0A         0A
[POWER Clamp]
|   Voltage   I(typ)   I(min)   I(max)
-1.1V     2.422mA    2.862mA    1.802mA
-1.064V   2.064mA    2.5mA      1.513mA
-991.1mV  1.446mA    1.826mA    1.078mA
-935mV    1.079mA    1.372mA    807.4uA
-872.3mV  757.9uA    964uA      583.2uA
-786.5mV  417uA      559.2uA    407.8uA
-723.8mV  249.1uA    325.9uA    295uA
-667.7mV  157.6uA    169.9uA    204.9uA
-591.8mV  77.95uA    60.06uA    105.2uA
-492.8mV  18.73uA    10.94uA    23.72uA
-383.9mV  1.579uA    1.072uA    1.286uA
2.2V      0A         0A         0A
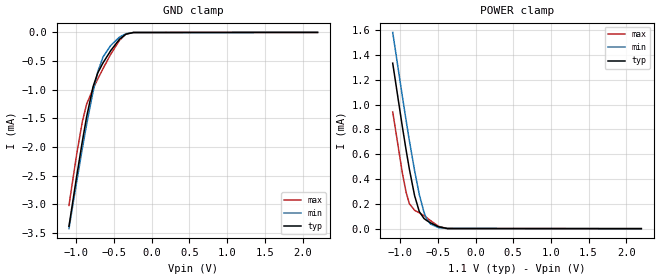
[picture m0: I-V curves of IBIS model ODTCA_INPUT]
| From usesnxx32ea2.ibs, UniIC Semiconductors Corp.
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| ODTCA_INPUT
[Model]   ODTCA_INPUT
Model_type   Input
Vinl = 275.000mV
Vinh = 825.000mV
|   typ   min   max
|C_comp   0.625pF   0.575pF   0.675pF
C_comp_power_clamp   0.3125pF   0.2875pF   0.3375pF
C_comp_gnd_clamp   0.3125pF   0.2875pF   0.3375pF
[Model Spec]
| Input threshold voltage corners
Vinl   0.2750V   0.2650V   0.2925V
Vinh   0.8250V   0.7950V   0.8775V
| Dynamic Overshoot Parameters from LPDDR4 Specification
[Voltage Range]   1.1000V   1.0600V   1.1700V
| Junction Temperature (Ambient temp is 35C typ 95C min -40C max)
[Temperature Range]   50.0   110.0   -40.0
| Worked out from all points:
|   GND clamp passes 1 mA (typ) near -0.79 V on its own axis
|   POWER clamp passes 1 mA (typ) near -1.02 V on its own axis
[GND Clamp]
|   Voltage   I(typ)   I(min)   I(max)
-1.1V     -3.387mA   -3.428mA   -3.022mA
-997.7mV  -2.514mA   -2.611mA   -2.129mA
-921.8mV  -1.898mA   -2.024mA   -1.555mA
-865.7mV  -1.477mA   -1.61mA    -1.254mA
-779.9mV  -947.2uA   -1.035mA   -982.9uA
-717.2mV  -706.1uA   -687uA     -813.4uA
-647.9mV  -531.8uA   -429.9uA   -632.6uA
-545.6mV  -318.1uA   -228.6uA   -381.3uA
-430.1mV  -120.6uA   -82.73uA   -140.1uA
-344.3mV  -31.73uA   -23.12uA   -28.95uA
-245.3mV  -2.31uA    -2.579uA   -1.004uA
2.2V      0A         0A         0A
[POWER Clamp]
|   Voltage   I(typ)   I(min)   I(max)
-1.1V     1.334mA    1.582mA    941.4uA
-971.3mV  819.2uA    1.064mA    446.6uA
-921.8mV  632.6uA    871.1uA    292.6uA
-878.9mV  480uA      710.7uA    201.2uA
-809.6mV  266.3uA    467.9uA    148.3uA
-746.9mV  137.2uA    275.5uA    127.9uA
-684.2mV  81.44uA    130.1uA    104uA
-647.9mV  65.21uA    76.95uA    88.08uA
-598.4mV  47.3uA     37.48uA    64.79uA
-492.8mV  15.07uA    8.609uA    18.92uA
-374mV    1.255uA    816.8nA    892.6nA
2.2V      0A         0A         0A
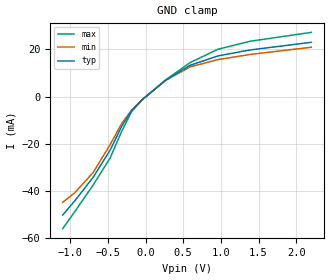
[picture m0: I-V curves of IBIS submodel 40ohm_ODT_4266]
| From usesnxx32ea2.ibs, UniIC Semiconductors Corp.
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| SUBMODEL 40ohm_ODT_4266
[Submodel]   40ohm_ODT_4266
Submodel_type   Dynamic_clamp
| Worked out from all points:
|   GND clamp passes 1 mA (typ) near -0.03 V on its own axis
[GND Clamp]
|   Voltage   I(typ)   I(min)   I(max)
-1.1V     -50.19mA   -44.8mA    -55.96mA
-938.3mV  -44.12mA   -40.71mA   -48.69mA
-694.1mV  -34.13mA   -32.11mA   -37.38mA
-469.7mV  -22.64mA   -20.3mA    -25.98mA
-314.6mV  -12.45mA   -11.23mA   -14.53mA
-185.9mV  -5.987mA   -5.787mA   -6.41mA
-44mV     -1.309mA   -1.3mA     -1.288mA
266.2mV   6.933mA    6.828mA    7.065mA
592.9mV   13.27mA    12.58mA    14.42mA
962.5mV   17.23mA    15.68mA    20.06mA
1.391V    19.76mA    17.85mA    23.45mA
2.2V      22.98mA    20.89mA    27.18mA
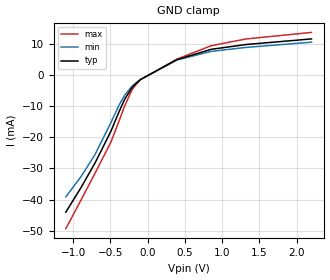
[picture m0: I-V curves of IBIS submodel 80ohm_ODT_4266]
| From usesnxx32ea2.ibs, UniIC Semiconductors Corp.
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| SUBMODEL 80ohm_ODT_4266
[Submodel]   80ohm_ODT_4266
Submodel_type   Dynamic_clamp
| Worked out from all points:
|   GND clamp passes 1 mA (typ) near -0.06 V on its own axis
[GND Clamp]
|   Voltage   I(typ)   I(min)   I(max)
-1.1V     -44.04mA   -39.14mA   -49.32mA
-895.4mV  -36.15mA   -32.64mA   -40.11mA
-707.3mV  -28.26mA   -25.56mA   -31.56mA
-492.8mV  -18.02mA   -15.26mA   -21.5mA
-380.6mV  -11.6mA    -9.536mA   -14.57mA
-308mV    -7.79mA    -6.494mA   -9.914mA
-205.7mV  -3.901mA   -3.535mA   -4.589mA
-100.1mV  -1.593mA   -1.548mA   -1.61mA
391.6mV   4.819mA    4.706mA    5.003mA
853.6mV   8.145mA    7.471mA    9.311mA
1.319V    9.68mA     8.755mA    11.46mA
2.2V      11.48mA    10.44mA    13.57mA
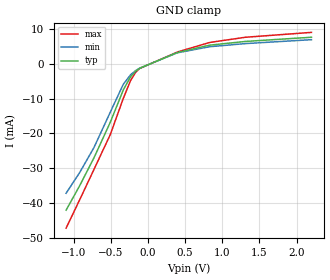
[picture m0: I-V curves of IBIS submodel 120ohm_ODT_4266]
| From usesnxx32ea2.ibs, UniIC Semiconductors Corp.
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| SUBMODEL 120ohm_ODT_4266
[Submodel]   120ohm_ODT_4266
Submodel_type   Dynamic_clamp
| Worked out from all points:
|   GND clamp passes 1 mA (typ) near -0.09 V on its own axis
[GND Clamp]
|   Voltage   I(typ)   I(min)   I(max)
-1.1V     -42.06mA   -37.19mA   -47.23mA
-918.5mV  -35.07mA   -31.29mA   -39.13mA
-723.8mV  -26.95mA   -23.99mA   -30.29mA
-506mV    -16.8mA    -13.89mA   -20.34mA
-331.1mV  -7.492mA   -5.881mA   -9.942mA
-232.1mV  -3.67mA    -3.106mA   -4.742mA
-162.8mV  -2.072mA   -1.895mA   -2.372mA
-110mV    -1.263mA   -1.205mA   -1.314mA
394.9mV   3.273mA    3.191mA    3.412mA
830.5mV   5.39mA     4.943mA    6.163mA
1.309V    6.457mA    5.836mA    7.658mA
2.2V      7.669mA    6.971mA    9.07mA
